VERSION 5.8 ;
BUSBITCHARS "[]" ;
DIVIDERCHAR "/" ;
UNITS
    DATABASE MICRONS 1000 ;
END UNITS

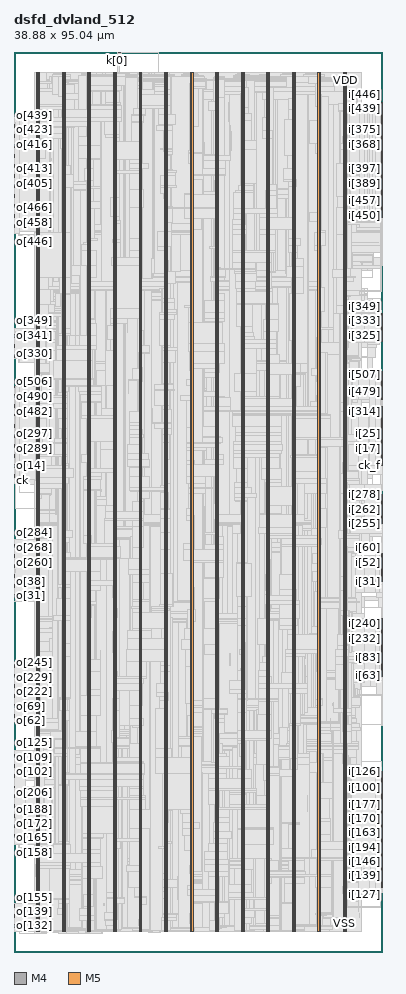
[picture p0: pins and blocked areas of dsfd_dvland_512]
MACRO dsfd_dvland_512
  FOREIGN dsfd_dvland_512 0 0 ;
  CLASS BLOCK ;
  SIZE 38.88 BY 95.04 ;
  PIN ck
    DIRECTION INPUT ;
    USE SIGNAL ;
    PORT
      LAYER M4 ;
        RECT  0 49.776 0.084 49.8 ;
    END
  END ck
  PIN ck_f
    DIRECTION INPUT ;
    USE SIGNAL ;
    PORT
      LAYER M4 ;
        RECT  38.796 51.408 38.88 51.432 ;
    END
  END ck_f
  PIN fault
    DIRECTION OUTPUT ;
    USE SIGNAL ;
    PORT
      LAYER M4 ;
        RECT  0 49.872 0.084 49.896 ;
    END
  END fault
  PIN i[0]
    DIRECTION INPUT ;
    USE SIGNAL ;
    PORT
      LAYER M4 ;
        RECT  38.796 51.504 38.88 51.528 ;
    END
  END i[0]
  PIN i[100]
    DIRECTION INPUT ;
    USE SIGNAL ;
    PORT
      LAYER M4 ;
        RECT  38.796 16.56 38.88 16.584 ;
    END
  END i[100]
  PIN i[101]
    DIRECTION INPUT ;
    USE SIGNAL ;
    PORT
      LAYER M4 ;
        RECT  38.796 16.656 38.88 16.68 ;
    END
  END i[101]
  PIN i[102]
    DIRECTION INPUT ;
    USE SIGNAL ;
    PORT
      LAYER M4 ;
        RECT  38.796 16.752 38.88 16.776 ;
    END
  END i[102]
  PIN i[103]
    DIRECTION INPUT ;
    USE SIGNAL ;
    PORT
      LAYER M4 ;
        RECT  38.796 16.848 38.88 16.872 ;
    END
  END i[103]
  PIN i[104]
    DIRECTION INPUT ;
    USE SIGNAL ;
    PORT
      LAYER M4 ;
        RECT  38.796 16.944 38.88 16.968 ;
    END
  END i[104]
  PIN i[105]
    DIRECTION INPUT ;
    USE SIGNAL ;
    PORT
      LAYER M4 ;
        RECT  38.796 17.04 38.88 17.064 ;
    END
  END i[105]
  PIN i[106]
    DIRECTION INPUT ;
    USE SIGNAL ;
    PORT
      LAYER M4 ;
        RECT  38.796 17.136 38.88 17.16 ;
    END
  END i[106]
  PIN i[107]
    DIRECTION INPUT ;
    USE SIGNAL ;
    PORT
      LAYER M4 ;
        RECT  38.796 17.232 38.88 17.256 ;
    END
  END i[107]
  PIN i[108]
    DIRECTION INPUT ;
    USE SIGNAL ;
    PORT
      LAYER M4 ;
        RECT  38.796 17.328 38.88 17.352 ;
    END
  END i[108]
  PIN i[109]
    DIRECTION INPUT ;
    USE SIGNAL ;
    PORT
      LAYER M4 ;
        RECT  38.796 17.424 38.88 17.448 ;
    END
  END i[109]
  PIN i[10]
    DIRECTION INPUT ;
    USE SIGNAL ;
    PORT
      LAYER M4 ;
        RECT  38.796 52.464 38.88 52.488 ;
    END
  END i[10]
  PIN i[110]
    DIRECTION INPUT ;
    USE SIGNAL ;
    PORT
      LAYER M4 ;
        RECT  38.796 17.52 38.88 17.544 ;
    END
  END i[110]
  PIN i[111]
    DIRECTION INPUT ;
    USE SIGNAL ;
    PORT
      LAYER M4 ;
        RECT  38.796 17.616 38.88 17.64 ;
    END
  END i[111]
  PIN i[112]
    DIRECTION INPUT ;
    USE SIGNAL ;
    PORT
      LAYER M4 ;
        RECT  38.796 17.712 38.88 17.736 ;
    END
  END i[112]
  PIN i[113]
    DIRECTION INPUT ;
    USE SIGNAL ;
    PORT
      LAYER M4 ;
        RECT  38.796 17.808 38.88 17.832 ;
    END
  END i[113]
  PIN i[114]
    DIRECTION INPUT ;
    USE SIGNAL ;
    PORT
      LAYER M4 ;
        RECT  38.796 17.904 38.88 17.928 ;
    END
  END i[114]
  PIN i[115]
    DIRECTION INPUT ;
    USE SIGNAL ;
    PORT
      LAYER M4 ;
        RECT  38.796 18 38.88 18.024 ;
    END
  END i[115]
  PIN i[116]
    DIRECTION INPUT ;
    USE SIGNAL ;
    PORT
      LAYER M4 ;
        RECT  38.796 18.096 38.88 18.12 ;
    END
  END i[116]
  PIN i[117]
    DIRECTION INPUT ;
    USE SIGNAL ;
    PORT
      LAYER M4 ;
        RECT  38.796 18.192 38.88 18.216 ;
    END
  END i[117]
  PIN i[118]
    DIRECTION INPUT ;
    USE SIGNAL ;
    PORT
      LAYER M4 ;
        RECT  38.796 18.288 38.88 18.312 ;
    END
  END i[118]
  PIN i[119]
    DIRECTION INPUT ;
    USE SIGNAL ;
    PORT
      LAYER M4 ;
        RECT  38.796 18.384 38.88 18.408 ;
    END
  END i[119]
  PIN i[11]
    DIRECTION INPUT ;
    USE SIGNAL ;
    PORT
      LAYER M4 ;
        RECT  38.796 52.56 38.88 52.584 ;
    END
  END i[11]
  PIN i[120]
    DIRECTION INPUT ;
    USE SIGNAL ;
    PORT
      LAYER M4 ;
        RECT  38.796 18.48 38.88 18.504 ;
    END
  END i[120]
  PIN i[121]
    DIRECTION INPUT ;
    USE SIGNAL ;
    PORT
      LAYER M4 ;
        RECT  38.796 18.576 38.88 18.6 ;
    END
  END i[121]
  PIN i[122]
    DIRECTION INPUT ;
    USE SIGNAL ;
    PORT
      LAYER M4 ;
        RECT  38.796 18.672 38.88 18.696 ;
    END
  END i[122]
  PIN i[123]
    DIRECTION INPUT ;
    USE SIGNAL ;
    PORT
      LAYER M4 ;
        RECT  38.796 18.768 38.88 18.792 ;
    END
  END i[123]
  PIN i[124]
    DIRECTION INPUT ;
    USE SIGNAL ;
    PORT
      LAYER M4 ;
        RECT  38.796 18.864 38.88 18.888 ;
    END
  END i[124]
  PIN i[125]
    DIRECTION INPUT ;
    USE SIGNAL ;
    PORT
      LAYER M4 ;
        RECT  38.796 18.96 38.88 18.984 ;
    END
  END i[125]
  PIN i[126]
    DIRECTION INPUT ;
    USE SIGNAL ;
    PORT
      LAYER M4 ;
        RECT  38.796 19.056 38.88 19.08 ;
    END
  END i[126]
  PIN i[127]
    DIRECTION INPUT ;
    USE SIGNAL ;
    PORT
      LAYER M4 ;
        RECT  38.796 6.864 38.88 6.888 ;
    END
  END i[127]
  PIN i[128]
    DIRECTION INPUT ;
    USE SIGNAL ;
    PORT
      LAYER M4 ;
        RECT  38.796 6.96 38.88 6.984 ;
    END
  END i[128]
  PIN i[129]
    DIRECTION INPUT ;
    USE SIGNAL ;
    PORT
      LAYER M4 ;
        RECT  38.796 7.056 38.88 7.08 ;
    END
  END i[129]
  PIN i[12]
    DIRECTION INPUT ;
    USE SIGNAL ;
    PORT
      LAYER M4 ;
        RECT  38.796 52.656 38.88 52.68 ;
    END
  END i[12]
  PIN i[130]
    DIRECTION INPUT ;
    USE SIGNAL ;
    PORT
      LAYER M4 ;
        RECT  38.796 7.152 38.88 7.176 ;
    END
  END i[130]
  PIN i[131]
    DIRECTION INPUT ;
    USE SIGNAL ;
    PORT
      LAYER M4 ;
        RECT  38.796 7.248 38.88 7.272 ;
    END
  END i[131]
  PIN i[132]
    DIRECTION INPUT ;
    USE SIGNAL ;
    PORT
      LAYER M4 ;
        RECT  38.796 7.344 38.88 7.368 ;
    END
  END i[132]
  PIN i[133]
    DIRECTION INPUT ;
    USE SIGNAL ;
    PORT
      LAYER M4 ;
        RECT  38.796 7.44 38.88 7.464 ;
    END
  END i[133]
  PIN i[134]
    DIRECTION INPUT ;
    USE SIGNAL ;
    PORT
      LAYER M4 ;
        RECT  38.796 7.536 38.88 7.56 ;
    END
  END i[134]
  PIN i[135]
    DIRECTION INPUT ;
    USE SIGNAL ;
    PORT
      LAYER M4 ;
        RECT  38.796 7.632 38.88 7.656 ;
    END
  END i[135]
  PIN i[136]
    DIRECTION INPUT ;
    USE SIGNAL ;
    PORT
      LAYER M4 ;
        RECT  38.796 7.728 38.88 7.752 ;
    END
  END i[136]
  PIN i[137]
    DIRECTION INPUT ;
    USE SIGNAL ;
    PORT
      LAYER M4 ;
        RECT  38.796 7.824 38.88 7.848 ;
    END
  END i[137]
  PIN i[138]
    DIRECTION INPUT ;
    USE SIGNAL ;
    PORT
      LAYER M4 ;
        RECT  38.796 7.92 38.88 7.944 ;
    END
  END i[138]
  PIN i[139]
    DIRECTION INPUT ;
    USE SIGNAL ;
    PORT
      LAYER M4 ;
        RECT  38.796 8.016 38.88 8.04 ;
    END
  END i[139]
  PIN i[13]
    DIRECTION INPUT ;
    USE SIGNAL ;
    PORT
      LAYER M4 ;
        RECT  38.796 52.752 38.88 52.776 ;
    END
  END i[13]
  PIN i[140]
    DIRECTION INPUT ;
    USE SIGNAL ;
    PORT
      LAYER M4 ;
        RECT  38.796 8.112 38.88 8.136 ;
    END
  END i[140]
  PIN i[141]
    DIRECTION INPUT ;
    USE SIGNAL ;
    PORT
      LAYER M4 ;
        RECT  38.796 8.208 38.88 8.232 ;
    END
  END i[141]
  PIN i[142]
    DIRECTION INPUT ;
    USE SIGNAL ;
    PORT
      LAYER M4 ;
        RECT  38.796 8.304 38.88 8.328 ;
    END
  END i[142]
  PIN i[143]
    DIRECTION INPUT ;
    USE SIGNAL ;
    PORT
      LAYER M4 ;
        RECT  38.796 8.4 38.88 8.424 ;
    END
  END i[143]
  PIN i[144]
    DIRECTION INPUT ;
    USE SIGNAL ;
    PORT
      LAYER M4 ;
        RECT  38.796 8.496 38.88 8.52 ;
    END
  END i[144]
  PIN i[145]
    DIRECTION INPUT ;
    USE SIGNAL ;
    PORT
      LAYER M4 ;
        RECT  38.796 8.592 38.88 8.616 ;
    END
  END i[145]
  PIN i[146]
    DIRECTION INPUT ;
    USE SIGNAL ;
    PORT
      LAYER M4 ;
        RECT  38.796 8.688 38.88 8.712 ;
    END
  END i[146]
  PIN i[147]
    DIRECTION INPUT ;
    USE SIGNAL ;
    PORT
      LAYER M4 ;
        RECT  38.796 8.784 38.88 8.808 ;
    END
  END i[147]
  PIN i[148]
    DIRECTION INPUT ;
    USE SIGNAL ;
    PORT
      LAYER M4 ;
        RECT  38.796 8.88 38.88 8.904 ;
    END
  END i[148]
  PIN i[149]
    DIRECTION INPUT ;
    USE SIGNAL ;
    PORT
      LAYER M4 ;
        RECT  38.796 8.976 38.88 9 ;
    END
  END i[149]
  PIN i[14]
    DIRECTION INPUT ;
    USE SIGNAL ;
    PORT
      LAYER M4 ;
        RECT  38.796 52.848 38.88 52.872 ;
    END
  END i[14]
  PIN i[150]
    DIRECTION INPUT ;
    USE SIGNAL ;
    PORT
      LAYER M4 ;
        RECT  38.796 9.072 38.88 9.096 ;
    END
  END i[150]
  PIN i[151]
    DIRECTION INPUT ;
    USE SIGNAL ;
    PORT
      LAYER M4 ;
        RECT  38.796 9.168 38.88 9.192 ;
    END
  END i[151]
  PIN i[152]
    DIRECTION INPUT ;
    USE SIGNAL ;
    PORT
      LAYER M4 ;
        RECT  38.796 9.264 38.88 9.288 ;
    END
  END i[152]
  PIN i[153]
    DIRECTION INPUT ;
    USE SIGNAL ;
    PORT
      LAYER M4 ;
        RECT  38.796 9.36 38.88 9.384 ;
    END
  END i[153]
  PIN i[154]
    DIRECTION INPUT ;
    USE SIGNAL ;
    PORT
      LAYER M4 ;
        RECT  38.796 9.456 38.88 9.48 ;
    END
  END i[154]
  PIN i[155]
    DIRECTION INPUT ;
    USE SIGNAL ;
    PORT
      LAYER M4 ;
        RECT  38.796 9.552 38.88 9.576 ;
    END
  END i[155]
  PIN i[156]
    DIRECTION INPUT ;
    USE SIGNAL ;
    PORT
      LAYER M4 ;
        RECT  38.796 9.648 38.88 9.672 ;
    END
  END i[156]
  PIN i[157]
    DIRECTION INPUT ;
    USE SIGNAL ;
    PORT
      LAYER M4 ;
        RECT  38.796 9.744 38.88 9.768 ;
    END
  END i[157]
  PIN i[158]
    DIRECTION INPUT ;
    USE SIGNAL ;
    PORT
      LAYER M4 ;
        RECT  38.796 9.84 38.88 9.864 ;
    END
  END i[158]
  PIN i[159]
    DIRECTION INPUT ;
    USE SIGNAL ;
    PORT
      LAYER M4 ;
        RECT  38.796 13.008 38.88 13.032 ;
    END
  END i[159]
  PIN i[15]
    DIRECTION INPUT ;
    USE SIGNAL ;
    PORT
      LAYER M4 ;
        RECT  38.796 52.944 38.88 52.968 ;
    END
  END i[15]
  PIN i[160]
    DIRECTION INPUT ;
    USE SIGNAL ;
    PORT
      LAYER M4 ;
        RECT  38.796 13.104 38.88 13.128 ;
    END
  END i[160]
  PIN i[161]
    DIRECTION INPUT ;
    USE SIGNAL ;
    PORT
      LAYER M4 ;
        RECT  38.796 13.2 38.88 13.224 ;
    END
  END i[161]
  PIN i[162]
    DIRECTION INPUT ;
    USE SIGNAL ;
    PORT
      LAYER M4 ;
        RECT  38.796 13.296 38.88 13.32 ;
    END
  END i[162]
  PIN i[163]
    DIRECTION INPUT ;
    USE SIGNAL ;
    PORT
      LAYER M4 ;
        RECT  38.796 13.392 38.88 13.416 ;
    END
  END i[163]
  PIN i[164]
    DIRECTION INPUT ;
    USE SIGNAL ;
    PORT
      LAYER M4 ;
        RECT  38.796 13.488 38.88 13.512 ;
    END
  END i[164]
  PIN i[165]
    DIRECTION INPUT ;
    USE SIGNAL ;
    PORT
      LAYER M4 ;
        RECT  38.796 13.584 38.88 13.608 ;
    END
  END i[165]
  PIN i[166]
    DIRECTION INPUT ;
    USE SIGNAL ;
    PORT
      LAYER M4 ;
        RECT  38.796 13.68 38.88 13.704 ;
    END
  END i[166]
  PIN i[167]
    DIRECTION INPUT ;
    USE SIGNAL ;
    PORT
      LAYER M4 ;
        RECT  38.796 13.776 38.88 13.8 ;
    END
  END i[167]
  PIN i[168]
    DIRECTION INPUT ;
    USE SIGNAL ;
    PORT
      LAYER M4 ;
        RECT  38.796 13.872 38.88 13.896 ;
    END
  END i[168]
  PIN i[169]
    DIRECTION INPUT ;
    USE SIGNAL ;
    PORT
      LAYER M4 ;
        RECT  38.796 13.968 38.88 13.992 ;
    END
  END i[169]
  PIN i[16]
    DIRECTION INPUT ;
    USE SIGNAL ;
    PORT
      LAYER M4 ;
        RECT  38.796 53.04 38.88 53.064 ;
    END
  END i[16]
  PIN i[170]
    DIRECTION INPUT ;
    USE SIGNAL ;
    PORT
      LAYER M4 ;
        RECT  38.796 14.064 38.88 14.088 ;
    END
  END i[170]
  PIN i[171]
    DIRECTION INPUT ;
    USE SIGNAL ;
    PORT
      LAYER M4 ;
        RECT  38.796 14.16 38.88 14.184 ;
    END
  END i[171]
  PIN i[172]
    DIRECTION INPUT ;
    USE SIGNAL ;
    PORT
      LAYER M4 ;
        RECT  38.796 14.256 38.88 14.28 ;
    END
  END i[172]
  PIN i[173]
    DIRECTION INPUT ;
    USE SIGNAL ;
    PORT
      LAYER M4 ;
        RECT  38.796 14.352 38.88 14.376 ;
    END
  END i[173]
  PIN i[174]
    DIRECTION INPUT ;
    USE SIGNAL ;
    PORT
      LAYER M4 ;
        RECT  38.796 14.448 38.88 14.472 ;
    END
  END i[174]
  PIN i[175]
    DIRECTION INPUT ;
    USE SIGNAL ;
    PORT
      LAYER M4 ;
        RECT  38.796 14.544 38.88 14.568 ;
    END
  END i[175]
  PIN i[176]
    DIRECTION INPUT ;
    USE SIGNAL ;
    PORT
      LAYER M4 ;
        RECT  38.796 14.64 38.88 14.664 ;
    END
  END i[176]
  PIN i[177]
    DIRECTION INPUT ;
    USE SIGNAL ;
    PORT
      LAYER M4 ;
        RECT  38.796 14.736 38.88 14.76 ;
    END
  END i[177]
  PIN i[178]
    DIRECTION INPUT ;
    USE SIGNAL ;
    PORT
      LAYER M4 ;
        RECT  38.796 14.832 38.88 14.856 ;
    END
  END i[178]
  PIN i[179]
    DIRECTION INPUT ;
    USE SIGNAL ;
    PORT
      LAYER M4 ;
        RECT  38.796 14.928 38.88 14.952 ;
    END
  END i[179]
  PIN i[17]
    DIRECTION INPUT ;
    USE SIGNAL ;
    PORT
      LAYER M4 ;
        RECT  38.796 53.136 38.88 53.16 ;
    END
  END i[17]
  PIN i[180]
    DIRECTION INPUT ;
    USE SIGNAL ;
    PORT
      LAYER M4 ;
        RECT  38.796 15.024 38.88 15.048 ;
    END
  END i[180]
  PIN i[181]
    DIRECTION INPUT ;
    USE SIGNAL ;
    PORT
      LAYER M4 ;
        RECT  38.796 15.12 38.88 15.144 ;
    END
  END i[181]
  PIN i[182]
    DIRECTION INPUT ;
    USE SIGNAL ;
    PORT
      LAYER M4 ;
        RECT  38.796 15.216 38.88 15.24 ;
    END
  END i[182]
  PIN i[183]
    DIRECTION INPUT ;
    USE SIGNAL ;
    PORT
      LAYER M4 ;
        RECT  38.796 15.312 38.88 15.336 ;
    END
  END i[183]
  PIN i[184]
    DIRECTION INPUT ;
    USE SIGNAL ;
    PORT
      LAYER M4 ;
        RECT  38.796 15.408 38.88 15.432 ;
    END
  END i[184]
  PIN i[185]
    DIRECTION INPUT ;
    USE SIGNAL ;
    PORT
      LAYER M4 ;
        RECT  38.796 15.504 38.88 15.528 ;
    END
  END i[185]
  PIN i[186]
    DIRECTION INPUT ;
    USE SIGNAL ;
    PORT
      LAYER M4 ;
        RECT  38.796 15.6 38.88 15.624 ;
    END
  END i[186]
  PIN i[187]
    DIRECTION INPUT ;
    USE SIGNAL ;
    PORT
      LAYER M4 ;
        RECT  38.796 15.696 38.88 15.72 ;
    END
  END i[187]
  PIN i[188]
    DIRECTION INPUT ;
    USE SIGNAL ;
    PORT
      LAYER M4 ;
        RECT  38.796 15.792 38.88 15.816 ;
    END
  END i[188]
  PIN i[189]
    DIRECTION INPUT ;
    USE SIGNAL ;
    PORT
      LAYER M4 ;
        RECT  38.796 15.888 38.88 15.912 ;
    END
  END i[189]
  PIN i[18]
    DIRECTION INPUT ;
    USE SIGNAL ;
    PORT
      LAYER M4 ;
        RECT  38.796 53.232 38.88 53.256 ;
    END
  END i[18]
  PIN i[190]
    DIRECTION INPUT ;
    USE SIGNAL ;
    PORT
      LAYER M4 ;
        RECT  38.796 15.984 38.88 16.008 ;
    END
  END i[190]
  PIN i[191]
    DIRECTION INPUT ;
    USE SIGNAL ;
    PORT
      LAYER M4 ;
        RECT  38.796 9.936 38.88 9.96 ;
    END
  END i[191]
  PIN i[192]
    DIRECTION INPUT ;
    USE SIGNAL ;
    PORT
      LAYER M4 ;
        RECT  38.796 10.032 38.88 10.056 ;
    END
  END i[192]
  PIN i[193]
    DIRECTION INPUT ;
    USE SIGNAL ;
    PORT
      LAYER M4 ;
        RECT  38.796 10.128 38.88 10.152 ;
    END
  END i[193]
  PIN i[194]
    DIRECTION INPUT ;
    USE SIGNAL ;
    PORT
      LAYER M4 ;
        RECT  38.796 10.224 38.88 10.248 ;
    END
  END i[194]
  PIN i[195]
    DIRECTION INPUT ;
    USE SIGNAL ;
    PORT
      LAYER M4 ;
        RECT  38.796 10.32 38.88 10.344 ;
    END
  END i[195]
  PIN i[196]
    DIRECTION INPUT ;
    USE SIGNAL ;
    PORT
      LAYER M4 ;
        RECT  38.796 10.416 38.88 10.44 ;
    END
  END i[196]
  PIN i[197]
    DIRECTION INPUT ;
    USE SIGNAL ;
    PORT
      LAYER M4 ;
        RECT  38.796 10.512 38.88 10.536 ;
    END
  END i[197]
  PIN i[198]
    DIRECTION INPUT ;
    USE SIGNAL ;
    PORT
      LAYER M4 ;
        RECT  38.796 10.608 38.88 10.632 ;
    END
  END i[198]
  PIN i[199]
    DIRECTION INPUT ;
    USE SIGNAL ;
    PORT
      LAYER M4 ;
        RECT  38.796 10.704 38.88 10.728 ;
    END
  END i[199]
  PIN i[19]
    DIRECTION INPUT ;
    USE SIGNAL ;
    PORT
      LAYER M4 ;
        RECT  38.796 53.328 38.88 53.352 ;
    END
  END i[19]
  PIN i[1]
    DIRECTION INPUT ;
    USE SIGNAL ;
    PORT
      LAYER M4 ;
        RECT  38.796 51.6 38.88 51.624 ;
    END
  END i[1]
  PIN i[200]
    DIRECTION INPUT ;
    USE SIGNAL ;
    PORT
      LAYER M4 ;
        RECT  38.796 10.8 38.88 10.824 ;
    END
  END i[200]
  PIN i[201]
    DIRECTION INPUT ;
    USE SIGNAL ;
    PORT
      LAYER M4 ;
        RECT  38.796 10.896 38.88 10.92 ;
    END
  END i[201]
  PIN i[202]
    DIRECTION INPUT ;
    USE SIGNAL ;
    PORT
      LAYER M4 ;
        RECT  38.796 10.992 38.88 11.016 ;
    END
  END i[202]
  PIN i[203]
    DIRECTION INPUT ;
    USE SIGNAL ;
    PORT
      LAYER M4 ;
        RECT  38.796 11.088 38.88 11.112 ;
    END
  END i[203]
  PIN i[204]
    DIRECTION INPUT ;
    USE SIGNAL ;
    PORT
      LAYER M4 ;
        RECT  38.796 11.184 38.88 11.208 ;
    END
  END i[204]
  PIN i[205]
    DIRECTION INPUT ;
    USE SIGNAL ;
    PORT
      LAYER M4 ;
        RECT  38.796 11.28 38.88 11.304 ;
    END
  END i[205]
  PIN i[206]
    DIRECTION INPUT ;
    USE SIGNAL ;
    PORT
      LAYER M4 ;
        RECT  38.796 11.376 38.88 11.4 ;
    END
  END i[206]
  PIN i[207]
    DIRECTION INPUT ;
    USE SIGNAL ;
    PORT
      LAYER M4 ;
        RECT  38.796 11.472 38.88 11.496 ;
    END
  END i[207]
  PIN i[208]
    DIRECTION INPUT ;
    USE SIGNAL ;
    PORT
      LAYER M4 ;
        RECT  38.796 11.568 38.88 11.592 ;
    END
  END i[208]
  PIN i[209]
    DIRECTION INPUT ;
    USE SIGNAL ;
    PORT
      LAYER M4 ;
        RECT  38.796 11.664 38.88 11.688 ;
    END
  END i[209]
  PIN i[20]
    DIRECTION INPUT ;
    USE SIGNAL ;
    PORT
      LAYER M4 ;
        RECT  38.796 53.424 38.88 53.448 ;
    END
  END i[20]
  PIN i[210]
    DIRECTION INPUT ;
    USE SIGNAL ;
    PORT
      LAYER M4 ;
        RECT  38.796 11.76 38.88 11.784 ;
    END
  END i[210]
  PIN i[211]
    DIRECTION INPUT ;
    USE SIGNAL ;
    PORT
      LAYER M4 ;
        RECT  38.796 11.856 38.88 11.88 ;
    END
  END i[211]
  PIN i[212]
    DIRECTION INPUT ;
    USE SIGNAL ;
    PORT
      LAYER M4 ;
        RECT  38.796 11.952 38.88 11.976 ;
    END
  END i[212]
  PIN i[213]
    DIRECTION INPUT ;
    USE SIGNAL ;
    PORT
      LAYER M4 ;
        RECT  38.796 12.048 38.88 12.072 ;
    END
  END i[213]
  PIN i[214]
    DIRECTION INPUT ;
    USE SIGNAL ;
    PORT
      LAYER M4 ;
        RECT  38.796 12.144 38.88 12.168 ;
    END
  END i[214]
  PIN i[215]
    DIRECTION INPUT ;
    USE SIGNAL ;
    PORT
      LAYER M4 ;
        RECT  38.796 12.24 38.88 12.264 ;
    END
  END i[215]
  PIN i[216]
    DIRECTION INPUT ;
    USE SIGNAL ;
    PORT
      LAYER M4 ;
        RECT  38.796 12.336 38.88 12.36 ;
    END
  END i[216]
  PIN i[217]
    DIRECTION INPUT ;
    USE SIGNAL ;
    PORT
      LAYER M4 ;
        RECT  38.796 12.432 38.88 12.456 ;
    END
  END i[217]
  PIN i[218]
    DIRECTION INPUT ;
    USE SIGNAL ;
    PORT
      LAYER M4 ;
        RECT  38.796 12.528 38.88 12.552 ;
    END
  END i[218]
  PIN i[219]
    DIRECTION INPUT ;
    USE SIGNAL ;
    PORT
      LAYER M4 ;
        RECT  38.796 12.624 38.88 12.648 ;
    END
  END i[219]
  PIN i[21]
    DIRECTION INPUT ;
    USE SIGNAL ;
    PORT
      LAYER M4 ;
        RECT  38.796 53.52 38.88 53.544 ;
    END
  END i[21]
  PIN i[220]
    DIRECTION INPUT ;
    USE SIGNAL ;
    PORT
      LAYER M4 ;
        RECT  38.796 12.72 38.88 12.744 ;
    END
  END i[220]
  PIN i[221]
    DIRECTION INPUT ;
    USE SIGNAL ;
    PORT
      LAYER M4 ;
        RECT  38.796 12.816 38.88 12.84 ;
    END
  END i[221]
  PIN i[222]
    DIRECTION INPUT ;
    USE SIGNAL ;
    PORT
      LAYER M4 ;
        RECT  38.796 12.912 38.88 12.936 ;
    END
  END i[222]
  PIN i[223]
    DIRECTION INPUT ;
    USE SIGNAL ;
    PORT
      LAYER M4 ;
        RECT  38.796 32.208 38.88 32.232 ;
    END
  END i[223]
  PIN i[224]
    DIRECTION INPUT ;
    USE SIGNAL ;
    PORT
      LAYER M4 ;
        RECT  38.796 32.304 38.88 32.328 ;
    END
  END i[224]
  PIN i[225]
    DIRECTION INPUT ;
    USE SIGNAL ;
    PORT
      LAYER M4 ;
        RECT  38.796 32.4 38.88 32.424 ;
    END
  END i[225]
  PIN i[226]
    DIRECTION INPUT ;
    USE SIGNAL ;
    PORT
      LAYER M4 ;
        RECT  38.796 32.496 38.88 32.52 ;
    END
  END i[226]
  PIN i[227]
    DIRECTION INPUT ;
    USE SIGNAL ;
    PORT
      LAYER M4 ;
        RECT  38.796 32.592 38.88 32.616 ;
    END
  END i[227]
  PIN i[228]
    DIRECTION INPUT ;
    USE SIGNAL ;
    PORT
      LAYER M4 ;
        RECT  38.796 32.688 38.88 32.712 ;
    END
  END i[228]
  PIN i[229]
    DIRECTION INPUT ;
    USE SIGNAL ;
    PORT
      LAYER M4 ;
        RECT  38.796 32.784 38.88 32.808 ;
    END
  END i[229]
  PIN i[22]
    DIRECTION INPUT ;
    USE SIGNAL ;
    PORT
      LAYER M4 ;
        RECT  38.796 53.616 38.88 53.64 ;
    END
  END i[22]
  PIN i[230]
    DIRECTION INPUT ;
    USE SIGNAL ;
    PORT
      LAYER M4 ;
        RECT  38.796 32.88 38.88 32.904 ;
    END
  END i[230]
  PIN i[231]
    DIRECTION INPUT ;
    USE SIGNAL ;
    PORT
      LAYER M4 ;
        RECT  38.796 32.976 38.88 33 ;
    END
  END i[231]
  PIN i[232]
    DIRECTION INPUT ;
    USE SIGNAL ;
    PORT
      LAYER M4 ;
        RECT  38.796 33.072 38.88 33.096 ;
    END
  END i[232]
  PIN i[233]
    DIRECTION INPUT ;
    USE SIGNAL ;
    PORT
      LAYER M4 ;
        RECT  38.796 33.168 38.88 33.192 ;
    END
  END i[233]
  PIN i[234]
    DIRECTION INPUT ;
    USE SIGNAL ;
    PORT
      LAYER M4 ;
        RECT  38.796 33.264 38.88 33.288 ;
    END
  END i[234]
  PIN i[235]
    DIRECTION INPUT ;
    USE SIGNAL ;
    PORT
      LAYER M4 ;
        RECT  38.796 33.36 38.88 33.384 ;
    END
  END i[235]
  PIN i[236]
    DIRECTION INPUT ;
    USE SIGNAL ;
    PORT
      LAYER M4 ;
        RECT  38.796 33.456 38.88 33.48 ;
    END
  END i[236]
  PIN i[237]
    DIRECTION INPUT ;
    USE SIGNAL ;
    PORT
      LAYER M4 ;
        RECT  38.796 33.552 38.88 33.576 ;
    END
  END i[237]
  PIN i[238]
    DIRECTION INPUT ;
    USE SIGNAL ;
    PORT
      LAYER M4 ;
        RECT  38.796 33.648 38.88 33.672 ;
    END
  END i[238]
  PIN i[239]
    DIRECTION INPUT ;
    USE SIGNAL ;
    PORT
      LAYER M4 ;
        RECT  38.796 33.744 38.88 33.768 ;
    END
  END i[239]
  PIN i[23]
    DIRECTION INPUT ;
    USE SIGNAL ;
    PORT
      LAYER M4 ;
        RECT  38.796 53.712 38.88 53.736 ;
    END
  END i[23]
  PIN i[240]
    DIRECTION INPUT ;
    USE SIGNAL ;
    PORT
      LAYER M4 ;
        RECT  38.796 33.84 38.88 33.864 ;
    END
  END i[240]
  PIN i[241]
    DIRECTION INPUT ;
    USE SIGNAL ;
    PORT
      LAYER M4 ;
        RECT  38.796 33.936 38.88 33.96 ;
    END
  END i[241]
  PIN i[242]
    DIRECTION INPUT ;
    USE SIGNAL ;
    PORT
      LAYER M4 ;
        RECT  38.796 34.032 38.88 34.056 ;
    END
  END i[242]
  PIN i[243]
    DIRECTION INPUT ;
    USE SIGNAL ;
    PORT
      LAYER M4 ;
        RECT  38.796 34.128 38.88 34.152 ;
    END
  END i[243]
  PIN i[244]
    DIRECTION INPUT ;
    USE SIGNAL ;
    PORT
      LAYER M4 ;
        RECT  38.796 34.224 38.88 34.248 ;
    END
  END i[244]
  PIN i[245]
    DIRECTION INPUT ;
    USE SIGNAL ;
    PORT
      LAYER M4 ;
        RECT  38.796 34.32 38.88 34.344 ;
    END
  END i[245]
  PIN i[246]
    DIRECTION INPUT ;
    USE SIGNAL ;
    PORT
      LAYER M4 ;
        RECT  38.796 34.416 38.88 34.44 ;
    END
  END i[246]
  PIN i[247]
    DIRECTION INPUT ;
    USE SIGNAL ;
    PORT
      LAYER M4 ;
        RECT  38.796 34.512 38.88 34.536 ;
    END
  END i[247]
  PIN i[248]
    DIRECTION INPUT ;
    USE SIGNAL ;
    PORT
      LAYER M4 ;
        RECT  38.796 34.608 38.88 34.632 ;
    END
  END i[248]
  PIN i[249]
    DIRECTION INPUT ;
    USE SIGNAL ;
    PORT
      LAYER M4 ;
        RECT  38.796 34.704 38.88 34.728 ;
    END
  END i[249]
  PIN i[24]
    DIRECTION INPUT ;
    USE SIGNAL ;
    PORT
      LAYER M4 ;
        RECT  38.796 53.808 38.88 53.832 ;
    END
  END i[24]
  PIN i[250]
    DIRECTION INPUT ;
    USE SIGNAL ;
    PORT
      LAYER M4 ;
        RECT  38.796 34.8 38.88 34.824 ;
    END
  END i[250]
  PIN i[251]
    DIRECTION INPUT ;
    USE SIGNAL ;
    PORT
      LAYER M4 ;
        RECT  38.796 34.896 38.88 34.92 ;
    END
  END i[251]
  PIN i[252]
    DIRECTION INPUT ;
    USE SIGNAL ;
    PORT
      LAYER M4 ;
        RECT  38.796 34.992 38.88 35.016 ;
    END
  END i[252]
  PIN i[253]
    DIRECTION INPUT ;
    USE SIGNAL ;
    PORT
      LAYER M4 ;
        RECT  38.796 35.088 38.88 35.112 ;
    END
  END i[253]
  PIN i[254]
    DIRECTION INPUT ;
    USE SIGNAL ;
    PORT
      LAYER M4 ;
        RECT  38.796 35.184 38.88 35.208 ;
    END
  END i[254]
  PIN i[255]
    DIRECTION INPUT ;
    USE SIGNAL ;
    PORT
      LAYER M4 ;
        RECT  38.796 45.264 38.88 45.288 ;
    END
  END i[255]
  PIN i[256]
    DIRECTION INPUT ;
    USE SIGNAL ;
    PORT
      LAYER M4 ;
        RECT  38.796 45.36 38.88 45.384 ;
    END
  END i[256]
  PIN i[257]
    DIRECTION INPUT ;
    USE SIGNAL ;
    PORT
      LAYER M4 ;
        RECT  38.796 45.456 38.88 45.48 ;
    END
  END i[257]
  PIN i[258]
    DIRECTION INPUT ;
    USE SIGNAL ;
    PORT
      LAYER M4 ;
        RECT  38.796 45.552 38.88 45.576 ;
    END
  END i[258]
  PIN i[259]
    DIRECTION INPUT ;
    USE SIGNAL ;
    PORT
      LAYER M4 ;
        RECT  38.796 45.648 38.88 45.672 ;
    END
  END i[259]
  PIN i[25]
    DIRECTION INPUT ;
    USE SIGNAL ;
    PORT
      LAYER M4 ;
        RECT  38.796 53.904 38.88 53.928 ;
    END
  END i[25]
  PIN i[260]
    DIRECTION INPUT ;
    USE SIGNAL ;
    PORT
      LAYER M4 ;
        RECT  38.796 45.744 38.88 45.768 ;
    END
  END i[260]
  PIN i[261]
    DIRECTION INPUT ;
    USE SIGNAL ;
    PORT
      LAYER M4 ;
        RECT  38.796 45.84 38.88 45.864 ;
    END
  END i[261]
  PIN i[262]
    DIRECTION INPUT ;
    USE SIGNAL ;
    PORT
      LAYER M4 ;
        RECT  38.796 45.936 38.88 45.96 ;
    END
  END i[262]
  PIN i[263]
    DIRECTION INPUT ;
    USE SIGNAL ;
    PORT
      LAYER M4 ;
        RECT  38.796 46.032 38.88 46.056 ;
    END
  END i[263]
  PIN i[264]
    DIRECTION INPUT ;
    USE SIGNAL ;
    PORT
      LAYER M4 ;
        RECT  38.796 46.128 38.88 46.152 ;
    END
  END i[264]
  PIN i[265]
    DIRECTION INPUT ;
    USE SIGNAL ;
    PORT
      LAYER M4 ;
        RECT  38.796 46.224 38.88 46.248 ;
    END
  END i[265]
  PIN i[266]
    DIRECTION INPUT ;
    USE SIGNAL ;
    PORT
      LAYER M4 ;
        RECT  38.796 46.32 38.88 46.344 ;
    END
  END i[266]
  PIN i[267]
    DIRECTION INPUT ;
    USE SIGNAL ;
    PORT
      LAYER M4 ;
        RECT  38.796 46.416 38.88 46.44 ;
    END
  END i[267]
  PIN i[268]
    DIRECTION INPUT ;
    USE SIGNAL ;
    PORT
      LAYER M4 ;
        RECT  38.796 46.512 38.88 46.536 ;
    END
  END i[268]
  PIN i[269]
    DIRECTION INPUT ;
    USE SIGNAL ;
    PORT
      LAYER M4 ;
        RECT  38.796 46.608 38.88 46.632 ;
    END
  END i[269]
  PIN i[26]
    DIRECTION INPUT ;
    USE SIGNAL ;
    PORT
      LAYER M4 ;
        RECT  38.796 54 38.88 54.024 ;
    END
  END i[26]
  PIN i[270]
    DIRECTION INPUT ;
    USE SIGNAL ;
    PORT
      LAYER M4 ;
        RECT  38.796 46.704 38.88 46.728 ;
    END
  END i[270]
  PIN i[271]
    DIRECTION INPUT ;
    USE SIGNAL ;
    PORT
      LAYER M4 ;
        RECT  38.796 46.8 38.88 46.824 ;
    END
  END i[271]
  PIN i[272]
    DIRECTION INPUT ;
    USE SIGNAL ;
    PORT
      LAYER M4 ;
        RECT  38.796 46.896 38.88 46.92 ;
    END
  END i[272]
  PIN i[273]
    DIRECTION INPUT ;
    USE SIGNAL ;
    PORT
      LAYER M4 ;
        RECT  38.796 46.992 38.88 47.016 ;
    END
  END i[273]
  PIN i[274]
    DIRECTION INPUT ;
    USE SIGNAL ;
    PORT
      LAYER M4 ;
        RECT  38.796 47.088 38.88 47.112 ;
    END
  END i[274]
  PIN i[275]
    DIRECTION INPUT ;
    USE SIGNAL ;
    PORT
      LAYER M4 ;
        RECT  38.796 47.184 38.88 47.208 ;
    END
  END i[275]
  PIN i[276]
    DIRECTION INPUT ;
    USE SIGNAL ;
    PORT
      LAYER M4 ;
        RECT  38.796 47.28 38.88 47.304 ;
    END
  END i[276]
  PIN i[277]
    DIRECTION INPUT ;
    USE SIGNAL ;
    PORT
      LAYER M4 ;
        RECT  38.796 47.376 38.88 47.4 ;
    END
  END i[277]
  PIN i[278]
    DIRECTION INPUT ;
    USE SIGNAL ;
    PORT
      LAYER M4 ;
        RECT  38.796 47.472 38.88 47.496 ;
    END
  END i[278]
  PIN i[279]
    DIRECTION INPUT ;
    USE SIGNAL ;
    PORT
      LAYER M4 ;
        RECT  38.796 47.568 38.88 47.592 ;
    END
  END i[279]
  PIN i[27]
    DIRECTION INPUT ;
    USE SIGNAL ;
    PORT
      LAYER M4 ;
        RECT  38.796 54.096 38.88 54.12 ;
    END
  END i[27]
  PIN i[280]
    DIRECTION INPUT ;
    USE SIGNAL ;
    PORT
      LAYER M4 ;
        RECT  38.796 47.664 38.88 47.688 ;
    END
  END i[280]
  PIN i[281]
    DIRECTION INPUT ;
    USE SIGNAL ;
    PORT
      LAYER M4 ;
        RECT  38.796 47.76 38.88 47.784 ;
    END
  END i[281]
  PIN i[282]
    DIRECTION INPUT ;
    USE SIGNAL ;
    PORT
      LAYER M4 ;
        RECT  38.796 47.856 38.88 47.88 ;
    END
  END i[282]
  PIN i[283]
    DIRECTION INPUT ;
    USE SIGNAL ;
    PORT
      LAYER M4 ;
        RECT  38.796 47.952 38.88 47.976 ;
    END
  END i[283]
  PIN i[284]
    DIRECTION INPUT ;
    USE SIGNAL ;
    PORT
      LAYER M4 ;
        RECT  38.796 48.048 38.88 48.072 ;
    END
  END i[284]
  PIN i[285]
    DIRECTION INPUT ;
    USE SIGNAL ;
    PORT
      LAYER M4 ;
        RECT  38.796 48.144 38.88 48.168 ;
    END
  END i[285]
  PIN i[286]
    DIRECTION INPUT ;
    USE SIGNAL ;
    PORT
      LAYER M4 ;
        RECT  38.796 48.24 38.88 48.264 ;
    END
  END i[286]
  PIN i[287]
    DIRECTION INPUT ;
    USE SIGNAL ;
    PORT
      LAYER M4 ;
        RECT  38.796 54.48 38.88 54.504 ;
    END
  END i[287]
  PIN i[288]
    DIRECTION INPUT ;
    USE SIGNAL ;
    PORT
      LAYER M4 ;
        RECT  38.796 54.576 38.88 54.6 ;
    END
  END i[288]
  PIN i[289]
    DIRECTION INPUT ;
    USE SIGNAL ;
    PORT
      LAYER M4 ;
        RECT  38.796 54.672 38.88 54.696 ;
    END
  END i[289]
  PIN i[28]
    DIRECTION INPUT ;
    USE SIGNAL ;
    PORT
      LAYER M4 ;
        RECT  38.796 54.192 38.88 54.216 ;
    END
  END i[28]
  PIN i[290]
    DIRECTION INPUT ;
    USE SIGNAL ;
    PORT
      LAYER M4 ;
        RECT  38.796 54.768 38.88 54.792 ;
    END
  END i[290]
  PIN i[291]
    DIRECTION INPUT ;
    USE SIGNAL ;
    PORT
      LAYER M4 ;
        RECT  38.796 54.864 38.88 54.888 ;
    END
  END i[291]
  PIN i[292]
    DIRECTION INPUT ;
    USE SIGNAL ;
    PORT
      LAYER M4 ;
        RECT  38.796 54.96 38.88 54.984 ;
    END
  END i[292]
  PIN i[293]
    DIRECTION INPUT ;
    USE SIGNAL ;
    PORT
      LAYER M4 ;
        RECT  38.796 55.056 38.88 55.08 ;
    END
  END i[293]
  PIN i[294]
    DIRECTION INPUT ;
    USE SIGNAL ;
    PORT
      LAYER M4 ;
        RECT  38.796 55.152 38.88 55.176 ;
    END
  END i[294]
  PIN i[295]
    DIRECTION INPUT ;
    USE SIGNAL ;
    PORT
      LAYER M4 ;
        RECT  38.796 55.248 38.88 55.272 ;
    END
  END i[295]
  PIN i[296]
    DIRECTION INPUT ;
    USE SIGNAL ;
    PORT
      LAYER M4 ;
        RECT  38.796 55.344 38.88 55.368 ;
    END
  END i[296]
  PIN i[297]
    DIRECTION INPUT ;
    USE SIGNAL ;
    PORT
      LAYER M4 ;
        RECT  38.796 55.44 38.88 55.464 ;
    END
  END i[297]
  PIN i[298]
    DIRECTION INPUT ;
    USE SIGNAL ;
    PORT
      LAYER M4 ;
        RECT  38.796 55.536 38.88 55.56 ;
    END
  END i[298]
  PIN i[299]
    DIRECTION INPUT ;
    USE SIGNAL ;
    PORT
      LAYER M4 ;
        RECT  38.796 55.632 38.88 55.656 ;
    END
  END i[299]
  PIN i[29]
    DIRECTION INPUT ;
    USE SIGNAL ;
    PORT
      LAYER M4 ;
        RECT  38.796 54.288 38.88 54.312 ;
    END
  END i[29]
  PIN i[2]
    DIRECTION INPUT ;
    USE SIGNAL ;
    PORT
      LAYER M4 ;
        RECT  38.796 51.696 38.88 51.72 ;
    END
  END i[2]
  PIN i[300]
    DIRECTION INPUT ;
    USE SIGNAL ;
    PORT
      LAYER M4 ;
        RECT  38.796 55.728 38.88 55.752 ;
    END
  END i[300]
  PIN i[301]
    DIRECTION INPUT ;
    USE SIGNAL ;
    PORT
      LAYER M4 ;
        RECT  38.796 55.824 38.88 55.848 ;
    END
  END i[301]
  PIN i[302]
    DIRECTION INPUT ;
    USE SIGNAL ;
    PORT
      LAYER M4 ;
        RECT  38.796 55.92 38.88 55.944 ;
    END
  END i[302]
  PIN i[303]
    DIRECTION INPUT ;
    USE SIGNAL ;
    PORT
      LAYER M4 ;
        RECT  38.796 56.016 38.88 56.04 ;
    END
  END i[303]
  PIN i[304]
    DIRECTION INPUT ;
    USE SIGNAL ;
    PORT
      LAYER M4 ;
        RECT  38.796 56.112 38.88 56.136 ;
    END
  END i[304]
  PIN i[305]
    DIRECTION INPUT ;
    USE SIGNAL ;
    PORT
      LAYER M4 ;
        RECT  38.796 56.208 38.88 56.232 ;
    END
  END i[305]
  PIN i[306]
    DIRECTION INPUT ;
    USE SIGNAL ;
    PORT
      LAYER M4 ;
        RECT  38.796 56.304 38.88 56.328 ;
    END
  END i[306]
  PIN i[307]
    DIRECTION INPUT ;
    USE SIGNAL ;
    PORT
      LAYER M4 ;
        RECT  38.796 56.4 38.88 56.424 ;
    END
  END i[307]
  PIN i[308]
    DIRECTION INPUT ;
    USE SIGNAL ;
    PORT
      LAYER M4 ;
        RECT  38.796 56.496 38.88 56.52 ;
    END
  END i[308]
  PIN i[309]
    DIRECTION INPUT ;
    USE SIGNAL ;
    PORT
      LAYER M4 ;
        RECT  38.796 56.592 38.88 56.616 ;
    END
  END i[309]
  PIN i[30]
    DIRECTION INPUT ;
    USE SIGNAL ;
    PORT
      LAYER M4 ;
        RECT  38.796 54.384 38.88 54.408 ;
    END
  END i[30]
  PIN i[310]
    DIRECTION INPUT ;
    USE SIGNAL ;
    PORT
      LAYER M4 ;
        RECT  38.796 56.688 38.88 56.712 ;
    END
  END i[310]
  PIN i[311]
    DIRECTION INPUT ;
    USE SIGNAL ;
    PORT
      LAYER M4 ;
        RECT  38.796 56.784 38.88 56.808 ;
    END
  END i[311]
  PIN i[312]
    DIRECTION INPUT ;
    USE SIGNAL ;
    PORT
      LAYER M4 ;
        RECT  38.796 56.88 38.88 56.904 ;
    END
  END i[312]
  PIN i[313]
    DIRECTION INPUT ;
    USE SIGNAL ;
    PORT
      LAYER M4 ;
        RECT  38.796 56.976 38.88 57 ;
    END
  END i[313]
  PIN i[314]
    DIRECTION INPUT ;
    USE SIGNAL ;
    PORT
      LAYER M4 ;
        RECT  38.796 57.072 38.88 57.096 ;
    END
  END i[314]
  PIN i[315]
    DIRECTION INPUT ;
    USE SIGNAL ;
    PORT
      LAYER M4 ;
        RECT  38.796 57.168 38.88 57.192 ;
    END
  END i[315]
  PIN i[316]
    DIRECTION INPUT ;
    USE SIGNAL ;
    PORT
      LAYER M4 ;
        RECT  38.796 57.264 38.88 57.288 ;
    END
  END i[316]
  PIN i[317]
    DIRECTION INPUT ;
    USE SIGNAL ;
    PORT
      LAYER M4 ;
        RECT  38.796 57.36 38.88 57.384 ;
    END
  END i[317]
  PIN i[318]
    DIRECTION INPUT ;
    USE SIGNAL ;
    PORT
      LAYER M4 ;
        RECT  38.796 57.456 38.88 57.48 ;
    END
  END i[318]
  PIN i[319]
    DIRECTION INPUT ;
    USE SIGNAL ;
    PORT
      LAYER M4 ;
        RECT  38.796 64.464 38.88 64.488 ;
    END
  END i[319]
  PIN i[31]
    DIRECTION INPUT ;
    USE SIGNAL ;
    PORT
      LAYER M4 ;
        RECT  38.796 39.12 38.88 39.144 ;
    END
  END i[31]
  PIN i[320]
    DIRECTION INPUT ;
    USE SIGNAL ;
    PORT
      LAYER M4 ;
        RECT  38.796 64.56 38.88 64.584 ;
    END
  END i[320]
  PIN i[321]
    DIRECTION INPUT ;
    USE SIGNAL ;
    PORT
      LAYER M4 ;
        RECT  38.796 64.656 38.88 64.68 ;
    END
  END i[321]
  PIN i[322]
    DIRECTION INPUT ;
    USE SIGNAL ;
    PORT
      LAYER M4 ;
        RECT  38.796 64.752 38.88 64.776 ;
    END
  END i[322]
  PIN i[323]
    DIRECTION INPUT ;
    USE SIGNAL ;
    PORT
      LAYER M4 ;
        RECT  38.796 64.848 38.88 64.872 ;
    END
  END i[323]
  PIN i[324]
    DIRECTION INPUT ;
    USE SIGNAL ;
    PORT
      LAYER M4 ;
        RECT  38.796 64.944 38.88 64.968 ;
    END
  END i[324]
  PIN i[325]
    DIRECTION INPUT ;
    USE SIGNAL ;
    PORT
      LAYER M4 ;
        RECT  38.796 65.04 38.88 65.064 ;
    END
  END i[325]
  PIN i[326]
    DIRECTION INPUT ;
    USE SIGNAL ;
    PORT
      LAYER M4 ;
        RECT  38.796 65.136 38.88 65.16 ;
    END
  END i[326]
  PIN i[327]
    DIRECTION INPUT ;
    USE SIGNAL ;
    PORT
      LAYER M4 ;
        RECT  38.796 65.232 38.88 65.256 ;
    END
  END i[327]
  PIN i[328]
    DIRECTION INPUT ;
    USE SIGNAL ;
    PORT
      LAYER M4 ;
        RECT  38.796 65.328 38.88 65.352 ;
    END
  END i[328]
  PIN i[329]
    DIRECTION INPUT ;
    USE SIGNAL ;
    PORT
      LAYER M4 ;
        RECT  38.796 65.424 38.88 65.448 ;
    END
  END i[329]
  PIN i[32]
    DIRECTION INPUT ;
    USE SIGNAL ;
    PORT
      LAYER M4 ;
        RECT  38.796 39.216 38.88 39.24 ;
    END
  END i[32]
  PIN i[330]
    DIRECTION INPUT ;
    USE SIGNAL ;
    PORT
      LAYER M4 ;
        RECT  38.796 65.52 38.88 65.544 ;
    END
  END i[330]
  PIN i[331]
    DIRECTION INPUT ;
    USE SIGNAL ;
    PORT
      LAYER M4 ;
        RECT  38.796 65.616 38.88 65.64 ;
    END
  END i[331]
  PIN i[332]
    DIRECTION INPUT ;
    USE SIGNAL ;
    PORT
      LAYER M4 ;
        RECT  38.796 65.712 38.88 65.736 ;
    END
  END i[332]
  PIN i[333]
    DIRECTION INPUT ;
    USE SIGNAL ;
    PORT
      LAYER M4 ;
        RECT  38.796 65.808 38.88 65.832 ;
    END
  END i[333]
  PIN i[334]
    DIRECTION INPUT ;
    USE SIGNAL ;
    PORT
      LAYER M4 ;
        RECT  38.796 65.904 38.88 65.928 ;
    END
  END i[334]
  PIN i[335]
    DIRECTION INPUT ;
    USE SIGNAL ;
    PORT
      LAYER M4 ;
        RECT  38.796 66 38.88 66.024 ;
    END
  END i[335]
  PIN i[336]
    DIRECTION INPUT ;
    USE SIGNAL ;
    PORT
      LAYER M4 ;
        RECT  38.796 66.096 38.88 66.12 ;
    END
  END i[336]
  PIN i[337]
    DIRECTION INPUT ;
    USE SIGNAL ;
    PORT
      LAYER M4 ;
        RECT  38.796 66.192 38.88 66.216 ;
    END
  END i[337]
  PIN i[338]
    DIRECTION INPUT ;
    USE SIGNAL ;
    PORT
      LAYER M4 ;
        RECT  38.796 66.288 38.88 66.312 ;
    END
  END i[338]
  PIN i[339]
    DIRECTION INPUT ;
    USE SIGNAL ;
    PORT
      LAYER M4 ;
        RECT  38.796 66.384 38.88 66.408 ;
    END
  END i[339]
  PIN i[33]
    DIRECTION INPUT ;
    USE SIGNAL ;
    PORT
      LAYER M4 ;
        RECT  38.796 39.312 38.88 39.336 ;
    END
  END i[33]
  PIN i[340]
    DIRECTION INPUT ;
    USE SIGNAL ;
    PORT
      LAYER M4 ;
        RECT  38.796 66.48 38.88 66.504 ;
    END
  END i[340]
  PIN i[341]
    DIRECTION INPUT ;
    USE SIGNAL ;
    PORT
      LAYER M4 ;
        RECT  38.796 66.576 38.88 66.6 ;
    END
  END i[341]
  PIN i[342]
    DIRECTION INPUT ;
    USE SIGNAL ;
    PORT
      LAYER M4 ;
        RECT  38.796 66.672 38.88 66.696 ;
    END
  END i[342]
  PIN i[343]
    DIRECTION INPUT ;
    USE SIGNAL ;
    PORT
      LAYER M4 ;
        RECT  38.796 66.768 38.88 66.792 ;
    END
  END i[343]
  PIN i[344]
    DIRECTION INPUT ;
    USE SIGNAL ;
    PORT
      LAYER M4 ;
        RECT  38.796 66.864 38.88 66.888 ;
    END
  END i[344]
  PIN i[345]
    DIRECTION INPUT ;
    USE SIGNAL ;
    PORT
      LAYER M4 ;
        RECT  38.796 66.96 38.88 66.984 ;
    END
  END i[345]
  PIN i[346]
    DIRECTION INPUT ;
    USE SIGNAL ;
    PORT
      LAYER M4 ;
        RECT  38.796 67.056 38.88 67.08 ;
    END
  END i[346]
  PIN i[347]
    DIRECTION INPUT ;
    USE SIGNAL ;
    PORT
      LAYER M4 ;
        RECT  38.796 67.152 38.88 67.176 ;
    END
  END i[347]
  PIN i[348]
    DIRECTION INPUT ;
    USE SIGNAL ;
    PORT
      LAYER M4 ;
        RECT  38.796 67.248 38.88 67.272 ;
    END
  END i[348]
  PIN i[349]
    DIRECTION INPUT ;
    USE SIGNAL ;
    PORT
      LAYER M4 ;
        RECT  38.796 67.344 38.88 67.368 ;
    END
  END i[349]
  PIN i[34]
    DIRECTION INPUT ;
    USE SIGNAL ;
    PORT
      LAYER M4 ;
        RECT  38.796 39.408 38.88 39.432 ;
    END
  END i[34]
  PIN i[350]
    DIRECTION INPUT ;
    USE SIGNAL ;
    PORT
      LAYER M4 ;
        RECT  38.796 67.44 38.88 67.464 ;
    END
  END i[350]
  PIN i[351]
    DIRECTION INPUT ;
    USE SIGNAL ;
    PORT
      LAYER M4 ;
        RECT  38.796 83.664 38.88 83.688 ;
    END
  END i[351]
  PIN i[352]
    DIRECTION INPUT ;
    USE SIGNAL ;
    PORT
      LAYER M4 ;
        RECT  38.796 83.76 38.88 83.784 ;
    END
  END i[352]
  PIN i[353]
    DIRECTION INPUT ;
    USE SIGNAL ;
    PORT
      LAYER M4 ;
        RECT  38.796 83.856 38.88 83.88 ;
    END
  END i[353]
  PIN i[354]
    DIRECTION INPUT ;
    USE SIGNAL ;
    PORT
      LAYER M4 ;
        RECT  38.796 83.952 38.88 83.976 ;
    END
  END i[354]
  PIN i[355]
    DIRECTION INPUT ;
    USE SIGNAL ;
    PORT
      LAYER M4 ;
        RECT  38.796 84.048 38.88 84.072 ;
    END
  END i[355]
  PIN i[356]
    DIRECTION INPUT ;
    USE SIGNAL ;
    PORT
      LAYER M4 ;
        RECT  38.796 84.144 38.88 84.168 ;
    END
  END i[356]
  PIN i[357]
    DIRECTION INPUT ;
    USE SIGNAL ;
    PORT
      LAYER M4 ;
        RECT  38.796 84.24 38.88 84.264 ;
    END
  END i[357]
  PIN i[358]
    DIRECTION INPUT ;
    USE SIGNAL ;
    PORT
      LAYER M4 ;
        RECT  38.796 84.336 38.88 84.36 ;
    END
  END i[358]
  PIN i[359]
    DIRECTION INPUT ;
    USE SIGNAL ;
    PORT
      LAYER M4 ;
        RECT  38.796 84.432 38.88 84.456 ;
    END
  END i[359]
  PIN i[35]
    DIRECTION INPUT ;
    USE SIGNAL ;
    PORT
      LAYER M4 ;
        RECT  38.796 39.504 38.88 39.528 ;
    END
  END i[35]
  PIN i[360]
    DIRECTION INPUT ;
    USE SIGNAL ;
    PORT
      LAYER M4 ;
        RECT  38.796 84.528 38.88 84.552 ;
    END
  END i[360]
  PIN i[361]
    DIRECTION INPUT ;
    USE SIGNAL ;
    PORT
      LAYER M4 ;
        RECT  38.796 84.624 38.88 84.648 ;
    END
  END i[361]
  PIN i[362]
    DIRECTION INPUT ;
    USE SIGNAL ;
    PORT
      LAYER M4 ;
        RECT  38.796 84.72 38.88 84.744 ;
    END
  END i[362]
  PIN i[363]
    DIRECTION INPUT ;
    USE SIGNAL ;
    PORT
      LAYER M4 ;
        RECT  38.796 84.816 38.88 84.84 ;
    END
  END i[363]
  PIN i[364]
    DIRECTION INPUT ;
    USE SIGNAL ;
    PORT
      LAYER M4 ;
        RECT  38.796 84.912 38.88 84.936 ;
    END
  END i[364]
  PIN i[365]
    DIRECTION INPUT ;
    USE SIGNAL ;
    PORT
      LAYER M4 ;
        RECT  38.796 85.008 38.88 85.032 ;
    END
  END i[365]
  PIN i[366]
    DIRECTION INPUT ;
    USE SIGNAL ;
    PORT
      LAYER M4 ;
        RECT  38.796 85.104 38.88 85.128 ;
    END
  END i[366]
  PIN i[367]
    DIRECTION INPUT ;
    USE SIGNAL ;
    PORT
      LAYER M4 ;
        RECT  38.796 85.2 38.88 85.224 ;
    END
  END i[367]
  PIN i[368]
    DIRECTION INPUT ;
    USE SIGNAL ;
    PORT
      LAYER M4 ;
        RECT  38.796 85.296 38.88 85.32 ;
    END
  END i[368]
  PIN i[369]
    DIRECTION INPUT ;
    USE SIGNAL ;
    PORT
      LAYER M4 ;
        RECT  38.796 85.392 38.88 85.416 ;
    END
  END i[369]
  PIN i[36]
    DIRECTION INPUT ;
    USE SIGNAL ;
    PORT
      LAYER M4 ;
        RECT  38.796 39.6 38.88 39.624 ;
    END
  END i[36]
  PIN i[370]
    DIRECTION INPUT ;
    USE SIGNAL ;
    PORT
      LAYER M4 ;
        RECT  38.796 85.488 38.88 85.512 ;
    END
  END i[370]
  PIN i[371]
    DIRECTION INPUT ;
    USE SIGNAL ;
    PORT
      LAYER M4 ;
        RECT  38.796 85.584 38.88 85.608 ;
    END
  END i[371]
  PIN i[372]
    DIRECTION INPUT ;
    USE SIGNAL ;
    PORT
      LAYER M4 ;
        RECT  38.796 85.68 38.88 85.704 ;
    END
  END i[372]
  PIN i[373]
    DIRECTION INPUT ;
    USE SIGNAL ;
    PORT
      LAYER M4 ;
        RECT  38.796 85.776 38.88 85.8 ;
    END
  END i[373]
  PIN i[374]
    DIRECTION INPUT ;
    USE SIGNAL ;
    PORT
      LAYER M4 ;
        RECT  38.796 85.872 38.88 85.896 ;
    END
  END i[374]
  PIN i[375]
    DIRECTION INPUT ;
    USE SIGNAL ;
    PORT
      LAYER M4 ;
        RECT  38.796 85.968 38.88 85.992 ;
    END
  END i[375]
  PIN i[376]
    DIRECTION INPUT ;
    USE SIGNAL ;
    PORT
      LAYER M4 ;
        RECT  38.796 86.064 38.88 86.088 ;
    END
  END i[376]
  PIN i[377]
    DIRECTION INPUT ;
    USE SIGNAL ;
    PORT
      LAYER M4 ;
        RECT  38.796 86.16 38.88 86.184 ;
    END
  END i[377]
  PIN i[378]
    DIRECTION INPUT ;
    USE SIGNAL ;
    PORT
      LAYER M4 ;
        RECT  38.796 86.256 38.88 86.28 ;
    END
  END i[378]
  PIN i[379]
    DIRECTION INPUT ;
    USE SIGNAL ;
    PORT
      LAYER M4 ;
        RECT  38.796 86.352 38.88 86.376 ;
    END
  END i[379]
  PIN i[37]
    DIRECTION INPUT ;
    USE SIGNAL ;
    PORT
      LAYER M4 ;
        RECT  38.796 39.696 38.88 39.72 ;
    END
  END i[37]
  PIN i[380]
    DIRECTION INPUT ;
    USE SIGNAL ;
    PORT
      LAYER M4 ;
        RECT  38.796 86.448 38.88 86.472 ;
    END
  END i[380]
  PIN i[381]
    DIRECTION INPUT ;
    USE SIGNAL ;
    PORT
      LAYER M4 ;
        RECT  38.796 86.544 38.88 86.568 ;
    END
  END i[381]
  PIN i[382]
    DIRECTION INPUT ;
    USE SIGNAL ;
    PORT
      LAYER M4 ;
        RECT  38.796 86.64 38.88 86.664 ;
    END
  END i[382]
  PIN i[383]
    DIRECTION INPUT ;
    USE SIGNAL ;
    PORT
      LAYER M4 ;
        RECT  38.796 80.592 38.88 80.616 ;
    END
  END i[383]
  PIN i[384]
    DIRECTION INPUT ;
    USE SIGNAL ;
    PORT
      LAYER M4 ;
        RECT  38.796 80.688 38.88 80.712 ;
    END
  END i[384]
  PIN i[385]
    DIRECTION INPUT ;
    USE SIGNAL ;
    PORT
      LAYER M4 ;
        RECT  38.796 80.784 38.88 80.808 ;
    END
  END i[385]
  PIN i[386]
    DIRECTION INPUT ;
    USE SIGNAL ;
    PORT
      LAYER M4 ;
        RECT  38.796 80.88 38.88 80.904 ;
    END
  END i[386]
  PIN i[387]
    DIRECTION INPUT ;
    USE SIGNAL ;
    PORT
      LAYER M4 ;
        RECT  38.796 80.976 38.88 81 ;
    END
  END i[387]
  PIN i[388]
    DIRECTION INPUT ;
    USE SIGNAL ;
    PORT
      LAYER M4 ;
        RECT  38.796 81.072 38.88 81.096 ;
    END
  END i[388]
  PIN i[389]
    DIRECTION INPUT ;
    USE SIGNAL ;
    PORT
      LAYER M4 ;
        RECT  38.796 81.168 38.88 81.192 ;
    END
  END i[389]
  PIN i[38]
    DIRECTION INPUT ;
    USE SIGNAL ;
    PORT
      LAYER M4 ;
        RECT  38.796 39.792 38.88 39.816 ;
    END
  END i[38]
  PIN i[390]
    DIRECTION INPUT ;
    USE SIGNAL ;
    PORT
      LAYER M4 ;
        RECT  38.796 81.264 38.88 81.288 ;
    END
  END i[390]
  PIN i[391]
    DIRECTION INPUT ;
    USE SIGNAL ;
    PORT
      LAYER M4 ;
        RECT  38.796 81.36 38.88 81.384 ;
    END
  END i[391]
  PIN i[392]
    DIRECTION INPUT ;
    USE SIGNAL ;
    PORT
      LAYER M4 ;
        RECT  38.796 81.456 38.88 81.48 ;
    END
  END i[392]
  PIN i[393]
    DIRECTION INPUT ;
    USE SIGNAL ;
    PORT
      LAYER M4 ;
        RECT  38.796 81.552 38.88 81.576 ;
    END
  END i[393]
  PIN i[394]
    DIRECTION INPUT ;
    USE SIGNAL ;
    PORT
      LAYER M4 ;
        RECT  38.796 81.648 38.88 81.672 ;
    END
  END i[394]
  PIN i[395]
    DIRECTION INPUT ;
    USE SIGNAL ;
    PORT
      LAYER M4 ;
        RECT  38.796 81.744 38.88 81.768 ;
    END
  END i[395]
  PIN i[396]
    DIRECTION INPUT ;
    USE SIGNAL ;
    PORT
      LAYER M4 ;
        RECT  38.796 81.84 38.88 81.864 ;
    END
  END i[396]
  PIN i[397]
    DIRECTION INPUT ;
    USE SIGNAL ;
    PORT
      LAYER M4 ;
        RECT  38.796 81.936 38.88 81.96 ;
    END
  END i[397]
  PIN i[398]
    DIRECTION INPUT ;
    USE SIGNAL ;
    PORT
      LAYER M4 ;
        RECT  38.796 82.032 38.88 82.056 ;
    END
  END i[398]
  PIN i[399]
    DIRECTION INPUT ;
    USE SIGNAL ;
    PORT
      LAYER M4 ;
        RECT  38.796 82.128 38.88 82.152 ;
    END
  END i[399]
  PIN i[39]
    DIRECTION INPUT ;
    USE SIGNAL ;
    PORT
      LAYER M4 ;
        RECT  38.796 39.888 38.88 39.912 ;
    END
  END i[39]
  PIN i[3]
    DIRECTION INPUT ;
    USE SIGNAL ;
    PORT
      LAYER M4 ;
        RECT  38.796 51.792 38.88 51.816 ;
    END
  END i[3]
  PIN i[400]
    DIRECTION INPUT ;
    USE SIGNAL ;
    PORT
      LAYER M4 ;
        RECT  38.796 82.224 38.88 82.248 ;
    END
  END i[400]
  PIN i[401]
    DIRECTION INPUT ;
    USE SIGNAL ;
    PORT
      LAYER M4 ;
        RECT  38.796 82.32 38.88 82.344 ;
    END
  END i[401]
  PIN i[402]
    DIRECTION INPUT ;
    USE SIGNAL ;
    PORT
      LAYER M4 ;
        RECT  38.796 82.416 38.88 82.44 ;
    END
  END i[402]
  PIN i[403]
    DIRECTION INPUT ;
    USE SIGNAL ;
    PORT
      LAYER M4 ;
        RECT  38.796 82.512 38.88 82.536 ;
    END
  END i[403]
  PIN i[404]
    DIRECTION INPUT ;
    USE SIGNAL ;
    PORT
      LAYER M4 ;
        RECT  38.796 82.608 38.88 82.632 ;
    END
  END i[404]
  PIN i[405]
    DIRECTION INPUT ;
    USE SIGNAL ;
    PORT
      LAYER M4 ;
        RECT  38.796 82.704 38.88 82.728 ;
    END
  END i[405]
  PIN i[406]
    DIRECTION INPUT ;
    USE SIGNAL ;
    PORT
      LAYER M4 ;
        RECT  38.796 82.8 38.88 82.824 ;
    END
  END i[406]
  PIN i[407]
    DIRECTION INPUT ;
    USE SIGNAL ;
    PORT
      LAYER M4 ;
        RECT  38.796 82.896 38.88 82.92 ;
    END
  END i[407]
  PIN i[408]
    DIRECTION INPUT ;
    USE SIGNAL ;
    PORT
      LAYER M4 ;
        RECT  38.796 82.992 38.88 83.016 ;
    END
  END i[408]
  PIN i[409]
    DIRECTION INPUT ;
    USE SIGNAL ;
    PORT
      LAYER M4 ;
        RECT  38.796 83.088 38.88 83.112 ;
    END
  END i[409]
  PIN i[40]
    DIRECTION INPUT ;
    USE SIGNAL ;
    PORT
      LAYER M4 ;
        RECT  38.796 39.984 38.88 40.008 ;
    END
  END i[40]
  PIN i[410]
    DIRECTION INPUT ;
    USE SIGNAL ;
    PORT
      LAYER M4 ;
        RECT  38.796 83.184 38.88 83.208 ;
    END
  END i[410]
  PIN i[411]
    DIRECTION INPUT ;
    USE SIGNAL ;
    PORT
      LAYER M4 ;
        RECT  38.796 83.28 38.88 83.304 ;
    END
  END i[411]
  PIN i[412]
    DIRECTION INPUT ;
    USE SIGNAL ;
    PORT
      LAYER M4 ;
        RECT  38.796 83.376 38.88 83.4 ;
    END
  END i[412]
  PIN i[413]
    DIRECTION INPUT ;
    USE SIGNAL ;
    PORT
      LAYER M4 ;
        RECT  38.796 83.472 38.88 83.496 ;
    END
  END i[413]
  PIN i[414]
    DIRECTION INPUT ;
    USE SIGNAL ;
    PORT
      LAYER M4 ;
        RECT  38.796 83.568 38.88 83.592 ;
    END
  END i[414]
  PIN i[415]
    DIRECTION INPUT ;
    USE SIGNAL ;
    PORT
      LAYER M4 ;
        RECT  38.796 86.736 38.88 86.76 ;
    END
  END i[415]
  PIN i[416]
    DIRECTION INPUT ;
    USE SIGNAL ;
    PORT
      LAYER M4 ;
        RECT  38.796 86.832 38.88 86.856 ;
    END
  END i[416]
  PIN i[417]
    DIRECTION INPUT ;
    USE SIGNAL ;
    PORT
      LAYER M4 ;
        RECT  38.796 86.928 38.88 86.952 ;
    END
  END i[417]
  PIN i[418]
    DIRECTION INPUT ;
    USE SIGNAL ;
    PORT
      LAYER M4 ;
        RECT  38.796 87.024 38.88 87.048 ;
    END
  END i[418]
  PIN i[419]
    DIRECTION INPUT ;
    USE SIGNAL ;
    PORT
      LAYER M4 ;
        RECT  38.796 87.12 38.88 87.144 ;
    END
  END i[419]
  PIN i[41]
    DIRECTION INPUT ;
    USE SIGNAL ;
    PORT
      LAYER M4 ;
        RECT  38.796 40.08 38.88 40.104 ;
    END
  END i[41]
  PIN i[420]
    DIRECTION INPUT ;
    USE SIGNAL ;
    PORT
      LAYER M4 ;
        RECT  38.796 87.216 38.88 87.24 ;
    END
  END i[420]
  PIN i[421]
    DIRECTION INPUT ;
    USE SIGNAL ;
    PORT
      LAYER M4 ;
        RECT  38.796 87.312 38.88 87.336 ;
    END
  END i[421]
  PIN i[422]
    DIRECTION INPUT ;
    USE SIGNAL ;
    PORT
      LAYER M4 ;
        RECT  38.796 87.408 38.88 87.432 ;
    END
  END i[422]
  PIN i[423]
    DIRECTION INPUT ;
    USE SIGNAL ;
    PORT
      LAYER M4 ;
        RECT  38.796 87.504 38.88 87.528 ;
    END
  END i[423]
  PIN i[424]
    DIRECTION INPUT ;
    USE SIGNAL ;
    PORT
      LAYER M4 ;
        RECT  38.796 87.6 38.88 87.624 ;
    END
  END i[424]
  PIN i[425]
    DIRECTION INPUT ;
    USE SIGNAL ;
    PORT
      LAYER M4 ;
        RECT  38.796 87.696 38.88 87.72 ;
    END
  END i[425]
  PIN i[426]
    DIRECTION INPUT ;
    USE SIGNAL ;
    PORT
      LAYER M4 ;
        RECT  38.796 87.792 38.88 87.816 ;
    END
  END i[426]
  PIN i[427]
    DIRECTION INPUT ;
    USE SIGNAL ;
    PORT
      LAYER M4 ;
        RECT  38.796 87.888 38.88 87.912 ;
    END
  END i[427]
  PIN i[428]
    DIRECTION INPUT ;
    USE SIGNAL ;
    PORT
      LAYER M4 ;
        RECT  38.796 87.984 38.88 88.008 ;
    END
  END i[428]
  PIN i[429]
    DIRECTION INPUT ;
    USE SIGNAL ;
    PORT
      LAYER M4 ;
        RECT  38.796 88.08 38.88 88.104 ;
    END
  END i[429]
  PIN i[42]
    DIRECTION INPUT ;
    USE SIGNAL ;
    PORT
      LAYER M4 ;
        RECT  38.796 40.176 38.88 40.2 ;
    END
  END i[42]
  PIN i[430]
    DIRECTION INPUT ;
    USE SIGNAL ;
    PORT
      LAYER M4 ;
        RECT  38.796 88.176 38.88 88.2 ;
    END
  END i[430]
  PIN i[431]
    DIRECTION INPUT ;
    USE SIGNAL ;
    PORT
      LAYER M4 ;
        RECT  38.796 88.272 38.88 88.296 ;
    END
  END i[431]
  PIN i[432]
    DIRECTION INPUT ;
    USE SIGNAL ;
    PORT
      LAYER M4 ;
        RECT  38.796 88.368 38.88 88.392 ;
    END
  END i[432]
  PIN i[433]
    DIRECTION INPUT ;
    USE SIGNAL ;
    PORT
      LAYER M4 ;
        RECT  38.796 88.464 38.88 88.488 ;
    END
  END i[433]
  PIN i[434]
    DIRECTION INPUT ;
    USE SIGNAL ;
    PORT
      LAYER M4 ;
        RECT  38.796 88.56 38.88 88.584 ;
    END
  END i[434]
  PIN i[435]
    DIRECTION INPUT ;
    USE SIGNAL ;
    PORT
      LAYER M4 ;
        RECT  38.796 88.656 38.88 88.68 ;
    END
  END i[435]
  PIN i[436]
    DIRECTION INPUT ;
    USE SIGNAL ;
    PORT
      LAYER M4 ;
        RECT  38.796 88.752 38.88 88.776 ;
    END
  END i[436]
  PIN i[437]
    DIRECTION INPUT ;
    USE SIGNAL ;
    PORT
      LAYER M4 ;
        RECT  38.796 88.848 38.88 88.872 ;
    END
  END i[437]
  PIN i[438]
    DIRECTION INPUT ;
    USE SIGNAL ;
    PORT
      LAYER M4 ;
        RECT  38.796 88.944 38.88 88.968 ;
    END
  END i[438]
  PIN i[439]
    DIRECTION INPUT ;
    USE SIGNAL ;
    PORT
      LAYER M4 ;
        RECT  38.796 89.04 38.88 89.064 ;
    END
  END i[439]
  PIN i[43]
    DIRECTION INPUT ;
    USE SIGNAL ;
    PORT
      LAYER M4 ;
        RECT  38.796 40.272 38.88 40.296 ;
    END
  END i[43]
  PIN i[440]
    DIRECTION INPUT ;
    USE SIGNAL ;
    PORT
      LAYER M4 ;
        RECT  38.796 89.136 38.88 89.16 ;
    END
  END i[440]
  PIN i[441]
    DIRECTION INPUT ;
    USE SIGNAL ;
    PORT
      LAYER M4 ;
        RECT  38.796 89.232 38.88 89.256 ;
    END
  END i[441]
  PIN i[442]
    DIRECTION INPUT ;
    USE SIGNAL ;
    PORT
      LAYER M4 ;
        RECT  38.796 89.328 38.88 89.352 ;
    END
  END i[442]
  PIN i[443]
    DIRECTION INPUT ;
    USE SIGNAL ;
    PORT
      LAYER M4 ;
        RECT  38.796 89.424 38.88 89.448 ;
    END
  END i[443]
  PIN i[444]
    DIRECTION INPUT ;
    USE SIGNAL ;
    PORT
      LAYER M4 ;
        RECT  38.796 89.52 38.88 89.544 ;
    END
  END i[444]
  PIN i[445]
    DIRECTION INPUT ;
    USE SIGNAL ;
    PORT
      LAYER M4 ;
        RECT  38.796 89.616 38.88 89.64 ;
    END
  END i[445]
  PIN i[446]
    DIRECTION INPUT ;
    USE SIGNAL ;
    PORT
      LAYER M4 ;
        RECT  38.796 89.712 38.88 89.736 ;
    END
  END i[446]
  PIN i[447]
    DIRECTION INPUT ;
    USE SIGNAL ;
    PORT
      LAYER M4 ;
        RECT  38.796 77.52 38.88 77.544 ;
    END
  END i[447]
  PIN i[448]
    DIRECTION INPUT ;
    USE SIGNAL ;
    PORT
      LAYER M4 ;
        RECT  38.796 77.616 38.88 77.64 ;
    END
  END i[448]
  PIN i[449]
    DIRECTION INPUT ;
    USE SIGNAL ;
    PORT
      LAYER M4 ;
        RECT  38.796 77.712 38.88 77.736 ;
    END
  END i[449]
  PIN i[44]
    DIRECTION INPUT ;
    USE SIGNAL ;
    PORT
      LAYER M4 ;
        RECT  38.796 40.368 38.88 40.392 ;
    END
  END i[44]
  PIN i[450]
    DIRECTION INPUT ;
    USE SIGNAL ;
    PORT
      LAYER M4 ;
        RECT  38.796 77.808 38.88 77.832 ;
    END
  END i[450]
  PIN i[451]
    DIRECTION INPUT ;
    USE SIGNAL ;
    PORT
      LAYER M4 ;
        RECT  38.796 77.904 38.88 77.928 ;
    END
  END i[451]
  PIN i[452]
    DIRECTION INPUT ;
    USE SIGNAL ;
    PORT
      LAYER M4 ;
        RECT  38.796 78 38.88 78.024 ;
    END
  END i[452]
  PIN i[453]
    DIRECTION INPUT ;
    USE SIGNAL ;
    PORT
      LAYER M4 ;
        RECT  38.796 78.096 38.88 78.12 ;
    END
  END i[453]
  PIN i[454]
    DIRECTION INPUT ;
    USE SIGNAL ;
    PORT
      LAYER M4 ;
        RECT  38.796 78.192 38.88 78.216 ;
    END
  END i[454]
  PIN i[455]
    DIRECTION INPUT ;
    USE SIGNAL ;
    PORT
      LAYER M4 ;
        RECT  38.796 78.288 38.88 78.312 ;
    END
  END i[455]
  PIN i[456]
    DIRECTION INPUT ;
    USE SIGNAL ;
    PORT
      LAYER M4 ;
        RECT  38.796 78.384 38.88 78.408 ;
    END
  END i[456]
  PIN i[457]
    DIRECTION INPUT ;
    USE SIGNAL ;
    PORT
      LAYER M4 ;
        RECT  38.796 78.48 38.88 78.504 ;
    END
  END i[457]
  PIN i[458]
    DIRECTION INPUT ;
    USE SIGNAL ;
    PORT
      LAYER M4 ;
        RECT  38.796 78.576 38.88 78.6 ;
    END
  END i[458]
  PIN i[459]
    DIRECTION INPUT ;
    USE SIGNAL ;
    PORT
      LAYER M4 ;
        RECT  38.796 78.672 38.88 78.696 ;
    END
  END i[459]
  PIN i[45]
    DIRECTION INPUT ;
    USE SIGNAL ;
    PORT
      LAYER M4 ;
        RECT  38.796 40.464 38.88 40.488 ;
    END
  END i[45]
  PIN i[460]
    DIRECTION INPUT ;
    USE SIGNAL ;
    PORT
      LAYER M4 ;
        RECT  38.796 78.768 38.88 78.792 ;
    END
  END i[460]
  PIN i[461]
    DIRECTION INPUT ;
    USE SIGNAL ;
    PORT
      LAYER M4 ;
        RECT  38.796 78.864 38.88 78.888 ;
    END
  END i[461]
  PIN i[462]
    DIRECTION INPUT ;
    USE SIGNAL ;
    PORT
      LAYER M4 ;
        RECT  38.796 78.96 38.88 78.984 ;
    END
  END i[462]
  PIN i[463]
    DIRECTION INPUT ;
    USE SIGNAL ;
    PORT
      LAYER M4 ;
        RECT  38.796 79.056 38.88 79.08 ;
    END
  END i[463]
  PIN i[464]
    DIRECTION INPUT ;
    USE SIGNAL ;
    PORT
      LAYER M4 ;
        RECT  38.796 79.152 38.88 79.176 ;
    END
  END i[464]
  PIN i[465]
    DIRECTION INPUT ;
    USE SIGNAL ;
    PORT
      LAYER M4 ;
        RECT  38.796 79.248 38.88 79.272 ;
    END
  END i[465]
  PIN i[466]
    DIRECTION INPUT ;
    USE SIGNAL ;
    PORT
      LAYER M4 ;
        RECT  38.796 79.344 38.88 79.368 ;
    END
  END i[466]
  PIN i[467]
    DIRECTION INPUT ;
    USE SIGNAL ;
    PORT
      LAYER M4 ;
        RECT  38.796 79.44 38.88 79.464 ;
    END
  END i[467]
  PIN i[468]
    DIRECTION INPUT ;
    USE SIGNAL ;
    PORT
      LAYER M4 ;
        RECT  38.796 79.536 38.88 79.56 ;
    END
  END i[468]
  PIN i[469]
    DIRECTION INPUT ;
    USE SIGNAL ;
    PORT
      LAYER M4 ;
        RECT  38.796 79.632 38.88 79.656 ;
    END
  END i[469]
  PIN i[46]
    DIRECTION INPUT ;
    USE SIGNAL ;
    PORT
      LAYER M4 ;
        RECT  38.796 40.56 38.88 40.584 ;
    END
  END i[46]
  PIN i[470]
    DIRECTION INPUT ;
    USE SIGNAL ;
    PORT
      LAYER M4 ;
        RECT  38.796 79.728 38.88 79.752 ;
    END
  END i[470]
  PIN i[471]
    DIRECTION INPUT ;
    USE SIGNAL ;
    PORT
      LAYER M4 ;
        RECT  38.796 79.824 38.88 79.848 ;
    END
  END i[471]
  PIN i[472]
    DIRECTION INPUT ;
    USE SIGNAL ;
    PORT
      LAYER M4 ;
        RECT  38.796 79.92 38.88 79.944 ;
    END
  END i[472]
  PIN i[473]
    DIRECTION INPUT ;
    USE SIGNAL ;
    PORT
      LAYER M4 ;
        RECT  38.796 80.016 38.88 80.04 ;
    END
  END i[473]
  PIN i[474]
    DIRECTION INPUT ;
    USE SIGNAL ;
    PORT
      LAYER M4 ;
        RECT  38.796 80.112 38.88 80.136 ;
    END
  END i[474]
  PIN i[475]
    DIRECTION INPUT ;
    USE SIGNAL ;
    PORT
      LAYER M4 ;
        RECT  38.796 80.208 38.88 80.232 ;
    END
  END i[475]
  PIN i[476]
    DIRECTION INPUT ;
    USE SIGNAL ;
    PORT
      LAYER M4 ;
        RECT  38.796 80.304 38.88 80.328 ;
    END
  END i[476]
  PIN i[477]
    DIRECTION INPUT ;
    USE SIGNAL ;
    PORT
      LAYER M4 ;
        RECT  38.796 80.4 38.88 80.424 ;
    END
  END i[477]
  PIN i[478]
    DIRECTION INPUT ;
    USE SIGNAL ;
    PORT
      LAYER M4 ;
        RECT  38.796 80.496 38.88 80.52 ;
    END
  END i[478]
  PIN i[479]
    DIRECTION INPUT ;
    USE SIGNAL ;
    PORT
      LAYER M4 ;
        RECT  38.796 58.32 38.88 58.344 ;
    END
  END i[479]
  PIN i[47]
    DIRECTION INPUT ;
    USE SIGNAL ;
    PORT
      LAYER M4 ;
        RECT  38.796 40.656 38.88 40.68 ;
    END
  END i[47]
  PIN i[480]
    DIRECTION INPUT ;
    USE SIGNAL ;
    PORT
      LAYER M4 ;
        RECT  38.796 58.416 38.88 58.44 ;
    END
  END i[480]
  PIN i[481]
    DIRECTION INPUT ;
    USE SIGNAL ;
    PORT
      LAYER M4 ;
        RECT  38.796 58.512 38.88 58.536 ;
    END
  END i[481]
  PIN i[482]
    DIRECTION INPUT ;
    USE SIGNAL ;
    PORT
      LAYER M4 ;
        RECT  38.796 58.608 38.88 58.632 ;
    END
  END i[482]
  PIN i[483]
    DIRECTION INPUT ;
    USE SIGNAL ;
    PORT
      LAYER M4 ;
        RECT  38.796 58.704 38.88 58.728 ;
    END
  END i[483]
  PIN i[484]
    DIRECTION INPUT ;
    USE SIGNAL ;
    PORT
      LAYER M4 ;
        RECT  38.796 58.8 38.88 58.824 ;
    END
  END i[484]
  PIN i[485]
    DIRECTION INPUT ;
    USE SIGNAL ;
    PORT
      LAYER M4 ;
        RECT  38.796 58.896 38.88 58.92 ;
    END
  END i[485]
  PIN i[486]
    DIRECTION INPUT ;
    USE SIGNAL ;
    PORT
      LAYER M4 ;
        RECT  38.796 58.992 38.88 59.016 ;
    END
  END i[486]
  PIN i[487]
    DIRECTION INPUT ;
    USE SIGNAL ;
    PORT
      LAYER M4 ;
        RECT  38.796 59.088 38.88 59.112 ;
    END
  END i[487]
  PIN i[488]
    DIRECTION INPUT ;
    USE SIGNAL ;
    PORT
      LAYER M4 ;
        RECT  38.796 59.184 38.88 59.208 ;
    END
  END i[488]
  PIN i[489]
    DIRECTION INPUT ;
    USE SIGNAL ;
    PORT
      LAYER M4 ;
        RECT  38.796 59.28 38.88 59.304 ;
    END
  END i[489]
  PIN i[48]
    DIRECTION INPUT ;
    USE SIGNAL ;
    PORT
      LAYER M4 ;
        RECT  38.796 40.752 38.88 40.776 ;
    END
  END i[48]
  PIN i[490]
    DIRECTION INPUT ;
    USE SIGNAL ;
    PORT
      LAYER M4 ;
        RECT  38.796 59.376 38.88 59.4 ;
    END
  END i[490]
  PIN i[491]
    DIRECTION INPUT ;
    USE SIGNAL ;
    PORT
      LAYER M4 ;
        RECT  38.796 59.472 38.88 59.496 ;
    END
  END i[491]
  PIN i[492]
    DIRECTION INPUT ;
    USE SIGNAL ;
    PORT
      LAYER M4 ;
        RECT  38.796 59.568 38.88 59.592 ;
    END
  END i[492]
  PIN i[493]
    DIRECTION INPUT ;
    USE SIGNAL ;
    PORT
      LAYER M4 ;
        RECT  38.796 59.664 38.88 59.688 ;
    END
  END i[493]
  PIN i[494]
    DIRECTION INPUT ;
    USE SIGNAL ;
    PORT
      LAYER M4 ;
        RECT  38.796 59.76 38.88 59.784 ;
    END
  END i[494]
  PIN i[495]
    DIRECTION INPUT ;
    USE SIGNAL ;
    PORT
      LAYER M4 ;
        RECT  38.796 59.856 38.88 59.88 ;
    END
  END i[495]
  PIN i[496]
    DIRECTION INPUT ;
    USE SIGNAL ;
    PORT
      LAYER M4 ;
        RECT  38.796 59.952 38.88 59.976 ;
    END
  END i[496]
  PIN i[497]
    DIRECTION INPUT ;
    USE SIGNAL ;
    PORT
      LAYER M4 ;
        RECT  38.796 60.048 38.88 60.072 ;
    END
  END i[497]
  PIN i[498]
    DIRECTION INPUT ;
    USE SIGNAL ;
    PORT
      LAYER M4 ;
        RECT  38.796 60.144 38.88 60.168 ;
    END
  END i[498]
  PIN i[499]
    DIRECTION INPUT ;
    USE SIGNAL ;
    PORT
      LAYER M4 ;
        RECT  38.796 60.24 38.88 60.264 ;
    END
  END i[499]
  PIN i[49]
    DIRECTION INPUT ;
    USE SIGNAL ;
    PORT
      LAYER M4 ;
        RECT  38.796 40.848 38.88 40.872 ;
    END
  END i[49]
  PIN i[4]
    DIRECTION INPUT ;
    USE SIGNAL ;
    PORT
      LAYER M4 ;
        RECT  38.796 51.888 38.88 51.912 ;
    END
  END i[4]
  PIN i[500]
    DIRECTION INPUT ;
    USE SIGNAL ;
    PORT
      LAYER M4 ;
        RECT  38.796 60.336 38.88 60.36 ;
    END
  END i[500]
  PIN i[501]
    DIRECTION INPUT ;
    USE SIGNAL ;
    PORT
      LAYER M4 ;
        RECT  38.796 60.432 38.88 60.456 ;
    END
  END i[501]
  PIN i[502]
    DIRECTION INPUT ;
    USE SIGNAL ;
    PORT
      LAYER M4 ;
        RECT  38.796 60.528 38.88 60.552 ;
    END
  END i[502]
  PIN i[503]
    DIRECTION INPUT ;
    USE SIGNAL ;
    PORT
      LAYER M4 ;
        RECT  38.796 60.624 38.88 60.648 ;
    END
  END i[503]
  PIN i[504]
    DIRECTION INPUT ;
    USE SIGNAL ;
    PORT
      LAYER M4 ;
        RECT  38.796 60.72 38.88 60.744 ;
    END
  END i[504]
  PIN i[505]
    DIRECTION INPUT ;
    USE SIGNAL ;
    PORT
      LAYER M4 ;
        RECT  38.796 60.816 38.88 60.84 ;
    END
  END i[505]
  PIN i[506]
    DIRECTION INPUT ;
    USE SIGNAL ;
    PORT
      LAYER M4 ;
        RECT  38.796 60.912 38.88 60.936 ;
    END
  END i[506]
  PIN i[507]
    DIRECTION INPUT ;
    USE SIGNAL ;
    PORT
      LAYER M4 ;
        RECT  38.796 61.008 38.88 61.032 ;
    END
  END i[507]
  PIN i[508]
    DIRECTION INPUT ;
    USE SIGNAL ;
    PORT
      LAYER M4 ;
        RECT  38.796 61.104 38.88 61.128 ;
    END
  END i[508]
  PIN i[509]
    DIRECTION INPUT ;
    USE SIGNAL ;
    PORT
      LAYER M4 ;
        RECT  38.796 61.2 38.88 61.224 ;
    END
  END i[509]
  PIN i[50]
    DIRECTION INPUT ;
    USE SIGNAL ;
    PORT
      LAYER M4 ;
        RECT  38.796 40.944 38.88 40.968 ;
    END
  END i[50]
  PIN i[510]
    DIRECTION INPUT ;
    USE SIGNAL ;
    PORT
      LAYER M4 ;
        RECT  38.796 61.296 38.88 61.32 ;
    END
  END i[510]
  PIN i[511]
    DIRECTION INPUT ;
    USE SIGNAL ;
    PORT
      LAYER M4 ;
        RECT  38.796 57.552 38.88 57.576 ;
    END
  END i[511]
  PIN i[51]
    DIRECTION INPUT ;
    USE SIGNAL ;
    PORT
      LAYER M4 ;
        RECT  38.796 41.04 38.88 41.064 ;
    END
  END i[51]
  PIN i[52]
    DIRECTION INPUT ;
    USE SIGNAL ;
    PORT
      LAYER M4 ;
        RECT  38.796 41.136 38.88 41.16 ;
    END
  END i[52]
  PIN i[53]
    DIRECTION INPUT ;
    USE SIGNAL ;
    PORT
      LAYER M4 ;
        RECT  38.796 41.232 38.88 41.256 ;
    END
  END i[53]
  PIN i[54]
    DIRECTION INPUT ;
    USE SIGNAL ;
    PORT
      LAYER M4 ;
        RECT  38.796 41.328 38.88 41.352 ;
    END
  END i[54]
  PIN i[55]
    DIRECTION INPUT ;
    USE SIGNAL ;
    PORT
      LAYER M4 ;
        RECT  38.796 41.424 38.88 41.448 ;
    END
  END i[55]
  PIN i[56]
    DIRECTION INPUT ;
    USE SIGNAL ;
    PORT
      LAYER M4 ;
        RECT  38.796 41.52 38.88 41.544 ;
    END
  END i[56]
  PIN i[57]
    DIRECTION INPUT ;
    USE SIGNAL ;
    PORT
      LAYER M4 ;
        RECT  38.796 41.616 38.88 41.64 ;
    END
  END i[57]
  PIN i[58]
    DIRECTION INPUT ;
    USE SIGNAL ;
    PORT
      LAYER M4 ;
        RECT  38.796 41.712 38.88 41.736 ;
    END
  END i[58]
  PIN i[59]
    DIRECTION INPUT ;
    USE SIGNAL ;
    PORT
      LAYER M4 ;
        RECT  38.796 41.808 38.88 41.832 ;
    END
  END i[59]
  PIN i[5]
    DIRECTION INPUT ;
    USE SIGNAL ;
    PORT
      LAYER M4 ;
        RECT  38.796 51.984 38.88 52.008 ;
    END
  END i[5]
  PIN i[60]
    DIRECTION INPUT ;
    USE SIGNAL ;
    PORT
      LAYER M4 ;
        RECT  38.796 41.904 38.88 41.928 ;
    END
  END i[60]
  PIN i[61]
    DIRECTION INPUT ;
    USE SIGNAL ;
    PORT
      LAYER M4 ;
        RECT  38.796 42 38.88 42.024 ;
    END
  END i[61]
  PIN i[62]
    DIRECTION INPUT ;
    USE SIGNAL ;
    PORT
      LAYER M4 ;
        RECT  38.796 42.096 38.88 42.12 ;
    END
  END i[62]
  PIN i[63]
    DIRECTION INPUT ;
    USE SIGNAL ;
    PORT
      LAYER M4 ;
        RECT  38.796 29.136 38.88 29.16 ;
    END
  END i[63]
  PIN i[64]
    DIRECTION INPUT ;
    USE SIGNAL ;
    PORT
      LAYER M4 ;
        RECT  38.796 29.232 38.88 29.256 ;
    END
  END i[64]
  PIN i[65]
    DIRECTION INPUT ;
    USE SIGNAL ;
    PORT
      LAYER M4 ;
        RECT  38.796 29.328 38.88 29.352 ;
    END
  END i[65]
  PIN i[66]
    DIRECTION INPUT ;
    USE SIGNAL ;
    PORT
      LAYER M4 ;
        RECT  38.796 29.424 38.88 29.448 ;
    END
  END i[66]
  PIN i[67]
    DIRECTION INPUT ;
    USE SIGNAL ;
    PORT
      LAYER M4 ;
        RECT  38.796 29.52 38.88 29.544 ;
    END
  END i[67]
  PIN i[68]
    DIRECTION INPUT ;
    USE SIGNAL ;
    PORT
      LAYER M4 ;
        RECT  38.796 29.616 38.88 29.64 ;
    END
  END i[68]
  PIN i[69]
    DIRECTION INPUT ;
    USE SIGNAL ;
    PORT
      LAYER M4 ;
        RECT  38.796 29.712 38.88 29.736 ;
    END
  END i[69]
  PIN i[6]
    DIRECTION INPUT ;
    USE SIGNAL ;
    PORT
      LAYER M4 ;
        RECT  38.796 52.08 38.88 52.104 ;
    END
  END i[6]
  PIN i[70]
    DIRECTION INPUT ;
    USE SIGNAL ;
    PORT
      LAYER M4 ;
        RECT  38.796 29.808 38.88 29.832 ;
    END
  END i[70]
  PIN i[71]
    DIRECTION INPUT ;
    USE SIGNAL ;
    PORT
      LAYER M4 ;
        RECT  38.796 29.904 38.88 29.928 ;
    END
  END i[71]
  PIN i[72]
    DIRECTION INPUT ;
    USE SIGNAL ;
    PORT
      LAYER M4 ;
        RECT  38.796 30 38.88 30.024 ;
    END
  END i[72]
  PIN i[73]
    DIRECTION INPUT ;
    USE SIGNAL ;
    PORT
      LAYER M4 ;
        RECT  38.796 30.096 38.88 30.12 ;
    END
  END i[73]
  PIN i[74]
    DIRECTION INPUT ;
    USE SIGNAL ;
    PORT
      LAYER M4 ;
        RECT  38.796 30.192 38.88 30.216 ;
    END
  END i[74]
  PIN i[75]
    DIRECTION INPUT ;
    USE SIGNAL ;
    PORT
      LAYER M4 ;
        RECT  38.796 30.288 38.88 30.312 ;
    END
  END i[75]
  PIN i[76]
    DIRECTION INPUT ;
    USE SIGNAL ;
    PORT
      LAYER M4 ;
        RECT  38.796 30.384 38.88 30.408 ;
    END
  END i[76]
  PIN i[77]
    DIRECTION INPUT ;
    USE SIGNAL ;
    PORT
      LAYER M4 ;
        RECT  38.796 30.48 38.88 30.504 ;
    END
  END i[77]
  PIN i[78]
    DIRECTION INPUT ;
    USE SIGNAL ;
    PORT
      LAYER M4 ;
        RECT  38.796 30.576 38.88 30.6 ;
    END
  END i[78]
  PIN i[79]
    DIRECTION INPUT ;
    USE SIGNAL ;
    PORT
      LAYER M4 ;
        RECT  38.796 30.672 38.88 30.696 ;
    END
  END i[79]
  PIN i[7]
    DIRECTION INPUT ;
    USE SIGNAL ;
    PORT
      LAYER M4 ;
        RECT  38.796 52.176 38.88 52.2 ;
    END
  END i[7]
  PIN i[80]
    DIRECTION INPUT ;
    USE SIGNAL ;
    PORT
      LAYER M4 ;
        RECT  38.796 30.768 38.88 30.792 ;
    END
  END i[80]
  PIN i[81]
    DIRECTION INPUT ;
    USE SIGNAL ;
    PORT
      LAYER M4 ;
        RECT  38.796 30.864 38.88 30.888 ;
    END
  END i[81]
  PIN i[82]
    DIRECTION INPUT ;
    USE SIGNAL ;
    PORT
      LAYER M4 ;
        RECT  38.796 30.96 38.88 30.984 ;
    END
  END i[82]
  PIN i[83]
    DIRECTION INPUT ;
    USE SIGNAL ;
    PORT
      LAYER M4 ;
        RECT  38.796 31.056 38.88 31.08 ;
    END
  END i[83]
  PIN i[84]
    DIRECTION INPUT ;
    USE SIGNAL ;
    PORT
      LAYER M4 ;
        RECT  38.796 31.152 38.88 31.176 ;
    END
  END i[84]
  PIN i[85]
    DIRECTION INPUT ;
    USE SIGNAL ;
    PORT
      LAYER M4 ;
        RECT  38.796 31.248 38.88 31.272 ;
    END
  END i[85]
  PIN i[86]
    DIRECTION INPUT ;
    USE SIGNAL ;
    PORT
      LAYER M4 ;
        RECT  38.796 31.344 38.88 31.368 ;
    END
  END i[86]
  PIN i[87]
    DIRECTION INPUT ;
    USE SIGNAL ;
    PORT
      LAYER M4 ;
        RECT  38.796 31.44 38.88 31.464 ;
    END
  END i[87]
  PIN i[88]
    DIRECTION INPUT ;
    USE SIGNAL ;
    PORT
      LAYER M4 ;
        RECT  38.796 31.536 38.88 31.56 ;
    END
  END i[88]
  PIN i[89]
    DIRECTION INPUT ;
    USE SIGNAL ;
    PORT
      LAYER M4 ;
        RECT  38.796 31.632 38.88 31.656 ;
    END
  END i[89]
  PIN i[8]
    DIRECTION INPUT ;
    USE SIGNAL ;
    PORT
      LAYER M4 ;
        RECT  38.796 52.272 38.88 52.296 ;
    END
  END i[8]
  PIN i[90]
    DIRECTION INPUT ;
    USE SIGNAL ;
    PORT
      LAYER M4 ;
        RECT  38.796 31.728 38.88 31.752 ;
    END
  END i[90]
  PIN i[91]
    DIRECTION INPUT ;
    USE SIGNAL ;
    PORT
      LAYER M4 ;
        RECT  38.796 31.824 38.88 31.848 ;
    END
  END i[91]
  PIN i[92]
    DIRECTION INPUT ;
    USE SIGNAL ;
    PORT
      LAYER M4 ;
        RECT  38.796 31.92 38.88 31.944 ;
    END
  END i[92]
  PIN i[93]
    DIRECTION INPUT ;
    USE SIGNAL ;
    PORT
      LAYER M4 ;
        RECT  38.796 32.016 38.88 32.04 ;
    END
  END i[93]
  PIN i[94]
    DIRECTION INPUT ;
    USE SIGNAL ;
    PORT
      LAYER M4 ;
        RECT  38.796 32.112 38.88 32.136 ;
    END
  END i[94]
  PIN i[95]
    DIRECTION INPUT ;
    USE SIGNAL ;
    PORT
      LAYER M4 ;
        RECT  38.796 16.08 38.88 16.104 ;
    END
  END i[95]
  PIN i[96]
    DIRECTION INPUT ;
    USE SIGNAL ;
    PORT
      LAYER M4 ;
        RECT  38.796 16.176 38.88 16.2 ;
    END
  END i[96]
  PIN i[97]
    DIRECTION INPUT ;
    USE SIGNAL ;
    PORT
      LAYER M4 ;
        RECT  38.796 16.272 38.88 16.296 ;
    END
  END i[97]
  PIN i[98]
    DIRECTION INPUT ;
    USE SIGNAL ;
    PORT
      LAYER M4 ;
        RECT  38.796 16.368 38.88 16.392 ;
    END
  END i[98]
  PIN i[99]
    DIRECTION INPUT ;
    USE SIGNAL ;
    PORT
      LAYER M4 ;
        RECT  38.796 16.464 38.88 16.488 ;
    END
  END i[99]
  PIN i[9]
    DIRECTION INPUT ;
    USE SIGNAL ;
    PORT
      LAYER M4 ;
        RECT  38.796 52.368 38.88 52.392 ;
    END
  END i[9]
  PIN k[0]
    DIRECTION INPUT ;
    USE SIGNAL ;
    PORT
      LAYER M5 ;
        RECT  10.896 94.956 10.92 95.04 ;
    END
  END k[0]
  PIN k[1]
    DIRECTION INPUT ;
    USE SIGNAL ;
    PORT
      LAYER M5 ;
        RECT  10.992 94.956 11.016 95.04 ;
    END
  END k[1]
  PIN k[2]
    DIRECTION INPUT ;
    USE SIGNAL ;
    PORT
      LAYER M5 ;
        RECT  11.088 94.956 11.112 95.04 ;
    END
  END k[2]
  PIN o[0]
    DIRECTION OUTPUT ;
    USE SIGNAL ;
    PORT
      LAYER M4 ;
        RECT  0 49.968 0.084 49.992 ;
    END
  END o[0]
  PIN o[100]
    DIRECTION OUTPUT ;
    USE SIGNAL ;
    PORT
      LAYER M4 ;
        RECT  0 18.864 0.084 18.888 ;
    END
  END o[100]
  PIN o[101]
    DIRECTION OUTPUT ;
    USE SIGNAL ;
    PORT
      LAYER M4 ;
        RECT  0 18.96 0.084 18.984 ;
    END
  END o[101]
  PIN o[102]
    DIRECTION OUTPUT ;
    USE SIGNAL ;
    PORT
      LAYER M4 ;
        RECT  0 19.056 0.084 19.08 ;
    END
  END o[102]
  PIN o[103]
    DIRECTION OUTPUT ;
    USE SIGNAL ;
    PORT
      LAYER M4 ;
        RECT  0 19.152 0.084 19.176 ;
    END
  END o[103]
  PIN o[104]
    DIRECTION OUTPUT ;
    USE SIGNAL ;
    PORT
      LAYER M4 ;
        RECT  0 19.248 0.084 19.272 ;
    END
  END o[104]
  PIN o[105]
    DIRECTION OUTPUT ;
    USE SIGNAL ;
    PORT
      LAYER M4 ;
        RECT  0 19.344 0.084 19.368 ;
    END
  END o[105]
  PIN o[106]
    DIRECTION OUTPUT ;
    USE SIGNAL ;
    PORT
      LAYER M4 ;
        RECT  0 19.44 0.084 19.464 ;
    END
  END o[106]
  PIN o[107]
    DIRECTION OUTPUT ;
    USE SIGNAL ;
    PORT
      LAYER M4 ;
        RECT  0 19.536 0.084 19.56 ;
    END
  END o[107]
  PIN o[108]
    DIRECTION OUTPUT ;
    USE SIGNAL ;
    PORT
      LAYER M4 ;
        RECT  0 19.632 0.084 19.656 ;
    END
  END o[108]
  PIN o[109]
    DIRECTION OUTPUT ;
    USE SIGNAL ;
    PORT
      LAYER M4 ;
        RECT  0 19.728 0.084 19.752 ;
    END
  END o[109]
  PIN o[10]
    DIRECTION OUTPUT ;
    USE SIGNAL ;
    PORT
      LAYER M4 ;
        RECT  0 50.928 0.084 50.952 ;
    END
  END o[10]
  PIN o[110]
    DIRECTION OUTPUT ;
    USE SIGNAL ;
    PORT
      LAYER M4 ;
        RECT  0 19.824 0.084 19.848 ;
    END
  END o[110]
  PIN o[111]
    DIRECTION OUTPUT ;
    USE SIGNAL ;
    PORT
      LAYER M4 ;
        RECT  0 19.92 0.084 19.944 ;
    END
  END o[111]
  PIN o[112]
    DIRECTION OUTPUT ;
    USE SIGNAL ;
    PORT
      LAYER M4 ;
        RECT  0 20.016 0.084 20.04 ;
    END
  END o[112]
  PIN o[113]
    DIRECTION OUTPUT ;
    USE SIGNAL ;
    PORT
      LAYER M4 ;
        RECT  0 20.112 0.084 20.136 ;
    END
  END o[113]
  PIN o[114]
    DIRECTION OUTPUT ;
    USE SIGNAL ;
    PORT
      LAYER M4 ;
        RECT  0 20.208 0.084 20.232 ;
    END
  END o[114]
  PIN o[115]
    DIRECTION OUTPUT ;
    USE SIGNAL ;
    PORT
      LAYER M4 ;
        RECT  0 20.304 0.084 20.328 ;
    END
  END o[115]
  PIN o[116]
    DIRECTION OUTPUT ;
    USE SIGNAL ;
    PORT
      LAYER M4 ;
        RECT  0 20.4 0.084 20.424 ;
    END
  END o[116]
  PIN o[117]
    DIRECTION OUTPUT ;
    USE SIGNAL ;
    PORT
      LAYER M4 ;
        RECT  0 20.496 0.084 20.52 ;
    END
  END o[117]
  PIN o[118]
    DIRECTION OUTPUT ;
    USE SIGNAL ;
    PORT
      LAYER M4 ;
        RECT  0 20.592 0.084 20.616 ;
    END
  END o[118]
  PIN o[119]
    DIRECTION OUTPUT ;
    USE SIGNAL ;
    PORT
      LAYER M4 ;
        RECT  0 20.688 0.084 20.712 ;
    END
  END o[119]
  PIN o[11]
    DIRECTION OUTPUT ;
    USE SIGNAL ;
    PORT
      LAYER M4 ;
        RECT  0 51.024 0.084 51.048 ;
    END
  END o[11]
  PIN o[120]
    DIRECTION OUTPUT ;
    USE SIGNAL ;
    PORT
      LAYER M4 ;
        RECT  0 20.784 0.084 20.808 ;
    END
  END o[120]
  PIN o[121]
    DIRECTION OUTPUT ;
    USE SIGNAL ;
    PORT
      LAYER M4 ;
        RECT  0 20.88 0.084 20.904 ;
    END
  END o[121]
  PIN o[122]
    DIRECTION OUTPUT ;
    USE SIGNAL ;
    PORT
      LAYER M4 ;
        RECT  0 20.976 0.084 21 ;
    END
  END o[122]
  PIN o[123]
    DIRECTION OUTPUT ;
    USE SIGNAL ;
    PORT
      LAYER M4 ;
        RECT  0 21.072 0.084 21.096 ;
    END
  END o[123]
  PIN o[124]
    DIRECTION OUTPUT ;
    USE SIGNAL ;
    PORT
      LAYER M4 ;
        RECT  0 21.168 0.084 21.192 ;
    END
  END o[124]
  PIN o[125]
    DIRECTION OUTPUT ;
    USE SIGNAL ;
    PORT
      LAYER M4 ;
        RECT  0 21.264 0.084 21.288 ;
    END
  END o[125]
  PIN o[126]
    DIRECTION OUTPUT ;
    USE SIGNAL ;
    PORT
      LAYER M4 ;
        RECT  0 2.16 0.084 2.184 ;
    END
  END o[126]
  PIN o[127]
    DIRECTION OUTPUT ;
    USE SIGNAL ;
    PORT
      LAYER M4 ;
        RECT  0 2.256 0.084 2.28 ;
    END
  END o[127]
  PIN o[128]
    DIRECTION OUTPUT ;
    USE SIGNAL ;
    PORT
      LAYER M4 ;
        RECT  0 2.352 0.084 2.376 ;
    END
  END o[128]
  PIN o[129]
    DIRECTION OUTPUT ;
    USE SIGNAL ;
    PORT
      LAYER M4 ;
        RECT  0 2.448 0.084 2.472 ;
    END
  END o[129]
  PIN o[12]
    DIRECTION OUTPUT ;
    USE SIGNAL ;
    PORT
      LAYER M4 ;
        RECT  0 51.12 0.084 51.144 ;
    END
  END o[12]
  PIN o[130]
    DIRECTION OUTPUT ;
    USE SIGNAL ;
    PORT
      LAYER M4 ;
        RECT  0 2.544 0.084 2.568 ;
    END
  END o[130]
  PIN o[131]
    DIRECTION OUTPUT ;
    USE SIGNAL ;
    PORT
      LAYER M4 ;
        RECT  0 2.64 0.084 2.664 ;
    END
  END o[131]
  PIN o[132]
    DIRECTION OUTPUT ;
    USE SIGNAL ;
    PORT
      LAYER M4 ;
        RECT  0 2.736 0.084 2.76 ;
    END
  END o[132]
  PIN o[133]
    DIRECTION OUTPUT ;
    USE SIGNAL ;
    PORT
      LAYER M4 ;
        RECT  0 2.832 0.084 2.856 ;
    END
  END o[133]
  PIN o[134]
    DIRECTION OUTPUT ;
    USE SIGNAL ;
    PORT
      LAYER M4 ;
        RECT  0 2.928 0.084 2.952 ;
    END
  END o[134]
  PIN o[135]
    DIRECTION OUTPUT ;
    USE SIGNAL ;
    PORT
      LAYER M4 ;
        RECT  0 3.024 0.084 3.048 ;
    END
  END o[135]
  PIN o[136]
    DIRECTION OUTPUT ;
    USE SIGNAL ;
    PORT
      LAYER M4 ;
        RECT  0 3.12 0.084 3.144 ;
    END
  END o[136]
  PIN o[137]
    DIRECTION OUTPUT ;
    USE SIGNAL ;
    PORT
      LAYER M4 ;
        RECT  0 3.216 0.084 3.24 ;
    END
  END o[137]
  PIN o[138]
    DIRECTION OUTPUT ;
    USE SIGNAL ;
    PORT
      LAYER M4 ;
        RECT  0 3.312 0.084 3.336 ;
    END
  END o[138]
  PIN o[139]
    DIRECTION OUTPUT ;
    USE SIGNAL ;
    PORT
      LAYER M4 ;
        RECT  0 3.408 0.084 3.432 ;
    END
  END o[139]
  PIN o[13]
    DIRECTION OUTPUT ;
    USE SIGNAL ;
    PORT
      LAYER M4 ;
        RECT  0 51.216 0.084 51.24 ;
    END
  END o[13]
  PIN o[140]
    DIRECTION OUTPUT ;
    USE SIGNAL ;
    PORT
      LAYER M4 ;
        RECT  0 3.504 0.084 3.528 ;
    END
  END o[140]
  PIN o[141]
    DIRECTION OUTPUT ;
    USE SIGNAL ;
    PORT
      LAYER M4 ;
        RECT  0 3.6 0.084 3.624 ;
    END
  END o[141]
  PIN o[142]
    DIRECTION OUTPUT ;
    USE SIGNAL ;
    PORT
      LAYER M4 ;
        RECT  0 3.696 0.084 3.72 ;
    END
  END o[142]
  PIN o[143]
    DIRECTION OUTPUT ;
    USE SIGNAL ;
    PORT
      LAYER M4 ;
        RECT  0 3.792 0.084 3.816 ;
    END
  END o[143]
  PIN o[144]
    DIRECTION OUTPUT ;
    USE SIGNAL ;
    PORT
      LAYER M4 ;
        RECT  0 3.888 0.084 3.912 ;
    END
  END o[144]
  PIN o[145]
    DIRECTION OUTPUT ;
    USE SIGNAL ;
    PORT
      LAYER M4 ;
        RECT  0 3.984 0.084 4.008 ;
    END
  END o[145]
  PIN o[146]
    DIRECTION OUTPUT ;
    USE SIGNAL ;
    PORT
      LAYER M4 ;
        RECT  0 4.08 0.084 4.104 ;
    END
  END o[146]
  PIN o[147]
    DIRECTION OUTPUT ;
    USE SIGNAL ;
    PORT
      LAYER M4 ;
        RECT  0 4.176 0.084 4.2 ;
    END
  END o[147]
  PIN o[148]
    DIRECTION OUTPUT ;
    USE SIGNAL ;
    PORT
      LAYER M4 ;
        RECT  0 4.272 0.084 4.296 ;
    END
  END o[148]
  PIN o[149]
    DIRECTION OUTPUT ;
    USE SIGNAL ;
    PORT
      LAYER M4 ;
        RECT  0 4.368 0.084 4.392 ;
    END
  END o[149]
  PIN o[14]
    DIRECTION OUTPUT ;
    USE SIGNAL ;
    PORT
      LAYER M4 ;
        RECT  0 51.312 0.084 51.336 ;
    END
  END o[14]
  PIN o[150]
    DIRECTION OUTPUT ;
    USE SIGNAL ;
    PORT
      LAYER M4 ;
        RECT  0 4.464 0.084 4.488 ;
    END
  END o[150]
  PIN o[151]
    DIRECTION OUTPUT ;
    USE SIGNAL ;
    PORT
      LAYER M4 ;
        RECT  0 4.56 0.084 4.584 ;
    END
  END o[151]
  PIN o[152]
    DIRECTION OUTPUT ;
    USE SIGNAL ;
    PORT
      LAYER M4 ;
        RECT  0 4.656 0.084 4.68 ;
    END
  END o[152]
  PIN o[153]
    DIRECTION OUTPUT ;
    USE SIGNAL ;
    PORT
      LAYER M4 ;
        RECT  0 4.752 0.084 4.776 ;
    END
  END o[153]
  PIN o[154]
    DIRECTION OUTPUT ;
    USE SIGNAL ;
    PORT
      LAYER M4 ;
        RECT  0 4.848 0.084 4.872 ;
    END
  END o[154]
  PIN o[155]
    DIRECTION OUTPUT ;
    USE SIGNAL ;
    PORT
      LAYER M4 ;
        RECT  0 4.944 0.084 4.968 ;
    END
  END o[155]
  PIN o[156]
    DIRECTION OUTPUT ;
    USE SIGNAL ;
    PORT
      LAYER M4 ;
        RECT  0 5.04 0.084 5.064 ;
    END
  END o[156]
  PIN o[157]
    DIRECTION OUTPUT ;
    USE SIGNAL ;
    PORT
      LAYER M4 ;
        RECT  0 5.136 0.084 5.16 ;
    END
  END o[157]
  PIN o[158]
    DIRECTION OUTPUT ;
    USE SIGNAL ;
    PORT
      LAYER M4 ;
        RECT  0 11.376 0.084 11.4 ;
    END
  END o[158]
  PIN o[159]
    DIRECTION OUTPUT ;
    USE SIGNAL ;
    PORT
      LAYER M4 ;
        RECT  0 11.472 0.084 11.496 ;
    END
  END o[159]
  PIN o[15]
    DIRECTION OUTPUT ;
    USE SIGNAL ;
    PORT
      LAYER M4 ;
        RECT  0 51.408 0.084 51.432 ;
    END
  END o[15]
  PIN o[160]
    DIRECTION OUTPUT ;
    USE SIGNAL ;
    PORT
      LAYER M4 ;
        RECT  0 11.568 0.084 11.592 ;
    END
  END o[160]
  PIN o[161]
    DIRECTION OUTPUT ;
    USE SIGNAL ;
    PORT
      LAYER M4 ;
        RECT  0 11.664 0.084 11.688 ;
    END
  END o[161]
  PIN o[162]
    DIRECTION OUTPUT ;
    USE SIGNAL ;
    PORT
      LAYER M4 ;
        RECT  0 11.76 0.084 11.784 ;
    END
  END o[162]
  PIN o[163]
    DIRECTION OUTPUT ;
    USE SIGNAL ;
    PORT
      LAYER M4 ;
        RECT  0 11.856 0.084 11.88 ;
    END
  END o[163]
  PIN o[164]
    DIRECTION OUTPUT ;
    USE SIGNAL ;
    PORT
      LAYER M4 ;
        RECT  0 11.952 0.084 11.976 ;
    END
  END o[164]
  PIN o[165]
    DIRECTION OUTPUT ;
    USE SIGNAL ;
    PORT
      LAYER M4 ;
        RECT  0 12.048 0.084 12.072 ;
    END
  END o[165]
  PIN o[166]
    DIRECTION OUTPUT ;
    USE SIGNAL ;
    PORT
      LAYER M4 ;
        RECT  0 12.144 0.084 12.168 ;
    END
  END o[166]
  PIN o[167]
    DIRECTION OUTPUT ;
    USE SIGNAL ;
    PORT
      LAYER M4 ;
        RECT  0 12.24 0.084 12.264 ;
    END
  END o[167]
  PIN o[168]
    DIRECTION OUTPUT ;
    USE SIGNAL ;
    PORT
      LAYER M4 ;
        RECT  0 12.336 0.084 12.36 ;
    END
  END o[168]
  PIN o[169]
    DIRECTION OUTPUT ;
    USE SIGNAL ;
    PORT
      LAYER M4 ;
        RECT  0 12.432 0.084 12.456 ;
    END
  END o[169]
  PIN o[16]
    DIRECTION OUTPUT ;
    USE SIGNAL ;
    PORT
      LAYER M4 ;
        RECT  0 51.504 0.084 51.528 ;
    END
  END o[16]
  PIN o[170]
    DIRECTION OUTPUT ;
    USE SIGNAL ;
    PORT
      LAYER M4 ;
        RECT  0 12.528 0.084 12.552 ;
    END
  END o[170]
  PIN o[171]
    DIRECTION OUTPUT ;
    USE SIGNAL ;
    PORT
      LAYER M4 ;
        RECT  0 12.624 0.084 12.648 ;
    END
  END o[171]
  PIN o[172]
    DIRECTION OUTPUT ;
    USE SIGNAL ;
    PORT
      LAYER M4 ;
        RECT  0 12.72 0.084 12.744 ;
    END
  END o[172]
  PIN o[173]
    DIRECTION OUTPUT ;
    USE SIGNAL ;
    PORT
      LAYER M4 ;
        RECT  0 12.816 0.084 12.84 ;
    END
  END o[173]
  PIN o[174]
    DIRECTION OUTPUT ;
    USE SIGNAL ;
    PORT
      LAYER M4 ;
        RECT  0 12.912 0.084 12.936 ;
    END
  END o[174]
  PIN o[175]
    DIRECTION OUTPUT ;
    USE SIGNAL ;
    PORT
      LAYER M4 ;
        RECT  0 13.008 0.084 13.032 ;
    END
  END o[175]
  PIN o[176]
    DIRECTION OUTPUT ;
    USE SIGNAL ;
    PORT
      LAYER M4 ;
        RECT  0 13.104 0.084 13.128 ;
    END
  END o[176]
  PIN o[177]
    DIRECTION OUTPUT ;
    USE SIGNAL ;
    PORT
      LAYER M4 ;
        RECT  0 13.2 0.084 13.224 ;
    END
  END o[177]
  PIN o[178]
    DIRECTION OUTPUT ;
    USE SIGNAL ;
    PORT
      LAYER M4 ;
        RECT  0 13.296 0.084 13.32 ;
    END
  END o[178]
  PIN o[179]
    DIRECTION OUTPUT ;
    USE SIGNAL ;
    PORT
      LAYER M4 ;
        RECT  0 13.392 0.084 13.416 ;
    END
  END o[179]
  PIN o[17]
    DIRECTION OUTPUT ;
    USE SIGNAL ;
    PORT
      LAYER M4 ;
        RECT  0 51.6 0.084 51.624 ;
    END
  END o[17]
  PIN o[180]
    DIRECTION OUTPUT ;
    USE SIGNAL ;
    PORT
      LAYER M4 ;
        RECT  0 13.488 0.084 13.512 ;
    END
  END o[180]
  PIN o[181]
    DIRECTION OUTPUT ;
    USE SIGNAL ;
    PORT
      LAYER M4 ;
        RECT  0 13.584 0.084 13.608 ;
    END
  END o[181]
  PIN o[182]
    DIRECTION OUTPUT ;
    USE SIGNAL ;
    PORT
      LAYER M4 ;
        RECT  0 13.68 0.084 13.704 ;
    END
  END o[182]
  PIN o[183]
    DIRECTION OUTPUT ;
    USE SIGNAL ;
    PORT
      LAYER M4 ;
        RECT  0 13.776 0.084 13.8 ;
    END
  END o[183]
  PIN o[184]
    DIRECTION OUTPUT ;
    USE SIGNAL ;
    PORT
      LAYER M4 ;
        RECT  0 13.872 0.084 13.896 ;
    END
  END o[184]
  PIN o[185]
    DIRECTION OUTPUT ;
    USE SIGNAL ;
    PORT
      LAYER M4 ;
        RECT  0 13.968 0.084 13.992 ;
    END
  END o[185]
  PIN o[186]
    DIRECTION OUTPUT ;
    USE SIGNAL ;
    PORT
      LAYER M4 ;
        RECT  0 14.064 0.084 14.088 ;
    END
  END o[186]
  PIN o[187]
    DIRECTION OUTPUT ;
    USE SIGNAL ;
    PORT
      LAYER M4 ;
        RECT  0 14.16 0.084 14.184 ;
    END
  END o[187]
  PIN o[188]
    DIRECTION OUTPUT ;
    USE SIGNAL ;
    PORT
      LAYER M4 ;
        RECT  0 14.256 0.084 14.28 ;
    END
  END o[188]
  PIN o[189]
    DIRECTION OUTPUT ;
    USE SIGNAL ;
    PORT
      LAYER M4 ;
        RECT  0 14.352 0.084 14.376 ;
    END
  END o[189]
  PIN o[18]
    DIRECTION OUTPUT ;
    USE SIGNAL ;
    PORT
      LAYER M4 ;
        RECT  0 51.696 0.084 51.72 ;
    END
  END o[18]
  PIN o[190]
    DIRECTION OUTPUT ;
    USE SIGNAL ;
    PORT
      LAYER M4 ;
        RECT  0 14.448 0.084 14.472 ;
    END
  END o[190]
  PIN o[191]
    DIRECTION OUTPUT ;
    USE SIGNAL ;
    PORT
      LAYER M4 ;
        RECT  0 14.544 0.084 14.568 ;
    END
  END o[191]
  PIN o[192]
    DIRECTION OUTPUT ;
    USE SIGNAL ;
    PORT
      LAYER M4 ;
        RECT  0 14.64 0.084 14.664 ;
    END
  END o[192]
  PIN o[193]
    DIRECTION OUTPUT ;
    USE SIGNAL ;
    PORT
      LAYER M4 ;
        RECT  0 14.736 0.084 14.76 ;
    END
  END o[193]
  PIN o[194]
    DIRECTION OUTPUT ;
    USE SIGNAL ;
    PORT
      LAYER M4 ;
        RECT  0 14.832 0.084 14.856 ;
    END
  END o[194]
  PIN o[195]
    DIRECTION OUTPUT ;
    USE SIGNAL ;
    PORT
      LAYER M4 ;
        RECT  0 14.928 0.084 14.952 ;
    END
  END o[195]
  PIN o[196]
    DIRECTION OUTPUT ;
    USE SIGNAL ;
    PORT
      LAYER M4 ;
        RECT  0 15.024 0.084 15.048 ;
    END
  END o[196]
  PIN o[197]
    DIRECTION OUTPUT ;
    USE SIGNAL ;
    PORT
      LAYER M4 ;
        RECT  0 15.12 0.084 15.144 ;
    END
  END o[197]
  PIN o[198]
    DIRECTION OUTPUT ;
    USE SIGNAL ;
    PORT
      LAYER M4 ;
        RECT  0 15.216 0.084 15.24 ;
    END
  END o[198]
  PIN o[199]
    DIRECTION OUTPUT ;
    USE SIGNAL ;
    PORT
      LAYER M4 ;
        RECT  0 15.312 0.084 15.336 ;
    END
  END o[199]
  PIN o[19]
    DIRECTION OUTPUT ;
    USE SIGNAL ;
    PORT
      LAYER M4 ;
        RECT  0 51.792 0.084 51.816 ;
    END
  END o[19]
  PIN o[1]
    DIRECTION OUTPUT ;
    USE SIGNAL ;
    PORT
      LAYER M4 ;
        RECT  0 50.064 0.084 50.088 ;
    END
  END o[1]
  PIN o[200]
    DIRECTION OUTPUT ;
    USE SIGNAL ;
    PORT
      LAYER M4 ;
        RECT  0 15.408 0.084 15.432 ;
    END
  END o[200]
  PIN o[201]
    DIRECTION OUTPUT ;
    USE SIGNAL ;
    PORT
      LAYER M4 ;
        RECT  0 15.504 0.084 15.528 ;
    END
  END o[201]
  PIN o[202]
    DIRECTION OUTPUT ;
    USE SIGNAL ;
    PORT
      LAYER M4 ;
        RECT  0 15.6 0.084 15.624 ;
    END
  END o[202]
  PIN o[203]
    DIRECTION OUTPUT ;
    USE SIGNAL ;
    PORT
      LAYER M4 ;
        RECT  0 15.696 0.084 15.72 ;
    END
  END o[203]
  PIN o[204]
    DIRECTION OUTPUT ;
    USE SIGNAL ;
    PORT
      LAYER M4 ;
        RECT  0 15.792 0.084 15.816 ;
    END
  END o[204]
  PIN o[205]
    DIRECTION OUTPUT ;
    USE SIGNAL ;
    PORT
      LAYER M4 ;
        RECT  0 15.888 0.084 15.912 ;
    END
  END o[205]
  PIN o[206]
    DIRECTION OUTPUT ;
    USE SIGNAL ;
    PORT
      LAYER M4 ;
        RECT  0 15.984 0.084 16.008 ;
    END
  END o[206]
  PIN o[207]
    DIRECTION OUTPUT ;
    USE SIGNAL ;
    PORT
      LAYER M4 ;
        RECT  0 16.08 0.084 16.104 ;
    END
  END o[207]
  PIN o[208]
    DIRECTION OUTPUT ;
    USE SIGNAL ;
    PORT
      LAYER M4 ;
        RECT  0 16.176 0.084 16.2 ;
    END
  END o[208]
  PIN o[209]
    DIRECTION OUTPUT ;
    USE SIGNAL ;
    PORT
      LAYER M4 ;
        RECT  0 16.272 0.084 16.296 ;
    END
  END o[209]
  PIN o[20]
    DIRECTION OUTPUT ;
    USE SIGNAL ;
    PORT
      LAYER M4 ;
        RECT  0 51.888 0.084 51.912 ;
    END
  END o[20]
  PIN o[210]
    DIRECTION OUTPUT ;
    USE SIGNAL ;
    PORT
      LAYER M4 ;
        RECT  0 16.368 0.084 16.392 ;
    END
  END o[210]
  PIN o[211]
    DIRECTION OUTPUT ;
    USE SIGNAL ;
    PORT
      LAYER M4 ;
        RECT  0 16.464 0.084 16.488 ;
    END
  END o[211]
  PIN o[212]
    DIRECTION OUTPUT ;
    USE SIGNAL ;
    PORT
      LAYER M4 ;
        RECT  0 16.56 0.084 16.584 ;
    END
  END o[212]
  PIN o[213]
    DIRECTION OUTPUT ;
    USE SIGNAL ;
    PORT
      LAYER M4 ;
        RECT  0 16.656 0.084 16.68 ;
    END
  END o[213]
  PIN o[214]
    DIRECTION OUTPUT ;
    USE SIGNAL ;
    PORT
      LAYER M4 ;
        RECT  0 16.752 0.084 16.776 ;
    END
  END o[214]
  PIN o[215]
    DIRECTION OUTPUT ;
    USE SIGNAL ;
    PORT
      LAYER M4 ;
        RECT  0 16.848 0.084 16.872 ;
    END
  END o[215]
  PIN o[216]
    DIRECTION OUTPUT ;
    USE SIGNAL ;
    PORT
      LAYER M4 ;
        RECT  0 16.944 0.084 16.968 ;
    END
  END o[216]
  PIN o[217]
    DIRECTION OUTPUT ;
    USE SIGNAL ;
    PORT
      LAYER M4 ;
        RECT  0 17.04 0.084 17.064 ;
    END
  END o[217]
  PIN o[218]
    DIRECTION OUTPUT ;
    USE SIGNAL ;
    PORT
      LAYER M4 ;
        RECT  0 17.136 0.084 17.16 ;
    END
  END o[218]
  PIN o[219]
    DIRECTION OUTPUT ;
    USE SIGNAL ;
    PORT
      LAYER M4 ;
        RECT  0 17.232 0.084 17.256 ;
    END
  END o[219]
  PIN o[21]
    DIRECTION OUTPUT ;
    USE SIGNAL ;
    PORT
      LAYER M4 ;
        RECT  0 51.984 0.084 52.008 ;
    END
  END o[21]
  PIN o[220]
    DIRECTION OUTPUT ;
    USE SIGNAL ;
    PORT
      LAYER M4 ;
        RECT  0 17.328 0.084 17.352 ;
    END
  END o[220]
  PIN o[221]
    DIRECTION OUTPUT ;
    USE SIGNAL ;
    PORT
      LAYER M4 ;
        RECT  0 17.424 0.084 17.448 ;
    END
  END o[221]
  PIN o[222]
    DIRECTION OUTPUT ;
    USE SIGNAL ;
    PORT
      LAYER M4 ;
        RECT  0 27.504 0.084 27.528 ;
    END
  END o[222]
  PIN o[223]
    DIRECTION OUTPUT ;
    USE SIGNAL ;
    PORT
      LAYER M4 ;
        RECT  0 27.6 0.084 27.624 ;
    END
  END o[223]
  PIN o[224]
    DIRECTION OUTPUT ;
    USE SIGNAL ;
    PORT
      LAYER M4 ;
        RECT  0 27.696 0.084 27.72 ;
    END
  END o[224]
  PIN o[225]
    DIRECTION OUTPUT ;
    USE SIGNAL ;
    PORT
      LAYER M4 ;
        RECT  0 27.792 0.084 27.816 ;
    END
  END o[225]
  PIN o[226]
    DIRECTION OUTPUT ;
    USE SIGNAL ;
    PORT
      LAYER M4 ;
        RECT  0 27.888 0.084 27.912 ;
    END
  END o[226]
  PIN o[227]
    DIRECTION OUTPUT ;
    USE SIGNAL ;
    PORT
      LAYER M4 ;
        RECT  0 27.984 0.084 28.008 ;
    END
  END o[227]
  PIN o[228]
    DIRECTION OUTPUT ;
    USE SIGNAL ;
    PORT
      LAYER M4 ;
        RECT  0 28.08 0.084 28.104 ;
    END
  END o[228]
  PIN o[229]
    DIRECTION OUTPUT ;
    USE SIGNAL ;
    PORT
      LAYER M4 ;
        RECT  0 28.176 0.084 28.2 ;
    END
  END o[229]
  PIN o[22]
    DIRECTION OUTPUT ;
    USE SIGNAL ;
    PORT
      LAYER M4 ;
        RECT  0 52.08 0.084 52.104 ;
    END
  END o[22]
  PIN o[230]
    DIRECTION OUTPUT ;
    USE SIGNAL ;
    PORT
      LAYER M4 ;
        RECT  0 28.272 0.084 28.296 ;
    END
  END o[230]
  PIN o[231]
    DIRECTION OUTPUT ;
    USE SIGNAL ;
    PORT
      LAYER M4 ;
        RECT  0 28.368 0.084 28.392 ;
    END
  END o[231]
  PIN o[232]
    DIRECTION OUTPUT ;
    USE SIGNAL ;
    PORT
      LAYER M4 ;
        RECT  0 28.464 0.084 28.488 ;
    END
  END o[232]
  PIN o[233]
    DIRECTION OUTPUT ;
    USE SIGNAL ;
    PORT
      LAYER M4 ;
        RECT  0 28.56 0.084 28.584 ;
    END
  END o[233]
  PIN o[234]
    DIRECTION OUTPUT ;
    USE SIGNAL ;
    PORT
      LAYER M4 ;
        RECT  0 28.656 0.084 28.68 ;
    END
  END o[234]
  PIN o[235]
    DIRECTION OUTPUT ;
    USE SIGNAL ;
    PORT
      LAYER M4 ;
        RECT  0 28.752 0.084 28.776 ;
    END
  END o[235]
  PIN o[236]
    DIRECTION OUTPUT ;
    USE SIGNAL ;
    PORT
      LAYER M4 ;
        RECT  0 28.848 0.084 28.872 ;
    END
  END o[236]
  PIN o[237]
    DIRECTION OUTPUT ;
    USE SIGNAL ;
    PORT
      LAYER M4 ;
        RECT  0 28.944 0.084 28.968 ;
    END
  END o[237]
  PIN o[238]
    DIRECTION OUTPUT ;
    USE SIGNAL ;
    PORT
      LAYER M4 ;
        RECT  0 29.04 0.084 29.064 ;
    END
  END o[238]
  PIN o[239]
    DIRECTION OUTPUT ;
    USE SIGNAL ;
    PORT
      LAYER M4 ;
        RECT  0 29.136 0.084 29.16 ;
    END
  END o[239]
  PIN o[23]
    DIRECTION OUTPUT ;
    USE SIGNAL ;
    PORT
      LAYER M4 ;
        RECT  0 52.176 0.084 52.2 ;
    END
  END o[23]
  PIN o[240]
    DIRECTION OUTPUT ;
    USE SIGNAL ;
    PORT
      LAYER M4 ;
        RECT  0 29.232 0.084 29.256 ;
    END
  END o[240]
  PIN o[241]
    DIRECTION OUTPUT ;
    USE SIGNAL ;
    PORT
      LAYER M4 ;
        RECT  0 29.328 0.084 29.352 ;
    END
  END o[241]
  PIN o[242]
    DIRECTION OUTPUT ;
    USE SIGNAL ;
    PORT
      LAYER M4 ;
        RECT  0 29.424 0.084 29.448 ;
    END
  END o[242]
  PIN o[243]
    DIRECTION OUTPUT ;
    USE SIGNAL ;
    PORT
      LAYER M4 ;
        RECT  0 29.52 0.084 29.544 ;
    END
  END o[243]
  PIN o[244]
    DIRECTION OUTPUT ;
    USE SIGNAL ;
    PORT
      LAYER M4 ;
        RECT  0 29.616 0.084 29.64 ;
    END
  END o[244]
  PIN o[245]
    DIRECTION OUTPUT ;
    USE SIGNAL ;
    PORT
      LAYER M4 ;
        RECT  0 29.712 0.084 29.736 ;
    END
  END o[245]
  PIN o[246]
    DIRECTION OUTPUT ;
    USE SIGNAL ;
    PORT
      LAYER M4 ;
        RECT  0 29.808 0.084 29.832 ;
    END
  END o[246]
  PIN o[247]
    DIRECTION OUTPUT ;
    USE SIGNAL ;
    PORT
      LAYER M4 ;
        RECT  0 29.904 0.084 29.928 ;
    END
  END o[247]
  PIN o[248]
    DIRECTION OUTPUT ;
    USE SIGNAL ;
    PORT
      LAYER M4 ;
        RECT  0 30 0.084 30.024 ;
    END
  END o[248]
  PIN o[249]
    DIRECTION OUTPUT ;
    USE SIGNAL ;
    PORT
      LAYER M4 ;
        RECT  0 30.096 0.084 30.12 ;
    END
  END o[249]
  PIN o[24]
    DIRECTION OUTPUT ;
    USE SIGNAL ;
    PORT
      LAYER M4 ;
        RECT  0 52.272 0.084 52.296 ;
    END
  END o[24]
  PIN o[250]
    DIRECTION OUTPUT ;
    USE SIGNAL ;
    PORT
      LAYER M4 ;
        RECT  0 30.192 0.084 30.216 ;
    END
  END o[250]
  PIN o[251]
    DIRECTION OUTPUT ;
    USE SIGNAL ;
    PORT
      LAYER M4 ;
        RECT  0 30.288 0.084 30.312 ;
    END
  END o[251]
  PIN o[252]
    DIRECTION OUTPUT ;
    USE SIGNAL ;
    PORT
      LAYER M4 ;
        RECT  0 30.384 0.084 30.408 ;
    END
  END o[252]
  PIN o[253]
    DIRECTION OUTPUT ;
    USE SIGNAL ;
    PORT
      LAYER M4 ;
        RECT  0 30.48 0.084 30.504 ;
    END
  END o[253]
  PIN o[254]
    DIRECTION OUTPUT ;
    USE SIGNAL ;
    PORT
      LAYER M4 ;
        RECT  0 40.56 0.084 40.584 ;
    END
  END o[254]
  PIN o[255]
    DIRECTION OUTPUT ;
    USE SIGNAL ;
    PORT
      LAYER M4 ;
        RECT  0 40.656 0.084 40.68 ;
    END
  END o[255]
  PIN o[256]
    DIRECTION OUTPUT ;
    USE SIGNAL ;
    PORT
      LAYER M4 ;
        RECT  0 40.752 0.084 40.776 ;
    END
  END o[256]
  PIN o[257]
    DIRECTION OUTPUT ;
    USE SIGNAL ;
    PORT
      LAYER M4 ;
        RECT  0 40.848 0.084 40.872 ;
    END
  END o[257]
  PIN o[258]
    DIRECTION OUTPUT ;
    USE SIGNAL ;
    PORT
      LAYER M4 ;
        RECT  0 40.944 0.084 40.968 ;
    END
  END o[258]
  PIN o[259]
    DIRECTION OUTPUT ;
    USE SIGNAL ;
    PORT
      LAYER M4 ;
        RECT  0 41.04 0.084 41.064 ;
    END
  END o[259]
  PIN o[25]
    DIRECTION OUTPUT ;
    USE SIGNAL ;
    PORT
      LAYER M4 ;
        RECT  0 52.368 0.084 52.392 ;
    END
  END o[25]
  PIN o[260]
    DIRECTION OUTPUT ;
    USE SIGNAL ;
    PORT
      LAYER M4 ;
        RECT  0 41.136 0.084 41.16 ;
    END
  END o[260]
  PIN o[261]
    DIRECTION OUTPUT ;
    USE SIGNAL ;
    PORT
      LAYER M4 ;
        RECT  0 41.232 0.084 41.256 ;
    END
  END o[261]
  PIN o[262]
    DIRECTION OUTPUT ;
    USE SIGNAL ;
    PORT
      LAYER M4 ;
        RECT  0 41.328 0.084 41.352 ;
    END
  END o[262]
  PIN o[263]
    DIRECTION OUTPUT ;
    USE SIGNAL ;
    PORT
      LAYER M4 ;
        RECT  0 41.424 0.084 41.448 ;
    END
  END o[263]
  PIN o[264]
    DIRECTION OUTPUT ;
    USE SIGNAL ;
    PORT
      LAYER M4 ;
        RECT  0 41.52 0.084 41.544 ;
    END
  END o[264]
  PIN o[265]
    DIRECTION OUTPUT ;
    USE SIGNAL ;
    PORT
      LAYER M4 ;
        RECT  0 41.616 0.084 41.64 ;
    END
  END o[265]
  PIN o[266]
    DIRECTION OUTPUT ;
    USE SIGNAL ;
    PORT
      LAYER M4 ;
        RECT  0 41.712 0.084 41.736 ;
    END
  END o[266]
  PIN o[267]
    DIRECTION OUTPUT ;
    USE SIGNAL ;
    PORT
      LAYER M4 ;
        RECT  0 41.808 0.084 41.832 ;
    END
  END o[267]
  PIN o[268]
    DIRECTION OUTPUT ;
    USE SIGNAL ;
    PORT
      LAYER M4 ;
        RECT  0 41.904 0.084 41.928 ;
    END
  END o[268]
  PIN o[269]
    DIRECTION OUTPUT ;
    USE SIGNAL ;
    PORT
      LAYER M4 ;
        RECT  0 42 0.084 42.024 ;
    END
  END o[269]
  PIN o[26]
    DIRECTION OUTPUT ;
    USE SIGNAL ;
    PORT
      LAYER M4 ;
        RECT  0 52.464 0.084 52.488 ;
    END
  END o[26]
  PIN o[270]
    DIRECTION OUTPUT ;
    USE SIGNAL ;
    PORT
      LAYER M4 ;
        RECT  0 42.096 0.084 42.12 ;
    END
  END o[270]
  PIN o[271]
    DIRECTION OUTPUT ;
    USE SIGNAL ;
    PORT
      LAYER M4 ;
        RECT  0 42.192 0.084 42.216 ;
    END
  END o[271]
  PIN o[272]
    DIRECTION OUTPUT ;
    USE SIGNAL ;
    PORT
      LAYER M4 ;
        RECT  0 42.288 0.084 42.312 ;
    END
  END o[272]
  PIN o[273]
    DIRECTION OUTPUT ;
    USE SIGNAL ;
    PORT
      LAYER M4 ;
        RECT  0 42.384 0.084 42.408 ;
    END
  END o[273]
  PIN o[274]
    DIRECTION OUTPUT ;
    USE SIGNAL ;
    PORT
      LAYER M4 ;
        RECT  0 42.48 0.084 42.504 ;
    END
  END o[274]
  PIN o[275]
    DIRECTION OUTPUT ;
    USE SIGNAL ;
    PORT
      LAYER M4 ;
        RECT  0 42.576 0.084 42.6 ;
    END
  END o[275]
  PIN o[276]
    DIRECTION OUTPUT ;
    USE SIGNAL ;
    PORT
      LAYER M4 ;
        RECT  0 42.672 0.084 42.696 ;
    END
  END o[276]
  PIN o[277]
    DIRECTION OUTPUT ;
    USE SIGNAL ;
    PORT
      LAYER M4 ;
        RECT  0 42.768 0.084 42.792 ;
    END
  END o[277]
  PIN o[278]
    DIRECTION OUTPUT ;
    USE SIGNAL ;
    PORT
      LAYER M4 ;
        RECT  0 42.864 0.084 42.888 ;
    END
  END o[278]
  PIN o[279]
    DIRECTION OUTPUT ;
    USE SIGNAL ;
    PORT
      LAYER M4 ;
        RECT  0 42.96 0.084 42.984 ;
    END
  END o[279]
  PIN o[27]
    DIRECTION OUTPUT ;
    USE SIGNAL ;
    PORT
      LAYER M4 ;
        RECT  0 52.56 0.084 52.584 ;
    END
  END o[27]
  PIN o[280]
    DIRECTION OUTPUT ;
    USE SIGNAL ;
    PORT
      LAYER M4 ;
        RECT  0 43.056 0.084 43.08 ;
    END
  END o[280]
  PIN o[281]
    DIRECTION OUTPUT ;
    USE SIGNAL ;
    PORT
      LAYER M4 ;
        RECT  0 43.152 0.084 43.176 ;
    END
  END o[281]
  PIN o[282]
    DIRECTION OUTPUT ;
    USE SIGNAL ;
    PORT
      LAYER M4 ;
        RECT  0 43.248 0.084 43.272 ;
    END
  END o[282]
  PIN o[283]
    DIRECTION OUTPUT ;
    USE SIGNAL ;
    PORT
      LAYER M4 ;
        RECT  0 43.344 0.084 43.368 ;
    END
  END o[283]
  PIN o[284]
    DIRECTION OUTPUT ;
    USE SIGNAL ;
    PORT
      LAYER M4 ;
        RECT  0 43.44 0.084 43.464 ;
    END
  END o[284]
  PIN o[285]
    DIRECTION OUTPUT ;
    USE SIGNAL ;
    PORT
      LAYER M4 ;
        RECT  0 43.536 0.084 43.56 ;
    END
  END o[285]
  PIN o[286]
    DIRECTION OUTPUT ;
    USE SIGNAL ;
    PORT
      LAYER M4 ;
        RECT  0 52.848 0.084 52.872 ;
    END
  END o[286]
  PIN o[287]
    DIRECTION OUTPUT ;
    USE SIGNAL ;
    PORT
      LAYER M4 ;
        RECT  0 52.944 0.084 52.968 ;
    END
  END o[287]
  PIN o[288]
    DIRECTION OUTPUT ;
    USE SIGNAL ;
    PORT
      LAYER M4 ;
        RECT  0 53.04 0.084 53.064 ;
    END
  END o[288]
  PIN o[289]
    DIRECTION OUTPUT ;
    USE SIGNAL ;
    PORT
      LAYER M4 ;
        RECT  0 53.136 0.084 53.16 ;
    END
  END o[289]
  PIN o[28]
    DIRECTION OUTPUT ;
    USE SIGNAL ;
    PORT
      LAYER M4 ;
        RECT  0 52.656 0.084 52.68 ;
    END
  END o[28]
  PIN o[290]
    DIRECTION OUTPUT ;
    USE SIGNAL ;
    PORT
      LAYER M4 ;
        RECT  0 53.232 0.084 53.256 ;
    END
  END o[290]
  PIN o[291]
    DIRECTION OUTPUT ;
    USE SIGNAL ;
    PORT
      LAYER M4 ;
        RECT  0 53.328 0.084 53.352 ;
    END
  END o[291]
  PIN o[292]
    DIRECTION OUTPUT ;
    USE SIGNAL ;
    PORT
      LAYER M4 ;
        RECT  0 53.424 0.084 53.448 ;
    END
  END o[292]
  PIN o[293]
    DIRECTION OUTPUT ;
    USE SIGNAL ;
    PORT
      LAYER M4 ;
        RECT  0 53.52 0.084 53.544 ;
    END
  END o[293]
  PIN o[294]
    DIRECTION OUTPUT ;
    USE SIGNAL ;
    PORT
      LAYER M4 ;
        RECT  0 53.616 0.084 53.64 ;
    END
  END o[294]
  PIN o[295]
    DIRECTION OUTPUT ;
    USE SIGNAL ;
    PORT
      LAYER M4 ;
        RECT  0 53.712 0.084 53.736 ;
    END
  END o[295]
  PIN o[296]
    DIRECTION OUTPUT ;
    USE SIGNAL ;
    PORT
      LAYER M4 ;
        RECT  0 53.808 0.084 53.832 ;
    END
  END o[296]
  PIN o[297]
    DIRECTION OUTPUT ;
    USE SIGNAL ;
    PORT
      LAYER M4 ;
        RECT  0 53.904 0.084 53.928 ;
    END
  END o[297]
  PIN o[298]
    DIRECTION OUTPUT ;
    USE SIGNAL ;
    PORT
      LAYER M4 ;
        RECT  0 54 0.084 54.024 ;
    END
  END o[298]
  PIN o[299]
    DIRECTION OUTPUT ;
    USE SIGNAL ;
    PORT
      LAYER M4 ;
        RECT  0 54.096 0.084 54.12 ;
    END
  END o[299]
  PIN o[29]
    DIRECTION OUTPUT ;
    USE SIGNAL ;
    PORT
      LAYER M4 ;
        RECT  0 52.752 0.084 52.776 ;
    END
  END o[29]
  PIN o[2]
    DIRECTION OUTPUT ;
    USE SIGNAL ;
    PORT
      LAYER M4 ;
        RECT  0 50.16 0.084 50.184 ;
    END
  END o[2]
  PIN o[300]
    DIRECTION OUTPUT ;
    USE SIGNAL ;
    PORT
      LAYER M4 ;
        RECT  0 54.192 0.084 54.216 ;
    END
  END o[300]
  PIN o[301]
    DIRECTION OUTPUT ;
    USE SIGNAL ;
    PORT
      LAYER M4 ;
        RECT  0 54.288 0.084 54.312 ;
    END
  END o[301]
  PIN o[302]
    DIRECTION OUTPUT ;
    USE SIGNAL ;
    PORT
      LAYER M4 ;
        RECT  0 54.384 0.084 54.408 ;
    END
  END o[302]
  PIN o[303]
    DIRECTION OUTPUT ;
    USE SIGNAL ;
    PORT
      LAYER M4 ;
        RECT  0 54.48 0.084 54.504 ;
    END
  END o[303]
  PIN o[304]
    DIRECTION OUTPUT ;
    USE SIGNAL ;
    PORT
      LAYER M4 ;
        RECT  0 54.576 0.084 54.6 ;
    END
  END o[304]
  PIN o[305]
    DIRECTION OUTPUT ;
    USE SIGNAL ;
    PORT
      LAYER M4 ;
        RECT  0 54.672 0.084 54.696 ;
    END
  END o[305]
  PIN o[306]
    DIRECTION OUTPUT ;
    USE SIGNAL ;
    PORT
      LAYER M4 ;
        RECT  0 54.768 0.084 54.792 ;
    END
  END o[306]
  PIN o[307]
    DIRECTION OUTPUT ;
    USE SIGNAL ;
    PORT
      LAYER M4 ;
        RECT  0 54.864 0.084 54.888 ;
    END
  END o[307]
  PIN o[308]
    DIRECTION OUTPUT ;
    USE SIGNAL ;
    PORT
      LAYER M4 ;
        RECT  0 54.96 0.084 54.984 ;
    END
  END o[308]
  PIN o[309]
    DIRECTION OUTPUT ;
    USE SIGNAL ;
    PORT
      LAYER M4 ;
        RECT  0 55.056 0.084 55.08 ;
    END
  END o[309]
  PIN o[30]
    DIRECTION OUTPUT ;
    USE SIGNAL ;
    PORT
      LAYER M4 ;
        RECT  0 37.488 0.084 37.512 ;
    END
  END o[30]
  PIN o[310]
    DIRECTION OUTPUT ;
    USE SIGNAL ;
    PORT
      LAYER M4 ;
        RECT  0 55.152 0.084 55.176 ;
    END
  END o[310]
  PIN o[311]
    DIRECTION OUTPUT ;
    USE SIGNAL ;
    PORT
      LAYER M4 ;
        RECT  0 55.248 0.084 55.272 ;
    END
  END o[311]
  PIN o[312]
    DIRECTION OUTPUT ;
    USE SIGNAL ;
    PORT
      LAYER M4 ;
        RECT  0 55.344 0.084 55.368 ;
    END
  END o[312]
  PIN o[313]
    DIRECTION OUTPUT ;
    USE SIGNAL ;
    PORT
      LAYER M4 ;
        RECT  0 55.44 0.084 55.464 ;
    END
  END o[313]
  PIN o[314]
    DIRECTION OUTPUT ;
    USE SIGNAL ;
    PORT
      LAYER M4 ;
        RECT  0 55.536 0.084 55.56 ;
    END
  END o[314]
  PIN o[315]
    DIRECTION OUTPUT ;
    USE SIGNAL ;
    PORT
      LAYER M4 ;
        RECT  0 55.632 0.084 55.656 ;
    END
  END o[315]
  PIN o[316]
    DIRECTION OUTPUT ;
    USE SIGNAL ;
    PORT
      LAYER M4 ;
        RECT  0 55.728 0.084 55.752 ;
    END
  END o[316]
  PIN o[317]
    DIRECTION OUTPUT ;
    USE SIGNAL ;
    PORT
      LAYER M4 ;
        RECT  0 55.824 0.084 55.848 ;
    END
  END o[317]
  PIN o[318]
    DIRECTION OUTPUT ;
    USE SIGNAL ;
    PORT
      LAYER M4 ;
        RECT  0 62.832 0.084 62.856 ;
    END
  END o[318]
  PIN o[319]
    DIRECTION OUTPUT ;
    USE SIGNAL ;
    PORT
      LAYER M4 ;
        RECT  0 62.928 0.084 62.952 ;
    END
  END o[319]
  PIN o[31]
    DIRECTION OUTPUT ;
    USE SIGNAL ;
    PORT
      LAYER M4 ;
        RECT  0 37.584 0.084 37.608 ;
    END
  END o[31]
  PIN o[320]
    DIRECTION OUTPUT ;
    USE SIGNAL ;
    PORT
      LAYER M4 ;
        RECT  0 63.024 0.084 63.048 ;
    END
  END o[320]
  PIN o[321]
    DIRECTION OUTPUT ;
    USE SIGNAL ;
    PORT
      LAYER M4 ;
        RECT  0 63.12 0.084 63.144 ;
    END
  END o[321]
  PIN o[322]
    DIRECTION OUTPUT ;
    USE SIGNAL ;
    PORT
      LAYER M4 ;
        RECT  0 63.216 0.084 63.24 ;
    END
  END o[322]
  PIN o[323]
    DIRECTION OUTPUT ;
    USE SIGNAL ;
    PORT
      LAYER M4 ;
        RECT  0 63.312 0.084 63.336 ;
    END
  END o[323]
  PIN o[324]
    DIRECTION OUTPUT ;
    USE SIGNAL ;
    PORT
      LAYER M4 ;
        RECT  0 63.408 0.084 63.432 ;
    END
  END o[324]
  PIN o[325]
    DIRECTION OUTPUT ;
    USE SIGNAL ;
    PORT
      LAYER M4 ;
        RECT  0 63.504 0.084 63.528 ;
    END
  END o[325]
  PIN o[326]
    DIRECTION OUTPUT ;
    USE SIGNAL ;
    PORT
      LAYER M4 ;
        RECT  0 63.6 0.084 63.624 ;
    END
  END o[326]
  PIN o[327]
    DIRECTION OUTPUT ;
    USE SIGNAL ;
    PORT
      LAYER M4 ;
        RECT  0 63.696 0.084 63.72 ;
    END
  END o[327]
  PIN o[328]
    DIRECTION OUTPUT ;
    USE SIGNAL ;
    PORT
      LAYER M4 ;
        RECT  0 63.792 0.084 63.816 ;
    END
  END o[328]
  PIN o[329]
    DIRECTION OUTPUT ;
    USE SIGNAL ;
    PORT
      LAYER M4 ;
        RECT  0 63.888 0.084 63.912 ;
    END
  END o[329]
  PIN o[32]
    DIRECTION OUTPUT ;
    USE SIGNAL ;
    PORT
      LAYER M4 ;
        RECT  0 37.68 0.084 37.704 ;
    END
  END o[32]
  PIN o[330]
    DIRECTION OUTPUT ;
    USE SIGNAL ;
    PORT
      LAYER M4 ;
        RECT  0 63.984 0.084 64.008 ;
    END
  END o[330]
  PIN o[331]
    DIRECTION OUTPUT ;
    USE SIGNAL ;
    PORT
      LAYER M4 ;
        RECT  0 64.08 0.084 64.104 ;
    END
  END o[331]
  PIN o[332]
    DIRECTION OUTPUT ;
    USE SIGNAL ;
    PORT
      LAYER M4 ;
        RECT  0 64.176 0.084 64.2 ;
    END
  END o[332]
  PIN o[333]
    DIRECTION OUTPUT ;
    USE SIGNAL ;
    PORT
      LAYER M4 ;
        RECT  0 64.272 0.084 64.296 ;
    END
  END o[333]
  PIN o[334]
    DIRECTION OUTPUT ;
    USE SIGNAL ;
    PORT
      LAYER M4 ;
        RECT  0 64.368 0.084 64.392 ;
    END
  END o[334]
  PIN o[335]
    DIRECTION OUTPUT ;
    USE SIGNAL ;
    PORT
      LAYER M4 ;
        RECT  0 64.464 0.084 64.488 ;
    END
  END o[335]
  PIN o[336]
    DIRECTION OUTPUT ;
    USE SIGNAL ;
    PORT
      LAYER M4 ;
        RECT  0 64.56 0.084 64.584 ;
    END
  END o[336]
  PIN o[337]
    DIRECTION OUTPUT ;
    USE SIGNAL ;
    PORT
      LAYER M4 ;
        RECT  0 64.656 0.084 64.68 ;
    END
  END o[337]
  PIN o[338]
    DIRECTION OUTPUT ;
    USE SIGNAL ;
    PORT
      LAYER M4 ;
        RECT  0 64.752 0.084 64.776 ;
    END
  END o[338]
  PIN o[339]
    DIRECTION OUTPUT ;
    USE SIGNAL ;
    PORT
      LAYER M4 ;
        RECT  0 64.848 0.084 64.872 ;
    END
  END o[339]
  PIN o[33]
    DIRECTION OUTPUT ;
    USE SIGNAL ;
    PORT
      LAYER M4 ;
        RECT  0 37.776 0.084 37.8 ;
    END
  END o[33]
  PIN o[340]
    DIRECTION OUTPUT ;
    USE SIGNAL ;
    PORT
      LAYER M4 ;
        RECT  0 64.944 0.084 64.968 ;
    END
  END o[340]
  PIN o[341]
    DIRECTION OUTPUT ;
    USE SIGNAL ;
    PORT
      LAYER M4 ;
        RECT  0 65.04 0.084 65.064 ;
    END
  END o[341]
  PIN o[342]
    DIRECTION OUTPUT ;
    USE SIGNAL ;
    PORT
      LAYER M4 ;
        RECT  0 65.136 0.084 65.16 ;
    END
  END o[342]
  PIN o[343]
    DIRECTION OUTPUT ;
    USE SIGNAL ;
    PORT
      LAYER M4 ;
        RECT  0 65.232 0.084 65.256 ;
    END
  END o[343]
  PIN o[344]
    DIRECTION OUTPUT ;
    USE SIGNAL ;
    PORT
      LAYER M4 ;
        RECT  0 65.328 0.084 65.352 ;
    END
  END o[344]
  PIN o[345]
    DIRECTION OUTPUT ;
    USE SIGNAL ;
    PORT
      LAYER M4 ;
        RECT  0 65.424 0.084 65.448 ;
    END
  END o[345]
  PIN o[346]
    DIRECTION OUTPUT ;
    USE SIGNAL ;
    PORT
      LAYER M4 ;
        RECT  0 65.52 0.084 65.544 ;
    END
  END o[346]
  PIN o[347]
    DIRECTION OUTPUT ;
    USE SIGNAL ;
    PORT
      LAYER M4 ;
        RECT  0 65.616 0.084 65.64 ;
    END
  END o[347]
  PIN o[348]
    DIRECTION OUTPUT ;
    USE SIGNAL ;
    PORT
      LAYER M4 ;
        RECT  0 65.712 0.084 65.736 ;
    END
  END o[348]
  PIN o[349]
    DIRECTION OUTPUT ;
    USE SIGNAL ;
    PORT
      LAYER M4 ;
        RECT  0 65.808 0.084 65.832 ;
    END
  END o[349]
  PIN o[34]
    DIRECTION OUTPUT ;
    USE SIGNAL ;
    PORT
      LAYER M4 ;
        RECT  0 37.872 0.084 37.896 ;
    END
  END o[34]
  PIN o[350]
    DIRECTION OUTPUT ;
    USE SIGNAL ;
    PORT
      LAYER M4 ;
        RECT  0 82.032 0.084 82.056 ;
    END
  END o[350]
  PIN o[351]
    DIRECTION OUTPUT ;
    USE SIGNAL ;
    PORT
      LAYER M4 ;
        RECT  0 82.128 0.084 82.152 ;
    END
  END o[351]
  PIN o[352]
    DIRECTION OUTPUT ;
    USE SIGNAL ;
    PORT
      LAYER M4 ;
        RECT  0 82.224 0.084 82.248 ;
    END
  END o[352]
  PIN o[353]
    DIRECTION OUTPUT ;
    USE SIGNAL ;
    PORT
      LAYER M4 ;
        RECT  0 82.32 0.084 82.344 ;
    END
  END o[353]
  PIN o[354]
    DIRECTION OUTPUT ;
    USE SIGNAL ;
    PORT
      LAYER M4 ;
        RECT  0 82.416 0.084 82.44 ;
    END
  END o[354]
  PIN o[355]
    DIRECTION OUTPUT ;
    USE SIGNAL ;
    PORT
      LAYER M4 ;
        RECT  0 82.512 0.084 82.536 ;
    END
  END o[355]
  PIN o[356]
    DIRECTION OUTPUT ;
    USE SIGNAL ;
    PORT
      LAYER M4 ;
        RECT  0 82.608 0.084 82.632 ;
    END
  END o[356]
  PIN o[357]
    DIRECTION OUTPUT ;
    USE SIGNAL ;
    PORT
      LAYER M4 ;
        RECT  0 82.704 0.084 82.728 ;
    END
  END o[357]
  PIN o[358]
    DIRECTION OUTPUT ;
    USE SIGNAL ;
    PORT
      LAYER M4 ;
        RECT  0 82.8 0.084 82.824 ;
    END
  END o[358]
  PIN o[359]
    DIRECTION OUTPUT ;
    USE SIGNAL ;
    PORT
      LAYER M4 ;
        RECT  0 82.896 0.084 82.92 ;
    END
  END o[359]
  PIN o[35]
    DIRECTION OUTPUT ;
    USE SIGNAL ;
    PORT
      LAYER M4 ;
        RECT  0 37.968 0.084 37.992 ;
    END
  END o[35]
  PIN o[360]
    DIRECTION OUTPUT ;
    USE SIGNAL ;
    PORT
      LAYER M4 ;
        RECT  0 82.992 0.084 83.016 ;
    END
  END o[360]
  PIN o[361]
    DIRECTION OUTPUT ;
    USE SIGNAL ;
    PORT
      LAYER M4 ;
        RECT  0 83.088 0.084 83.112 ;
    END
  END o[361]
  PIN o[362]
    DIRECTION OUTPUT ;
    USE SIGNAL ;
    PORT
      LAYER M4 ;
        RECT  0 83.184 0.084 83.208 ;
    END
  END o[362]
  PIN o[363]
    DIRECTION OUTPUT ;
    USE SIGNAL ;
    PORT
      LAYER M4 ;
        RECT  0 83.28 0.084 83.304 ;
    END
  END o[363]
  PIN o[364]
    DIRECTION OUTPUT ;
    USE SIGNAL ;
    PORT
      LAYER M4 ;
        RECT  0 83.376 0.084 83.4 ;
    END
  END o[364]
  PIN o[365]
    DIRECTION OUTPUT ;
    USE SIGNAL ;
    PORT
      LAYER M4 ;
        RECT  0 83.472 0.084 83.496 ;
    END
  END o[365]
  PIN o[366]
    DIRECTION OUTPUT ;
    USE SIGNAL ;
    PORT
      LAYER M4 ;
        RECT  0 83.568 0.084 83.592 ;
    END
  END o[366]
  PIN o[367]
    DIRECTION OUTPUT ;
    USE SIGNAL ;
    PORT
      LAYER M4 ;
        RECT  0 83.664 0.084 83.688 ;
    END
  END o[367]
  PIN o[368]
    DIRECTION OUTPUT ;
    USE SIGNAL ;
    PORT
      LAYER M4 ;
        RECT  0 83.76 0.084 83.784 ;
    END
  END o[368]
  PIN o[369]
    DIRECTION OUTPUT ;
    USE SIGNAL ;
    PORT
      LAYER M4 ;
        RECT  0 83.856 0.084 83.88 ;
    END
  END o[369]
  PIN o[36]
    DIRECTION OUTPUT ;
    USE SIGNAL ;
    PORT
      LAYER M4 ;
        RECT  0 38.064 0.084 38.088 ;
    END
  END o[36]
  PIN o[370]
    DIRECTION OUTPUT ;
    USE SIGNAL ;
    PORT
      LAYER M4 ;
        RECT  0 83.952 0.084 83.976 ;
    END
  END o[370]
  PIN o[371]
    DIRECTION OUTPUT ;
    USE SIGNAL ;
    PORT
      LAYER M4 ;
        RECT  0 84.048 0.084 84.072 ;
    END
  END o[371]
  PIN o[372]
    DIRECTION OUTPUT ;
    USE SIGNAL ;
    PORT
      LAYER M4 ;
        RECT  0 84.144 0.084 84.168 ;
    END
  END o[372]
  PIN o[373]
    DIRECTION OUTPUT ;
    USE SIGNAL ;
    PORT
      LAYER M4 ;
        RECT  0 84.24 0.084 84.264 ;
    END
  END o[373]
  PIN o[374]
    DIRECTION OUTPUT ;
    USE SIGNAL ;
    PORT
      LAYER M4 ;
        RECT  0 84.336 0.084 84.36 ;
    END
  END o[374]
  PIN o[375]
    DIRECTION OUTPUT ;
    USE SIGNAL ;
    PORT
      LAYER M4 ;
        RECT  0 84.432 0.084 84.456 ;
    END
  END o[375]
  PIN o[376]
    DIRECTION OUTPUT ;
    USE SIGNAL ;
    PORT
      LAYER M4 ;
        RECT  0 84.528 0.084 84.552 ;
    END
  END o[376]
  PIN o[377]
    DIRECTION OUTPUT ;
    USE SIGNAL ;
    PORT
      LAYER M4 ;
        RECT  0 84.624 0.084 84.648 ;
    END
  END o[377]
  PIN o[378]
    DIRECTION OUTPUT ;
    USE SIGNAL ;
    PORT
      LAYER M4 ;
        RECT  0 84.72 0.084 84.744 ;
    END
  END o[378]
  PIN o[379]
    DIRECTION OUTPUT ;
    USE SIGNAL ;
    PORT
      LAYER M4 ;
        RECT  0 84.816 0.084 84.84 ;
    END
  END o[379]
  PIN o[37]
    DIRECTION OUTPUT ;
    USE SIGNAL ;
    PORT
      LAYER M4 ;
        RECT  0 38.16 0.084 38.184 ;
    END
  END o[37]
  PIN o[380]
    DIRECTION OUTPUT ;
    USE SIGNAL ;
    PORT
      LAYER M4 ;
        RECT  0 84.912 0.084 84.936 ;
    END
  END o[380]
  PIN o[381]
    DIRECTION OUTPUT ;
    USE SIGNAL ;
    PORT
      LAYER M4 ;
        RECT  0 85.008 0.084 85.032 ;
    END
  END o[381]
  PIN o[382]
    DIRECTION OUTPUT ;
    USE SIGNAL ;
    PORT
      LAYER M4 ;
        RECT  0 78.96 0.084 78.984 ;
    END
  END o[382]
  PIN o[383]
    DIRECTION OUTPUT ;
    USE SIGNAL ;
    PORT
      LAYER M4 ;
        RECT  0 79.056 0.084 79.08 ;
    END
  END o[383]
  PIN o[384]
    DIRECTION OUTPUT ;
    USE SIGNAL ;
    PORT
      LAYER M4 ;
        RECT  0 79.152 0.084 79.176 ;
    END
  END o[384]
  PIN o[385]
    DIRECTION OUTPUT ;
    USE SIGNAL ;
    PORT
      LAYER M4 ;
        RECT  0 79.248 0.084 79.272 ;
    END
  END o[385]
  PIN o[386]
    DIRECTION OUTPUT ;
    USE SIGNAL ;
    PORT
      LAYER M4 ;
        RECT  0 79.344 0.084 79.368 ;
    END
  END o[386]
  PIN o[387]
    DIRECTION OUTPUT ;
    USE SIGNAL ;
    PORT
      LAYER M4 ;
        RECT  0 79.44 0.084 79.464 ;
    END
  END o[387]
  PIN o[388]
    DIRECTION OUTPUT ;
    USE SIGNAL ;
    PORT
      LAYER M4 ;
        RECT  0 79.536 0.084 79.56 ;
    END
  END o[388]
  PIN o[389]
    DIRECTION OUTPUT ;
    USE SIGNAL ;
    PORT
      LAYER M4 ;
        RECT  0 79.632 0.084 79.656 ;
    END
  END o[389]
  PIN o[38]
    DIRECTION OUTPUT ;
    USE SIGNAL ;
    PORT
      LAYER M4 ;
        RECT  0 38.256 0.084 38.28 ;
    END
  END o[38]
  PIN o[390]
    DIRECTION OUTPUT ;
    USE SIGNAL ;
    PORT
      LAYER M4 ;
        RECT  0 79.728 0.084 79.752 ;
    END
  END o[390]
  PIN o[391]
    DIRECTION OUTPUT ;
    USE SIGNAL ;
    PORT
      LAYER M4 ;
        RECT  0 79.824 0.084 79.848 ;
    END
  END o[391]
  PIN o[392]
    DIRECTION OUTPUT ;
    USE SIGNAL ;
    PORT
      LAYER M4 ;
        RECT  0 79.92 0.084 79.944 ;
    END
  END o[392]
  PIN o[393]
    DIRECTION OUTPUT ;
    USE SIGNAL ;
    PORT
      LAYER M4 ;
        RECT  0 80.016 0.084 80.04 ;
    END
  END o[393]
  PIN o[394]
    DIRECTION OUTPUT ;
    USE SIGNAL ;
    PORT
      LAYER M4 ;
        RECT  0 80.112 0.084 80.136 ;
    END
  END o[394]
  PIN o[395]
    DIRECTION OUTPUT ;
    USE SIGNAL ;
    PORT
      LAYER M4 ;
        RECT  0 80.208 0.084 80.232 ;
    END
  END o[395]
  PIN o[396]
    DIRECTION OUTPUT ;
    USE SIGNAL ;
    PORT
      LAYER M4 ;
        RECT  0 80.304 0.084 80.328 ;
    END
  END o[396]
  PIN o[397]
    DIRECTION OUTPUT ;
    USE SIGNAL ;
    PORT
      LAYER M4 ;
        RECT  0 80.4 0.084 80.424 ;
    END
  END o[397]
  PIN o[398]
    DIRECTION OUTPUT ;
    USE SIGNAL ;
    PORT
      LAYER M4 ;
        RECT  0 80.496 0.084 80.52 ;
    END
  END o[398]
  PIN o[399]
    DIRECTION OUTPUT ;
    USE SIGNAL ;
    PORT
      LAYER M4 ;
        RECT  0 80.592 0.084 80.616 ;
    END
  END o[399]
  PIN o[39]
    DIRECTION OUTPUT ;
    USE SIGNAL ;
    PORT
      LAYER M4 ;
        RECT  0 38.352 0.084 38.376 ;
    END
  END o[39]
  PIN o[3]
    DIRECTION OUTPUT ;
    USE SIGNAL ;
    PORT
      LAYER M4 ;
        RECT  0 50.256 0.084 50.28 ;
    END
  END o[3]
  PIN o[400]
    DIRECTION OUTPUT ;
    USE SIGNAL ;
    PORT
      LAYER M4 ;
        RECT  0 80.688 0.084 80.712 ;
    END
  END o[400]
  PIN o[401]
    DIRECTION OUTPUT ;
    USE SIGNAL ;
    PORT
      LAYER M4 ;
        RECT  0 80.784 0.084 80.808 ;
    END
  END o[401]
  PIN o[402]
    DIRECTION OUTPUT ;
    USE SIGNAL ;
    PORT
      LAYER M4 ;
        RECT  0 80.88 0.084 80.904 ;
    END
  END o[402]
  PIN o[403]
    DIRECTION OUTPUT ;
    USE SIGNAL ;
    PORT
      LAYER M4 ;
        RECT  0 80.976 0.084 81 ;
    END
  END o[403]
  PIN o[404]
    DIRECTION OUTPUT ;
    USE SIGNAL ;
    PORT
      LAYER M4 ;
        RECT  0 81.072 0.084 81.096 ;
    END
  END o[404]
  PIN o[405]
    DIRECTION OUTPUT ;
    USE SIGNAL ;
    PORT
      LAYER M4 ;
        RECT  0 81.168 0.084 81.192 ;
    END
  END o[405]
  PIN o[406]
    DIRECTION OUTPUT ;
    USE SIGNAL ;
    PORT
      LAYER M4 ;
        RECT  0 81.264 0.084 81.288 ;
    END
  END o[406]
  PIN o[407]
    DIRECTION OUTPUT ;
    USE SIGNAL ;
    PORT
      LAYER M4 ;
        RECT  0 81.36 0.084 81.384 ;
    END
  END o[407]
  PIN o[408]
    DIRECTION OUTPUT ;
    USE SIGNAL ;
    PORT
      LAYER M4 ;
        RECT  0 81.456 0.084 81.48 ;
    END
  END o[408]
  PIN o[409]
    DIRECTION OUTPUT ;
    USE SIGNAL ;
    PORT
      LAYER M4 ;
        RECT  0 81.552 0.084 81.576 ;
    END
  END o[409]
  PIN o[40]
    DIRECTION OUTPUT ;
    USE SIGNAL ;
    PORT
      LAYER M4 ;
        RECT  0 38.448 0.084 38.472 ;
    END
  END o[40]
  PIN o[410]
    DIRECTION OUTPUT ;
    USE SIGNAL ;
    PORT
      LAYER M4 ;
        RECT  0 81.648 0.084 81.672 ;
    END
  END o[410]
  PIN o[411]
    DIRECTION OUTPUT ;
    USE SIGNAL ;
    PORT
      LAYER M4 ;
        RECT  0 81.744 0.084 81.768 ;
    END
  END o[411]
  PIN o[412]
    DIRECTION OUTPUT ;
    USE SIGNAL ;
    PORT
      LAYER M4 ;
        RECT  0 81.84 0.084 81.864 ;
    END
  END o[412]
  PIN o[413]
    DIRECTION OUTPUT ;
    USE SIGNAL ;
    PORT
      LAYER M4 ;
        RECT  0 81.936 0.084 81.96 ;
    END
  END o[413]
  PIN o[414]
    DIRECTION OUTPUT ;
    USE SIGNAL ;
    PORT
      LAYER M4 ;
        RECT  0 85.104 0.084 85.128 ;
    END
  END o[414]
  PIN o[415]
    DIRECTION OUTPUT ;
    USE SIGNAL ;
    PORT
      LAYER M4 ;
        RECT  0 85.2 0.084 85.224 ;
    END
  END o[415]
  PIN o[416]
    DIRECTION OUTPUT ;
    USE SIGNAL ;
    PORT
      LAYER M4 ;
        RECT  0 85.296 0.084 85.32 ;
    END
  END o[416]
  PIN o[417]
    DIRECTION OUTPUT ;
    USE SIGNAL ;
    PORT
      LAYER M4 ;
        RECT  0 85.392 0.084 85.416 ;
    END
  END o[417]
  PIN o[418]
    DIRECTION OUTPUT ;
    USE SIGNAL ;
    PORT
      LAYER M4 ;
        RECT  0 85.488 0.084 85.512 ;
    END
  END o[418]
  PIN o[419]
    DIRECTION OUTPUT ;
    USE SIGNAL ;
    PORT
      LAYER M4 ;
        RECT  0 85.584 0.084 85.608 ;
    END
  END o[419]
  PIN o[41]
    DIRECTION OUTPUT ;
    USE SIGNAL ;
    PORT
      LAYER M4 ;
        RECT  0 38.544 0.084 38.568 ;
    END
  END o[41]
  PIN o[420]
    DIRECTION OUTPUT ;
    USE SIGNAL ;
    PORT
      LAYER M4 ;
        RECT  0 85.68 0.084 85.704 ;
    END
  END o[420]
  PIN o[421]
    DIRECTION OUTPUT ;
    USE SIGNAL ;
    PORT
      LAYER M4 ;
        RECT  0 85.776 0.084 85.8 ;
    END
  END o[421]
  PIN o[422]
    DIRECTION OUTPUT ;
    USE SIGNAL ;
    PORT
      LAYER M4 ;
        RECT  0 85.872 0.084 85.896 ;
    END
  END o[422]
  PIN o[423]
    DIRECTION OUTPUT ;
    USE SIGNAL ;
    PORT
      LAYER M4 ;
        RECT  0 85.968 0.084 85.992 ;
    END
  END o[423]
  PIN o[424]
    DIRECTION OUTPUT ;
    USE SIGNAL ;
    PORT
      LAYER M4 ;
        RECT  0 86.064 0.084 86.088 ;
    END
  END o[424]
  PIN o[425]
    DIRECTION OUTPUT ;
    USE SIGNAL ;
    PORT
      LAYER M4 ;
        RECT  0 86.16 0.084 86.184 ;
    END
  END o[425]
  PIN o[426]
    DIRECTION OUTPUT ;
    USE SIGNAL ;
    PORT
      LAYER M4 ;
        RECT  0 86.256 0.084 86.28 ;
    END
  END o[426]
  PIN o[427]
    DIRECTION OUTPUT ;
    USE SIGNAL ;
    PORT
      LAYER M4 ;
        RECT  0 86.352 0.084 86.376 ;
    END
  END o[427]
  PIN o[428]
    DIRECTION OUTPUT ;
    USE SIGNAL ;
    PORT
      LAYER M4 ;
        RECT  0 86.448 0.084 86.472 ;
    END
  END o[428]
  PIN o[429]
    DIRECTION OUTPUT ;
    USE SIGNAL ;
    PORT
      LAYER M4 ;
        RECT  0 86.544 0.084 86.568 ;
    END
  END o[429]
  PIN o[42]
    DIRECTION OUTPUT ;
    USE SIGNAL ;
    PORT
      LAYER M4 ;
        RECT  0 38.64 0.084 38.664 ;
    END
  END o[42]
  PIN o[430]
    DIRECTION OUTPUT ;
    USE SIGNAL ;
    PORT
      LAYER M4 ;
        RECT  0 86.64 0.084 86.664 ;
    END
  END o[430]
  PIN o[431]
    DIRECTION OUTPUT ;
    USE SIGNAL ;
    PORT
      LAYER M4 ;
        RECT  0 86.736 0.084 86.76 ;
    END
  END o[431]
  PIN o[432]
    DIRECTION OUTPUT ;
    USE SIGNAL ;
    PORT
      LAYER M4 ;
        RECT  0 86.832 0.084 86.856 ;
    END
  END o[432]
  PIN o[433]
    DIRECTION OUTPUT ;
    USE SIGNAL ;
    PORT
      LAYER M4 ;
        RECT  0 86.928 0.084 86.952 ;
    END
  END o[433]
  PIN o[434]
    DIRECTION OUTPUT ;
    USE SIGNAL ;
    PORT
      LAYER M4 ;
        RECT  0 87.024 0.084 87.048 ;
    END
  END o[434]
  PIN o[435]
    DIRECTION OUTPUT ;
    USE SIGNAL ;
    PORT
      LAYER M4 ;
        RECT  0 87.12 0.084 87.144 ;
    END
  END o[435]
  PIN o[436]
    DIRECTION OUTPUT ;
    USE SIGNAL ;
    PORT
      LAYER M4 ;
        RECT  0 87.216 0.084 87.24 ;
    END
  END o[436]
  PIN o[437]
    DIRECTION OUTPUT ;
    USE SIGNAL ;
    PORT
      LAYER M4 ;
        RECT  0 87.312 0.084 87.336 ;
    END
  END o[437]
  PIN o[438]
    DIRECTION OUTPUT ;
    USE SIGNAL ;
    PORT
      LAYER M4 ;
        RECT  0 87.408 0.084 87.432 ;
    END
  END o[438]
  PIN o[439]
    DIRECTION OUTPUT ;
    USE SIGNAL ;
    PORT
      LAYER M4 ;
        RECT  0 87.504 0.084 87.528 ;
    END
  END o[439]
  PIN o[43]
    DIRECTION OUTPUT ;
    USE SIGNAL ;
    PORT
      LAYER M4 ;
        RECT  0 38.736 0.084 38.76 ;
    END
  END o[43]
  PIN o[440]
    DIRECTION OUTPUT ;
    USE SIGNAL ;
    PORT
      LAYER M4 ;
        RECT  0 87.6 0.084 87.624 ;
    END
  END o[440]
  PIN o[441]
    DIRECTION OUTPUT ;
    USE SIGNAL ;
    PORT
      LAYER M4 ;
        RECT  0 87.696 0.084 87.72 ;
    END
  END o[441]
  PIN o[442]
    DIRECTION OUTPUT ;
    USE SIGNAL ;
    PORT
      LAYER M4 ;
        RECT  0 87.792 0.084 87.816 ;
    END
  END o[442]
  PIN o[443]
    DIRECTION OUTPUT ;
    USE SIGNAL ;
    PORT
      LAYER M4 ;
        RECT  0 87.888 0.084 87.912 ;
    END
  END o[443]
  PIN o[444]
    DIRECTION OUTPUT ;
    USE SIGNAL ;
    PORT
      LAYER M4 ;
        RECT  0 87.984 0.084 88.008 ;
    END
  END o[444]
  PIN o[445]
    DIRECTION OUTPUT ;
    USE SIGNAL ;
    PORT
      LAYER M4 ;
        RECT  0 88.08 0.084 88.104 ;
    END
  END o[445]
  PIN o[446]
    DIRECTION OUTPUT ;
    USE SIGNAL ;
    PORT
      LAYER M4 ;
        RECT  0 75.888 0.084 75.912 ;
    END
  END o[446]
  PIN o[447]
    DIRECTION OUTPUT ;
    USE SIGNAL ;
    PORT
      LAYER M4 ;
        RECT  0 75.984 0.084 76.008 ;
    END
  END o[447]
  PIN o[448]
    DIRECTION OUTPUT ;
    USE SIGNAL ;
    PORT
      LAYER M4 ;
        RECT  0 76.08 0.084 76.104 ;
    END
  END o[448]
  PIN o[449]
    DIRECTION OUTPUT ;
    USE SIGNAL ;
    PORT
      LAYER M4 ;
        RECT  0 76.176 0.084 76.2 ;
    END
  END o[449]
  PIN o[44]
    DIRECTION OUTPUT ;
    USE SIGNAL ;
    PORT
      LAYER M4 ;
        RECT  0 38.832 0.084 38.856 ;
    END
  END o[44]
  PIN o[450]
    DIRECTION OUTPUT ;
    USE SIGNAL ;
    PORT
      LAYER M4 ;
        RECT  0 76.272 0.084 76.296 ;
    END
  END o[450]
  PIN o[451]
    DIRECTION OUTPUT ;
    USE SIGNAL ;
    PORT
      LAYER M4 ;
        RECT  0 76.368 0.084 76.392 ;
    END
  END o[451]
  PIN o[452]
    DIRECTION OUTPUT ;
    USE SIGNAL ;
    PORT
      LAYER M4 ;
        RECT  0 76.464 0.084 76.488 ;
    END
  END o[452]
  PIN o[453]
    DIRECTION OUTPUT ;
    USE SIGNAL ;
    PORT
      LAYER M4 ;
        RECT  0 76.56 0.084 76.584 ;
    END
  END o[453]
  PIN o[454]
    DIRECTION OUTPUT ;
    USE SIGNAL ;
    PORT
      LAYER M4 ;
        RECT  0 76.656 0.084 76.68 ;
    END
  END o[454]
  PIN o[455]
    DIRECTION OUTPUT ;
    USE SIGNAL ;
    PORT
      LAYER M4 ;
        RECT  0 76.752 0.084 76.776 ;
    END
  END o[455]
  PIN o[456]
    DIRECTION OUTPUT ;
    USE SIGNAL ;
    PORT
      LAYER M4 ;
        RECT  0 76.848 0.084 76.872 ;
    END
  END o[456]
  PIN o[457]
    DIRECTION OUTPUT ;
    USE SIGNAL ;
    PORT
      LAYER M4 ;
        RECT  0 76.944 0.084 76.968 ;
    END
  END o[457]
  PIN o[458]
    DIRECTION OUTPUT ;
    USE SIGNAL ;
    PORT
      LAYER M4 ;
        RECT  0 77.04 0.084 77.064 ;
    END
  END o[458]
  PIN o[459]
    DIRECTION OUTPUT ;
    USE SIGNAL ;
    PORT
      LAYER M4 ;
        RECT  0 77.136 0.084 77.16 ;
    END
  END o[459]
  PIN o[45]
    DIRECTION OUTPUT ;
    USE SIGNAL ;
    PORT
      LAYER M4 ;
        RECT  0 38.928 0.084 38.952 ;
    END
  END o[45]
  PIN o[460]
    DIRECTION OUTPUT ;
    USE SIGNAL ;
    PORT
      LAYER M4 ;
        RECT  0 77.232 0.084 77.256 ;
    END
  END o[460]
  PIN o[461]
    DIRECTION OUTPUT ;
    USE SIGNAL ;
    PORT
      LAYER M4 ;
        RECT  0 77.328 0.084 77.352 ;
    END
  END o[461]
  PIN o[462]
    DIRECTION OUTPUT ;
    USE SIGNAL ;
    PORT
      LAYER M4 ;
        RECT  0 77.424 0.084 77.448 ;
    END
  END o[462]
  PIN o[463]
    DIRECTION OUTPUT ;
    USE SIGNAL ;
    PORT
      LAYER M4 ;
        RECT  0 77.52 0.084 77.544 ;
    END
  END o[463]
  PIN o[464]
    DIRECTION OUTPUT ;
    USE SIGNAL ;
    PORT
      LAYER M4 ;
        RECT  0 77.616 0.084 77.64 ;
    END
  END o[464]
  PIN o[465]
    DIRECTION OUTPUT ;
    USE SIGNAL ;
    PORT
      LAYER M4 ;
        RECT  0 77.712 0.084 77.736 ;
    END
  END o[465]
  PIN o[466]
    DIRECTION OUTPUT ;
    USE SIGNAL ;
    PORT
      LAYER M4 ;
        RECT  0 77.808 0.084 77.832 ;
    END
  END o[466]
  PIN o[467]
    DIRECTION OUTPUT ;
    USE SIGNAL ;
    PORT
      LAYER M4 ;
        RECT  0 77.904 0.084 77.928 ;
    END
  END o[467]
  PIN o[468]
    DIRECTION OUTPUT ;
    USE SIGNAL ;
    PORT
      LAYER M4 ;
        RECT  0 78 0.084 78.024 ;
    END
  END o[468]
  PIN o[469]
    DIRECTION OUTPUT ;
    USE SIGNAL ;
    PORT
      LAYER M4 ;
        RECT  0 78.096 0.084 78.12 ;
    END
  END o[469]
  PIN o[46]
    DIRECTION OUTPUT ;
    USE SIGNAL ;
    PORT
      LAYER M4 ;
        RECT  0 39.024 0.084 39.048 ;
    END
  END o[46]
  PIN o[470]
    DIRECTION OUTPUT ;
    USE SIGNAL ;
    PORT
      LAYER M4 ;
        RECT  0 78.192 0.084 78.216 ;
    END
  END o[470]
  PIN o[471]
    DIRECTION OUTPUT ;
    USE SIGNAL ;
    PORT
      LAYER M4 ;
        RECT  0 78.288 0.084 78.312 ;
    END
  END o[471]
  PIN o[472]
    DIRECTION OUTPUT ;
    USE SIGNAL ;
    PORT
      LAYER M4 ;
        RECT  0 78.384 0.084 78.408 ;
    END
  END o[472]
  PIN o[473]
    DIRECTION OUTPUT ;
    USE SIGNAL ;
    PORT
      LAYER M4 ;
        RECT  0 78.48 0.084 78.504 ;
    END
  END o[473]
  PIN o[474]
    DIRECTION OUTPUT ;
    USE SIGNAL ;
    PORT
      LAYER M4 ;
        RECT  0 78.576 0.084 78.6 ;
    END
  END o[474]
  PIN o[475]
    DIRECTION OUTPUT ;
    USE SIGNAL ;
    PORT
      LAYER M4 ;
        RECT  0 78.672 0.084 78.696 ;
    END
  END o[475]
  PIN o[476]
    DIRECTION OUTPUT ;
    USE SIGNAL ;
    PORT
      LAYER M4 ;
        RECT  0 78.768 0.084 78.792 ;
    END
  END o[476]
  PIN o[477]
    DIRECTION OUTPUT ;
    USE SIGNAL ;
    PORT
      LAYER M4 ;
        RECT  0 78.864 0.084 78.888 ;
    END
  END o[477]
  PIN o[478]
    DIRECTION OUTPUT ;
    USE SIGNAL ;
    PORT
      LAYER M4 ;
        RECT  0 56.688 0.084 56.712 ;
    END
  END o[478]
  PIN o[479]
    DIRECTION OUTPUT ;
    USE SIGNAL ;
    PORT
      LAYER M4 ;
        RECT  0 56.784 0.084 56.808 ;
    END
  END o[479]
  PIN o[47]
    DIRECTION OUTPUT ;
    USE SIGNAL ;
    PORT
      LAYER M4 ;
        RECT  0 39.12 0.084 39.144 ;
    END
  END o[47]
  PIN o[480]
    DIRECTION OUTPUT ;
    USE SIGNAL ;
    PORT
      LAYER M4 ;
        RECT  0 56.88 0.084 56.904 ;
    END
  END o[480]
  PIN o[481]
    DIRECTION OUTPUT ;
    USE SIGNAL ;
    PORT
      LAYER M4 ;
        RECT  0 56.976 0.084 57 ;
    END
  END o[481]
  PIN o[482]
    DIRECTION OUTPUT ;
    USE SIGNAL ;
    PORT
      LAYER M4 ;
        RECT  0 57.072 0.084 57.096 ;
    END
  END o[482]
  PIN o[483]
    DIRECTION OUTPUT ;
    USE SIGNAL ;
    PORT
      LAYER M4 ;
        RECT  0 57.168 0.084 57.192 ;
    END
  END o[483]
  PIN o[484]
    DIRECTION OUTPUT ;
    USE SIGNAL ;
    PORT
      LAYER M4 ;
        RECT  0 57.264 0.084 57.288 ;
    END
  END o[484]
  PIN o[485]
    DIRECTION OUTPUT ;
    USE SIGNAL ;
    PORT
      LAYER M4 ;
        RECT  0 57.36 0.084 57.384 ;
    END
  END o[485]
  PIN o[486]
    DIRECTION OUTPUT ;
    USE SIGNAL ;
    PORT
      LAYER M4 ;
        RECT  0 57.456 0.084 57.48 ;
    END
  END o[486]
  PIN o[487]
    DIRECTION OUTPUT ;
    USE SIGNAL ;
    PORT
      LAYER M4 ;
        RECT  0 57.552 0.084 57.576 ;
    END
  END o[487]
  PIN o[488]
    DIRECTION OUTPUT ;
    USE SIGNAL ;
    PORT
      LAYER M4 ;
        RECT  0 57.648 0.084 57.672 ;
    END
  END o[488]
  PIN o[489]
    DIRECTION OUTPUT ;
    USE SIGNAL ;
    PORT
      LAYER M4 ;
        RECT  0 57.744 0.084 57.768 ;
    END
  END o[489]
  PIN o[48]
    DIRECTION OUTPUT ;
    USE SIGNAL ;
    PORT
      LAYER M4 ;
        RECT  0 39.216 0.084 39.24 ;
    END
  END o[48]
  PIN o[490]
    DIRECTION OUTPUT ;
    USE SIGNAL ;
    PORT
      LAYER M4 ;
        RECT  0 57.84 0.084 57.864 ;
    END
  END o[490]
  PIN o[491]
    DIRECTION OUTPUT ;
    USE SIGNAL ;
    PORT
      LAYER M4 ;
        RECT  0 57.936 0.084 57.96 ;
    END
  END o[491]
  PIN o[492]
    DIRECTION OUTPUT ;
    USE SIGNAL ;
    PORT
      LAYER M4 ;
        RECT  0 58.032 0.084 58.056 ;
    END
  END o[492]
  PIN o[493]
    DIRECTION OUTPUT ;
    USE SIGNAL ;
    PORT
      LAYER M4 ;
        RECT  0 58.128 0.084 58.152 ;
    END
  END o[493]
  PIN o[494]
    DIRECTION OUTPUT ;
    USE SIGNAL ;
    PORT
      LAYER M4 ;
        RECT  0 58.224 0.084 58.248 ;
    END
  END o[494]
  PIN o[495]
    DIRECTION OUTPUT ;
    USE SIGNAL ;
    PORT
      LAYER M4 ;
        RECT  0 58.32 0.084 58.344 ;
    END
  END o[495]
  PIN o[496]
    DIRECTION OUTPUT ;
    USE SIGNAL ;
    PORT
      LAYER M4 ;
        RECT  0 58.416 0.084 58.44 ;
    END
  END o[496]
  PIN o[497]
    DIRECTION OUTPUT ;
    USE SIGNAL ;
    PORT
      LAYER M4 ;
        RECT  0 58.512 0.084 58.536 ;
    END
  END o[497]
  PIN o[498]
    DIRECTION OUTPUT ;
    USE SIGNAL ;
    PORT
      LAYER M4 ;
        RECT  0 58.608 0.084 58.632 ;
    END
  END o[498]
  PIN o[499]
    DIRECTION OUTPUT ;
    USE SIGNAL ;
    PORT
      LAYER M4 ;
        RECT  0 58.704 0.084 58.728 ;
    END
  END o[499]
  PIN o[49]
    DIRECTION OUTPUT ;
    USE SIGNAL ;
    PORT
      LAYER M4 ;
        RECT  0 39.312 0.084 39.336 ;
    END
  END o[49]
  PIN o[4]
    DIRECTION OUTPUT ;
    USE SIGNAL ;
    PORT
      LAYER M4 ;
        RECT  0 50.352 0.084 50.376 ;
    END
  END o[4]
  PIN o[500]
    DIRECTION OUTPUT ;
    USE SIGNAL ;
    PORT
      LAYER M4 ;
        RECT  0 58.8 0.084 58.824 ;
    END
  END o[500]
  PIN o[501]
    DIRECTION OUTPUT ;
    USE SIGNAL ;
    PORT
      LAYER M4 ;
        RECT  0 58.896 0.084 58.92 ;
    END
  END o[501]
  PIN o[502]
    DIRECTION OUTPUT ;
    USE SIGNAL ;
    PORT
      LAYER M4 ;
        RECT  0 58.992 0.084 59.016 ;
    END
  END o[502]
  PIN o[503]
    DIRECTION OUTPUT ;
    USE SIGNAL ;
    PORT
      LAYER M4 ;
        RECT  0 59.088 0.084 59.112 ;
    END
  END o[503]
  PIN o[504]
    DIRECTION OUTPUT ;
    USE SIGNAL ;
    PORT
      LAYER M4 ;
        RECT  0 59.184 0.084 59.208 ;
    END
  END o[504]
  PIN o[505]
    DIRECTION OUTPUT ;
    USE SIGNAL ;
    PORT
      LAYER M4 ;
        RECT  0 59.28 0.084 59.304 ;
    END
  END o[505]
  PIN o[506]
    DIRECTION OUTPUT ;
    USE SIGNAL ;
    PORT
      LAYER M4 ;
        RECT  0 59.376 0.084 59.4 ;
    END
  END o[506]
  PIN o[507]
    DIRECTION OUTPUT ;
    USE SIGNAL ;
    PORT
      LAYER M4 ;
        RECT  0 59.472 0.084 59.496 ;
    END
  END o[507]
  PIN o[508]
    DIRECTION OUTPUT ;
    USE SIGNAL ;
    PORT
      LAYER M4 ;
        RECT  0 59.568 0.084 59.592 ;
    END
  END o[508]
  PIN o[509]
    DIRECTION OUTPUT ;
    USE SIGNAL ;
    PORT
      LAYER M4 ;
        RECT  0 59.664 0.084 59.688 ;
    END
  END o[509]
  PIN o[50]
    DIRECTION OUTPUT ;
    USE SIGNAL ;
    PORT
      LAYER M4 ;
        RECT  0 39.408 0.084 39.432 ;
    END
  END o[50]
  PIN o[510]
    DIRECTION OUTPUT ;
    USE SIGNAL ;
    PORT
      LAYER M4 ;
        RECT  0 49.584 0.084 49.608 ;
    END
  END o[510]
  PIN o[511]
    DIRECTION OUTPUT ;
    USE SIGNAL ;
    PORT
      LAYER M4 ;
        RECT  0 49.68 0.084 49.704 ;
    END
  END o[511]
  PIN o[51]
    DIRECTION OUTPUT ;
    USE SIGNAL ;
    PORT
      LAYER M4 ;
        RECT  0 39.504 0.084 39.528 ;
    END
  END o[51]
  PIN o[52]
    DIRECTION OUTPUT ;
    USE SIGNAL ;
    PORT
      LAYER M4 ;
        RECT  0 39.6 0.084 39.624 ;
    END
  END o[52]
  PIN o[53]
    DIRECTION OUTPUT ;
    USE SIGNAL ;
    PORT
      LAYER M4 ;
        RECT  0 39.696 0.084 39.72 ;
    END
  END o[53]
  PIN o[54]
    DIRECTION OUTPUT ;
    USE SIGNAL ;
    PORT
      LAYER M4 ;
        RECT  0 39.792 0.084 39.816 ;
    END
  END o[54]
  PIN o[55]
    DIRECTION OUTPUT ;
    USE SIGNAL ;
    PORT
      LAYER M4 ;
        RECT  0 39.888 0.084 39.912 ;
    END
  END o[55]
  PIN o[56]
    DIRECTION OUTPUT ;
    USE SIGNAL ;
    PORT
      LAYER M4 ;
        RECT  0 39.984 0.084 40.008 ;
    END
  END o[56]
  PIN o[57]
    DIRECTION OUTPUT ;
    USE SIGNAL ;
    PORT
      LAYER M4 ;
        RECT  0 40.08 0.084 40.104 ;
    END
  END o[57]
  PIN o[58]
    DIRECTION OUTPUT ;
    USE SIGNAL ;
    PORT
      LAYER M4 ;
        RECT  0 40.176 0.084 40.2 ;
    END
  END o[58]
  PIN o[59]
    DIRECTION OUTPUT ;
    USE SIGNAL ;
    PORT
      LAYER M4 ;
        RECT  0 40.272 0.084 40.296 ;
    END
  END o[59]
  PIN o[5]
    DIRECTION OUTPUT ;
    USE SIGNAL ;
    PORT
      LAYER M4 ;
        RECT  0 50.448 0.084 50.472 ;
    END
  END o[5]
  PIN o[60]
    DIRECTION OUTPUT ;
    USE SIGNAL ;
    PORT
      LAYER M4 ;
        RECT  0 40.368 0.084 40.392 ;
    END
  END o[60]
  PIN o[61]
    DIRECTION OUTPUT ;
    USE SIGNAL ;
    PORT
      LAYER M4 ;
        RECT  0 40.464 0.084 40.488 ;
    END
  END o[61]
  PIN o[62]
    DIRECTION OUTPUT ;
    USE SIGNAL ;
    PORT
      LAYER M4 ;
        RECT  0 24.432 0.084 24.456 ;
    END
  END o[62]
  PIN o[63]
    DIRECTION OUTPUT ;
    USE SIGNAL ;
    PORT
      LAYER M4 ;
        RECT  0 24.528 0.084 24.552 ;
    END
  END o[63]
  PIN o[64]
    DIRECTION OUTPUT ;
    USE SIGNAL ;
    PORT
      LAYER M4 ;
        RECT  0 24.624 0.084 24.648 ;
    END
  END o[64]
  PIN o[65]
    DIRECTION OUTPUT ;
    USE SIGNAL ;
    PORT
      LAYER M4 ;
        RECT  0 24.72 0.084 24.744 ;
    END
  END o[65]
  PIN o[66]
    DIRECTION OUTPUT ;
    USE SIGNAL ;
    PORT
      LAYER M4 ;
        RECT  0 24.816 0.084 24.84 ;
    END
  END o[66]
  PIN o[67]
    DIRECTION OUTPUT ;
    USE SIGNAL ;
    PORT
      LAYER M4 ;
        RECT  0 24.912 0.084 24.936 ;
    END
  END o[67]
  PIN o[68]
    DIRECTION OUTPUT ;
    USE SIGNAL ;
    PORT
      LAYER M4 ;
        RECT  0 25.008 0.084 25.032 ;
    END
  END o[68]
  PIN o[69]
    DIRECTION OUTPUT ;
    USE SIGNAL ;
    PORT
      LAYER M4 ;
        RECT  0 25.104 0.084 25.128 ;
    END
  END o[69]
  PIN o[6]
    DIRECTION OUTPUT ;
    USE SIGNAL ;
    PORT
      LAYER M4 ;
        RECT  0 50.544 0.084 50.568 ;
    END
  END o[6]
  PIN o[70]
    DIRECTION OUTPUT ;
    USE SIGNAL ;
    PORT
      LAYER M4 ;
        RECT  0 25.2 0.084 25.224 ;
    END
  END o[70]
  PIN o[71]
    DIRECTION OUTPUT ;
    USE SIGNAL ;
    PORT
      LAYER M4 ;
        RECT  0 25.296 0.084 25.32 ;
    END
  END o[71]
  PIN o[72]
    DIRECTION OUTPUT ;
    USE SIGNAL ;
    PORT
      LAYER M4 ;
        RECT  0 25.392 0.084 25.416 ;
    END
  END o[72]
  PIN o[73]
    DIRECTION OUTPUT ;
    USE SIGNAL ;
    PORT
      LAYER M4 ;
        RECT  0 25.488 0.084 25.512 ;
    END
  END o[73]
  PIN o[74]
    DIRECTION OUTPUT ;
    USE SIGNAL ;
    PORT
      LAYER M4 ;
        RECT  0 25.584 0.084 25.608 ;
    END
  END o[74]
  PIN o[75]
    DIRECTION OUTPUT ;
    USE SIGNAL ;
    PORT
      LAYER M4 ;
        RECT  0 25.68 0.084 25.704 ;
    END
  END o[75]
  PIN o[76]
    DIRECTION OUTPUT ;
    USE SIGNAL ;
    PORT
      LAYER M4 ;
        RECT  0 25.776 0.084 25.8 ;
    END
  END o[76]
  PIN o[77]
    DIRECTION OUTPUT ;
    USE SIGNAL ;
    PORT
      LAYER M4 ;
        RECT  0 25.872 0.084 25.896 ;
    END
  END o[77]
  PIN o[78]
    DIRECTION OUTPUT ;
    USE SIGNAL ;
    PORT
      LAYER M4 ;
        RECT  0 25.968 0.084 25.992 ;
    END
  END o[78]
  PIN o[79]
    DIRECTION OUTPUT ;
    USE SIGNAL ;
    PORT
      LAYER M4 ;
        RECT  0 26.064 0.084 26.088 ;
    END
  END o[79]
  PIN o[7]
    DIRECTION OUTPUT ;
    USE SIGNAL ;
    PORT
      LAYER M4 ;
        RECT  0 50.64 0.084 50.664 ;
    END
  END o[7]
  PIN o[80]
    DIRECTION OUTPUT ;
    USE SIGNAL ;
    PORT
      LAYER M4 ;
        RECT  0 26.16 0.084 26.184 ;
    END
  END o[80]
  PIN o[81]
    DIRECTION OUTPUT ;
    USE SIGNAL ;
    PORT
      LAYER M4 ;
        RECT  0 26.256 0.084 26.28 ;
    END
  END o[81]
  PIN o[82]
    DIRECTION OUTPUT ;
    USE SIGNAL ;
    PORT
      LAYER M4 ;
        RECT  0 26.352 0.084 26.376 ;
    END
  END o[82]
  PIN o[83]
    DIRECTION OUTPUT ;
    USE SIGNAL ;
    PORT
      LAYER M4 ;
        RECT  0 26.448 0.084 26.472 ;
    END
  END o[83]
  PIN o[84]
    DIRECTION OUTPUT ;
    USE SIGNAL ;
    PORT
      LAYER M4 ;
        RECT  0 26.544 0.084 26.568 ;
    END
  END o[84]
  PIN o[85]
    DIRECTION OUTPUT ;
    USE SIGNAL ;
    PORT
      LAYER M4 ;
        RECT  0 26.64 0.084 26.664 ;
    END
  END o[85]
  PIN o[86]
    DIRECTION OUTPUT ;
    USE SIGNAL ;
    PORT
      LAYER M4 ;
        RECT  0 26.736 0.084 26.76 ;
    END
  END o[86]
  PIN o[87]
    DIRECTION OUTPUT ;
    USE SIGNAL ;
    PORT
      LAYER M4 ;
        RECT  0 26.832 0.084 26.856 ;
    END
  END o[87]
  PIN o[88]
    DIRECTION OUTPUT ;
    USE SIGNAL ;
    PORT
      LAYER M4 ;
        RECT  0 26.928 0.084 26.952 ;
    END
  END o[88]
  PIN o[89]
    DIRECTION OUTPUT ;
    USE SIGNAL ;
    PORT
      LAYER M4 ;
        RECT  0 27.024 0.084 27.048 ;
    END
  END o[89]
  PIN o[8]
    DIRECTION OUTPUT ;
    USE SIGNAL ;
    PORT
      LAYER M4 ;
        RECT  0 50.736 0.084 50.76 ;
    END
  END o[8]
  PIN o[90]
    DIRECTION OUTPUT ;
    USE SIGNAL ;
    PORT
      LAYER M4 ;
        RECT  0 27.12 0.084 27.144 ;
    END
  END o[90]
  PIN o[91]
    DIRECTION OUTPUT ;
    USE SIGNAL ;
    PORT
      LAYER M4 ;
        RECT  0 27.216 0.084 27.24 ;
    END
  END o[91]
  PIN o[92]
    DIRECTION OUTPUT ;
    USE SIGNAL ;
    PORT
      LAYER M4 ;
        RECT  0 27.312 0.084 27.336 ;
    END
  END o[92]
  PIN o[93]
    DIRECTION OUTPUT ;
    USE SIGNAL ;
    PORT
      LAYER M4 ;
        RECT  0 27.408 0.084 27.432 ;
    END
  END o[93]
  PIN o[94]
    DIRECTION OUTPUT ;
    USE SIGNAL ;
    PORT
      LAYER M4 ;
        RECT  0 18.288 0.084 18.312 ;
    END
  END o[94]
  PIN o[95]
    DIRECTION OUTPUT ;
    USE SIGNAL ;
    PORT
      LAYER M4 ;
        RECT  0 18.384 0.084 18.408 ;
    END
  END o[95]
  PIN o[96]
    DIRECTION OUTPUT ;
    USE SIGNAL ;
    PORT
      LAYER M4 ;
        RECT  0 18.48 0.084 18.504 ;
    END
  END o[96]
  PIN o[97]
    DIRECTION OUTPUT ;
    USE SIGNAL ;
    PORT
      LAYER M4 ;
        RECT  0 18.576 0.084 18.6 ;
    END
  END o[97]
  PIN o[98]
    DIRECTION OUTPUT ;
    USE SIGNAL ;
    PORT
      LAYER M4 ;
        RECT  0 18.672 0.084 18.696 ;
    END
  END o[98]
  PIN o[99]
    DIRECTION OUTPUT ;
    USE SIGNAL ;
    PORT
      LAYER M4 ;
        RECT  0 18.768 0.084 18.792 ;
    END
  END o[99]
  PIN o[9]
    DIRECTION OUTPUT ;
    USE SIGNAL ;
    PORT
      LAYER M4 ;
        RECT  0 50.832 0.084 50.856 ;
    END
  END o[9]
  PIN rs
    DIRECTION INPUT ;
    USE SIGNAL ;
    PORT
      LAYER M5 ;
        RECT  11.184 94.956 11.208 95.04 ;
    END
  END rs
  PIN VDD
    DIRECTION INOUT ;
    USE POWER ;
    PORT
      LAYER M5 ;
        RECT  34.992 2.151 35.112 92.889 ;
        RECT  32.292 2.151 32.412 92.889 ;
        RECT  29.592 2.151 29.712 92.889 ;
        RECT  26.892 2.151 27.012 92.889 ;
        RECT  24.192 2.151 24.312 92.889 ;
        RECT  21.492 2.151 21.612 92.889 ;
        RECT  18.792 2.151 18.912 92.889 ;
        RECT  16.092 2.151 16.212 92.889 ;
        RECT  13.392 2.151 13.512 92.889 ;
        RECT  10.692 2.151 10.812 92.889 ;
        RECT  7.992 2.151 8.112 92.889 ;
        RECT  5.292 2.151 5.412 92.889 ;
        RECT  2.592 2.151 2.712 92.889 ;
    END
  END VDD
  PIN VSS
    DIRECTION INOUT ;
    USE GROUND ;
    PORT
      LAYER M5 ;
        RECT  34.8 2.137 34.92 92.903 ;
        RECT  32.1 2.137 32.22 92.903 ;
        RECT  29.4 2.137 29.52 92.903 ;
        RECT  26.7 2.137 26.82 92.903 ;
        RECT  24 2.137 24.12 92.903 ;
        RECT  21.3 2.137 21.42 92.903 ;
        RECT  18.6 2.137 18.72 92.903 ;
        RECT  15.9 2.137 16.02 92.903 ;
        RECT  13.2 2.137 13.32 92.903 ;
        RECT  10.5 2.137 10.62 92.903 ;
        RECT  7.8 2.137 7.92 92.903 ;
        RECT  5.1 2.137 5.22 92.903 ;
        RECT  2.4 2.137 2.52 92.903 ;
    END
  END VSS
  OBS
    LAYER RVTN ;
     RECT  2.16 2.16 36.72 2.295 ;
     RECT  2.16 2.565 36.72 2.835 ;
     RECT  2.16 3.105 36.72 3.375 ;
     RECT  2.16 3.645 36.72 3.915 ;
     RECT  2.16 4.185 36.72 4.455 ;
     RECT  2.16 4.725 36.72 4.995 ;
     RECT  2.16 5.265 36.72 5.535 ;
     RECT  2.16 5.805 36.72 6.075 ;
     RECT  2.16 6.345 36.72 6.615 ;
     RECT  2.16 6.885 36.72 7.155 ;
     RECT  2.16 7.425 36.72 7.695 ;
     RECT  2.16 7.965 36.72 8.235 ;
     RECT  2.16 8.505 36.72 8.775 ;
     RECT  2.16 9.045 36.72 9.315 ;
     RECT  2.16 9.585 36.72 9.855 ;
     RECT  2.16 10.125 36.72 10.395 ;
     RECT  2.16 10.665 36.72 10.935 ;
     RECT  2.16 11.205 36.72 11.475 ;
     RECT  2.16 11.745 36.72 12.015 ;
     RECT  2.16 12.285 36.72 12.555 ;
     RECT  2.16 12.825 36.72 13.095 ;
     RECT  2.16 13.365 36.72 13.635 ;
     RECT  2.16 13.905 36.72 14.175 ;
     RECT  2.16 14.445 36.72 14.715 ;
     RECT  2.16 14.985 36.72 15.255 ;
     RECT  2.16 15.525 36.72 15.795 ;
     RECT  2.16 16.065 36.72 16.335 ;
     RECT  2.16 16.605 36.72 16.875 ;
     RECT  2.16 17.145 36.72 17.415 ;
     RECT  2.16 17.685 36.72 17.955 ;
     RECT  2.16 18.225 36.72 18.495 ;
     RECT  2.16 18.765 36.72 19.035 ;
     RECT  2.16 19.305 36.72 19.575 ;
     RECT  2.16 19.845 36.72 20.115 ;
     RECT  2.16 20.385 36.72 20.655 ;
     RECT  2.16 20.925 36.72 21.195 ;
     RECT  2.16 21.465 36.72 21.735 ;
     RECT  2.16 22.005 36.72 22.275 ;
     RECT  2.16 22.545 36.72 22.815 ;
     RECT  2.16 23.085 36.72 23.355 ;
     RECT  2.16 23.625 36.72 23.895 ;
     RECT  2.16 24.165 36.72 24.435 ;
     RECT  2.16 24.705 36.72 24.975 ;
     RECT  2.16 25.245 36.72 25.515 ;
     RECT  2.16 25.785 36.72 26.055 ;
     RECT  2.16 26.325 36.72 26.595 ;
     RECT  2.16 26.865 36.72 27.135 ;
     RECT  2.16 27.405 36.72 27.675 ;
     RECT  2.16 27.945 36.72 28.215 ;
     RECT  2.16 28.485 36.72 28.755 ;
     RECT  2.16 29.025 36.72 29.295 ;
     RECT  2.16 29.565 36.72 29.835 ;
     RECT  2.16 30.105 36.72 30.375 ;
     RECT  2.16 30.645 36.72 30.915 ;
     RECT  2.16 31.185 36.72 31.455 ;
     RECT  2.16 31.725 36.72 31.995 ;
     RECT  2.16 32.265 36.72 32.535 ;
     RECT  2.16 32.805 36.72 33.075 ;
     RECT  2.16 33.345 36.72 33.615 ;
     RECT  2.16 33.885 36.72 34.155 ;
     RECT  2.16 34.425 36.72 34.695 ;
     RECT  2.16 34.965 36.72 35.235 ;
     RECT  2.16 35.505 36.72 35.775 ;
     RECT  2.16 36.045 36.72 36.315 ;
     RECT  2.16 36.585 36.72 36.855 ;
     RECT  2.16 37.125 36.72 37.395 ;
     RECT  2.16 37.665 36.72 37.935 ;
     RECT  2.16 38.205 36.72 38.475 ;
     RECT  2.16 38.745 36.72 39.015 ;
     RECT  2.16 39.285 36.72 39.555 ;
     RECT  2.16 39.825 36.72 40.095 ;
     RECT  2.16 40.365 36.72 40.635 ;
     RECT  2.16 40.905 36.72 41.175 ;
     RECT  2.16 41.445 36.72 41.715 ;
     RECT  2.16 41.985 36.72 42.255 ;
     RECT  2.16 42.525 36.72 42.795 ;
     RECT  2.16 43.065 36.72 43.335 ;
     RECT  2.16 43.605 36.72 43.875 ;
     RECT  2.16 44.145 36.72 44.415 ;
     RECT  2.16 44.685 36.72 44.955 ;
     RECT  2.16 45.225 36.72 45.495 ;
     RECT  2.16 45.765 36.72 46.035 ;
     RECT  2.16 46.305 36.72 46.575 ;
     RECT  2.16 46.845 36.72 47.115 ;
     RECT  2.16 47.385 36.72 47.655 ;
     RECT  2.16 47.925 36.72 48.195 ;
     RECT  2.16 48.465 36.72 48.735 ;
     RECT  2.16 49.005 36.72 49.275 ;
     RECT  2.16 49.545 36.72 49.815 ;
     RECT  2.16 50.085 36.72 50.355 ;
     RECT  2.16 50.625 36.72 50.895 ;
     RECT  2.16 51.165 36.72 51.435 ;
     RECT  2.16 51.705 36.72 51.975 ;
     RECT  2.16 52.245 36.72 52.515 ;
     RECT  2.16 52.785 36.72 53.055 ;
     RECT  2.16 53.325 36.72 53.595 ;
     RECT  2.16 53.865 36.72 54.135 ;
     RECT  2.16 54.405 36.72 54.675 ;
     RECT  2.16 54.945 36.72 55.215 ;
     RECT  2.16 55.485 36.72 55.755 ;
     RECT  2.16 56.025 36.72 56.295 ;
     RECT  2.16 56.565 36.72 56.835 ;
     RECT  2.16 57.105 36.72 57.375 ;
     RECT  2.16 57.645 36.72 57.915 ;
     RECT  2.16 58.185 36.72 58.455 ;
     RECT  2.16 58.725 36.72 58.995 ;
     RECT  2.16 59.265 36.72 59.535 ;
     RECT  2.16 59.805 36.72 60.075 ;
     RECT  2.16 60.345 36.72 60.615 ;
     RECT  2.16 60.885 36.72 61.155 ;
     RECT  2.16 61.425 36.72 61.695 ;
     RECT  2.16 61.965 36.72 62.235 ;
     RECT  2.16 62.505 36.72 62.775 ;
     RECT  2.16 63.045 36.72 63.315 ;
     RECT  2.16 63.585 36.72 63.855 ;
     RECT  2.16 64.125 36.72 64.395 ;
     RECT  2.16 64.665 36.72 64.935 ;
     RECT  2.16 65.205 36.72 65.475 ;
     RECT  2.16 65.745 36.72 66.015 ;
     RECT  2.16 66.285 36.72 66.555 ;
     RECT  2.16 66.825 36.72 67.095 ;
     RECT  2.16 67.365 36.72 67.635 ;
     RECT  2.16 67.905 36.72 68.175 ;
     RECT  2.16 68.445 36.72 68.715 ;
     RECT  2.16 68.985 36.72 69.255 ;
     RECT  2.16 69.525 36.72 69.795 ;
     RECT  2.16 70.065 36.72 70.335 ;
     RECT  2.16 70.605 36.72 70.875 ;
     RECT  2.16 71.145 36.72 71.415 ;
     RECT  2.16 71.685 36.72 71.955 ;
     RECT  2.16 72.225 36.72 72.495 ;
     RECT  2.16 72.765 36.72 73.035 ;
     RECT  2.16 73.305 36.72 73.575 ;
     RECT  2.16 73.845 36.72 74.115 ;
     RECT  2.16 74.385 36.72 74.655 ;
     RECT  2.16 74.925 36.72 75.195 ;
     RECT  2.16 75.465 36.72 75.735 ;
     RECT  2.16 76.005 36.72 76.275 ;
     RECT  2.16 76.545 36.72 76.815 ;
     RECT  2.16 77.085 36.72 77.355 ;
     RECT  2.16 77.625 36.72 77.895 ;
     RECT  2.16 78.165 36.72 78.435 ;
     RECT  2.16 78.705 36.72 78.975 ;
     RECT  2.16 79.245 36.72 79.515 ;
     RECT  2.16 79.785 36.72 80.055 ;
     RECT  2.16 80.325 36.72 80.595 ;
     RECT  2.16 80.865 36.72 81.135 ;
     RECT  2.16 81.405 36.72 81.675 ;
     RECT  2.16 81.945 36.72 82.215 ;
     RECT  2.16 82.485 36.72 82.755 ;
     RECT  2.16 83.025 36.72 83.295 ;
     RECT  2.16 83.565 36.72 83.835 ;
     RECT  2.16 84.105 36.72 84.375 ;
     RECT  2.16 84.645 36.72 84.915 ;
     RECT  2.16 85.185 36.72 85.455 ;
     RECT  2.16 85.725 36.72 85.995 ;
     RECT  2.16 86.265 36.72 86.535 ;
     RECT  2.16 86.805 36.72 87.075 ;
     RECT  2.16 87.345 36.72 87.615 ;
     RECT  2.16 87.885 36.72 88.155 ;
     RECT  2.16 88.425 36.72 88.695 ;
     RECT  2.16 88.965 36.72 89.235 ;
     RECT  2.16 89.505 36.72 89.775 ;
     RECT  2.16 90.045 36.72 90.315 ;
     RECT  2.16 90.585 36.72 90.855 ;
     RECT  2.16 91.125 36.72 91.395 ;
     RECT  2.16 91.665 36.72 91.935 ;
     RECT  2.16 92.205 36.72 92.475 ;
     RECT  2.16 92.745 36.72 92.88 ;
    LAYER RVTP ;
     RECT  2.16 2.295 36.72 2.565 ;
     RECT  2.16 2.835 36.72 3.105 ;
     RECT  2.16 3.375 36.72 3.645 ;
     RECT  2.16 3.915 36.72 4.185 ;
     RECT  2.16 4.455 36.72 4.725 ;
     RECT  2.16 4.995 36.72 5.265 ;
     RECT  2.16 5.535 36.72 5.805 ;
     RECT  2.16 6.075 36.72 6.345 ;
     RECT  2.16 6.615 36.72 6.885 ;
     RECT  2.16 7.155 36.72 7.425 ;
     RECT  2.16 7.695 36.72 7.965 ;
     RECT  2.16 8.235 36.72 8.505 ;
     RECT  2.16 8.775 36.72 9.045 ;
     RECT  2.16 9.315 36.72 9.585 ;
     RECT  2.16 9.855 36.72 10.125 ;
     RECT  2.16 10.395 36.72 10.665 ;
     RECT  2.16 10.935 36.72 11.205 ;
     RECT  2.16 11.475 36.72 11.745 ;
     RECT  2.16 12.015 36.72 12.285 ;
     RECT  2.16 12.555 36.72 12.825 ;
     RECT  2.16 13.095 36.72 13.365 ;
     RECT  2.16 13.635 36.72 13.905 ;
     RECT  2.16 14.175 36.72 14.445 ;
     RECT  2.16 14.715 36.72 14.985 ;
     RECT  2.16 15.255 36.72 15.525 ;
     RECT  2.16 15.795 36.72 16.065 ;
     RECT  2.16 16.335 36.72 16.605 ;
     RECT  2.16 16.875 36.72 17.145 ;
     RECT  2.16 17.415 36.72 17.685 ;
     RECT  2.16 17.955 36.72 18.225 ;
     RECT  2.16 18.495 36.72 18.765 ;
     RECT  2.16 19.035 36.72 19.305 ;
     RECT  2.16 19.575 36.72 19.845 ;
     RECT  2.16 20.115 36.72 20.385 ;
     RECT  2.16 20.655 36.72 20.925 ;
     RECT  2.16 21.195 36.72 21.465 ;
     RECT  2.16 21.735 36.72 22.005 ;
     RECT  2.16 22.275 36.72 22.545 ;
     RECT  2.16 22.815 36.72 23.085 ;
     RECT  2.16 23.355 36.72 23.625 ;
     RECT  2.16 23.895 36.72 24.165 ;
     RECT  2.16 24.435 36.72 24.705 ;
     RECT  2.16 24.975 36.72 25.245 ;
     RECT  2.16 25.515 36.72 25.785 ;
     RECT  2.16 26.055 36.72 26.325 ;
     RECT  2.16 26.595 36.72 26.865 ;
     RECT  2.16 27.135 36.72 27.405 ;
     RECT  2.16 27.675 36.72 27.945 ;
     RECT  2.16 28.215 36.72 28.485 ;
     RECT  2.16 28.755 36.72 29.025 ;
     RECT  2.16 29.295 36.72 29.565 ;
     RECT  2.16 29.835 36.72 30.105 ;
     RECT  2.16 30.375 36.72 30.645 ;
     RECT  2.16 30.915 36.72 31.185 ;
     RECT  2.16 31.455 36.72 31.725 ;
     RECT  2.16 31.995 36.72 32.265 ;
     RECT  2.16 32.535 36.72 32.805 ;
     RECT  2.16 33.075 36.72 33.345 ;
     RECT  2.16 33.615 36.72 33.885 ;
     RECT  2.16 34.155 36.72 34.425 ;
     RECT  2.16 34.695 36.72 34.965 ;
     RECT  2.16 35.235 36.72 35.505 ;
     RECT  2.16 35.775 36.72 36.045 ;
     RECT  2.16 36.315 36.72 36.585 ;
     RECT  2.16 36.855 36.72 37.125 ;
     RECT  2.16 37.395 36.72 37.665 ;
     RECT  2.16 37.935 36.72 38.205 ;
     RECT  2.16 38.475 36.72 38.745 ;
     RECT  2.16 39.015 36.72 39.285 ;
     RECT  2.16 39.555 36.72 39.825 ;
     RECT  2.16 40.095 36.72 40.365 ;
     RECT  2.16 40.635 36.72 40.905 ;
     RECT  2.16 41.175 36.72 41.445 ;
     RECT  2.16 41.715 36.72 41.985 ;
     RECT  2.16 42.255 36.72 42.525 ;
     RECT  2.16 42.795 36.72 43.065 ;
     RECT  2.16 43.335 36.72 43.605 ;
     RECT  2.16 43.875 36.72 44.145 ;
     RECT  2.16 44.415 36.72 44.685 ;
     RECT  2.16 44.955 36.72 45.225 ;
     RECT  2.16 45.495 36.72 45.765 ;
     RECT  2.16 46.035 36.72 46.305 ;
     RECT  2.16 46.575 36.72 46.845 ;
     RECT  2.16 47.115 36.72 47.385 ;
     RECT  2.16 47.655 36.72 47.925 ;
     RECT  2.16 48.195 36.72 48.465 ;
     RECT  2.16 48.735 36.72 49.005 ;
     RECT  2.16 49.275 36.72 49.545 ;
     RECT  2.16 49.815 36.72 50.085 ;
     RECT  2.16 50.355 36.72 50.625 ;
     RECT  2.16 50.895 36.72 51.165 ;
     RECT  2.16 51.435 36.72 51.705 ;
     RECT  2.16 51.975 36.72 52.245 ;
     RECT  2.16 52.515 36.72 52.785 ;
     RECT  2.16 53.055 36.72 53.325 ;
     RECT  2.16 53.595 36.72 53.865 ;
     RECT  2.16 54.135 36.72 54.405 ;
     RECT  2.16 54.675 36.72 54.945 ;
     RECT  2.16 55.215 36.72 55.485 ;
     RECT  2.16 55.755 36.72 56.025 ;
     RECT  2.16 56.295 36.72 56.565 ;
     RECT  2.16 56.835 36.72 57.105 ;
     RECT  2.16 57.375 36.72 57.645 ;
     RECT  2.16 57.915 36.72 58.185 ;
     RECT  2.16 58.455 36.72 58.725 ;
     RECT  2.16 58.995 36.72 59.265 ;
     RECT  2.16 59.535 36.72 59.805 ;
     RECT  2.16 60.075 36.72 60.345 ;
     RECT  2.16 60.615 36.72 60.885 ;
     RECT  2.16 61.155 36.72 61.425 ;
     RECT  2.16 61.695 36.72 61.965 ;
     RECT  2.16 62.235 36.72 62.505 ;
     RECT  2.16 62.775 36.72 63.045 ;
     RECT  2.16 63.315 36.72 63.585 ;
     RECT  2.16 63.855 36.72 64.125 ;
     RECT  2.16 64.395 36.72 64.665 ;
     RECT  2.16 64.935 36.72 65.205 ;
     RECT  2.16 65.475 36.72 65.745 ;
     RECT  2.16 66.015 36.72 66.285 ;
     RECT  2.16 66.555 36.72 66.825 ;
     RECT  2.16 67.095 36.72 67.365 ;
     RECT  2.16 67.635 36.72 67.905 ;
     RECT  2.16 68.175 36.72 68.445 ;
     RECT  2.16 68.715 36.72 68.985 ;
     RECT  2.16 69.255 36.72 69.525 ;
     RECT  2.16 69.795 36.72 70.065 ;
     RECT  2.16 70.335 36.72 70.605 ;
     RECT  2.16 70.875 36.72 71.145 ;
     RECT  2.16 71.415 36.72 71.685 ;
     RECT  2.16 71.955 36.72 72.225 ;
     RECT  2.16 72.495 36.72 72.765 ;
     RECT  2.16 73.035 36.72 73.305 ;
     RECT  2.16 73.575 36.72 73.845 ;
     RECT  2.16 74.115 36.72 74.385 ;
     RECT  2.16 74.655 36.72 74.925 ;
     RECT  2.16 75.195 36.72 75.465 ;
     RECT  2.16 75.735 36.72 76.005 ;
     RECT  2.16 76.275 36.72 76.545 ;
     RECT  2.16 76.815 36.72 77.085 ;
     RECT  2.16 77.355 36.72 77.625 ;
     RECT  2.16 77.895 36.72 78.165 ;
     RECT  2.16 78.435 36.72 78.705 ;
     RECT  2.16 78.975 36.72 79.245 ;
     RECT  2.16 79.515 36.72 79.785 ;
     RECT  2.16 80.055 36.72 80.325 ;
     RECT  2.16 80.595 36.72 80.865 ;
     RECT  2.16 81.135 36.72 81.405 ;
     RECT  2.16 81.675 36.72 81.945 ;
     RECT  2.16 82.215 36.72 82.485 ;
     RECT  2.16 82.755 36.72 83.025 ;
     RECT  2.16 83.295 36.72 83.565 ;
     RECT  2.16 83.835 36.72 84.105 ;
     RECT  2.16 84.375 36.72 84.645 ;
     RECT  2.16 84.915 36.72 85.185 ;
     RECT  2.16 85.455 36.72 85.725 ;
     RECT  2.16 85.995 36.72 86.265 ;
     RECT  2.16 86.535 36.72 86.805 ;
     RECT  2.16 87.075 36.72 87.345 ;
     RECT  2.16 87.615 36.72 87.885 ;
     RECT  2.16 88.155 36.72 88.425 ;
     RECT  2.16 88.695 36.72 88.965 ;
     RECT  2.16 89.235 36.72 89.505 ;
     RECT  2.16 89.775 36.72 90.045 ;
     RECT  2.16 90.315 36.72 90.585 ;
     RECT  2.16 90.855 36.72 91.125 ;
     RECT  2.16 91.395 36.72 91.665 ;
     RECT  2.16 91.935 36.72 92.205 ;
     RECT  2.16 92.475 36.72 92.745 ;
    LAYER M1 ;
     RECT  2.16 2.151 36.72 92.889 ;
    LAYER M2 ;
     RECT  0.103 37.026 0.139 37.044 ;
     RECT  0.103 64.296 0.175 64.998 ;
     RECT  0.103 85.896 0.175 85.914 ;
     RECT  0.103 14.22 0.203 14.238 ;
     RECT  0.103 15.264 0.203 16.254 ;
     RECT  0.103 29.916 0.203 29.934 ;
     RECT  0.103 40.914 0.203 42.174 ;
     RECT  0.175 64.296 0.203 65.538 ;
     RECT  0.103 53.334 0.211 53.352 ;
     RECT  0.203 15.264 0.239 15.354 ;
     RECT  0.139 51.786 0.239 51.804 ;
     RECT  0.175 20.466 0.347 20.484 ;
     RECT  0.203 65.52 0.347 65.538 ;
     RECT  0.355 80.064 0.427 80.082 ;
     RECT  0.355 80.91 0.455 80.928 ;
     RECT  0.427 79.488 0.463 80.082 ;
     RECT  0.103 3.888 0.499 4.374 ;
     RECT  0.463 38.556 0.499 38.574 ;
     RECT  0.203 40.914 0.499 40.932 ;
     RECT  0.103 49.446 0.499 50.076 ;
     RECT  0.103 56.736 0.499 56.754 ;
     RECT  0.103 62.676 0.499 63.27 ;
     RECT  0.175 76.824 0.499 76.842 ;
     RECT  0.463 78.912 0.499 80.082 ;
     RECT  0.499 3.654 0.535 4.374 ;
     RECT  0.499 10.944 0.535 10.962 ;
     RECT  0.103 12.456 0.535 12.474 ;
     RECT  0.463 13.95 0.535 14.166 ;
     RECT  0.203 16.236 0.535 16.254 ;
     RECT  0.103 24.336 0.535 24.354 ;
     RECT  0.499 27.216 0.535 27.504 ;
     RECT  0.139 37.026 0.535 37.584 ;
     RECT  0.499 38.448 0.535 38.574 ;
     RECT  0.499 40.338 0.535 40.932 ;
     RECT  0.499 49.356 0.535 50.076 ;
     RECT  0.211 52.956 0.535 53.352 ;
     RECT  0.499 56.736 0.535 57.474 ;
     RECT  0.499 62.244 0.535 63.27 ;
     RECT  0.203 64.296 0.535 64.314 ;
     RECT  0.499 75.636 0.535 75.654 ;
     RECT  0.499 76.824 0.535 77.814 ;
     RECT  0.499 81.918 0.535 81.936 ;
     RECT  0.103 83.07 0.535 83.664 ;
     RECT  0.535 75.636 1.175 75.798 ;
     RECT  0.535 37.026 1.211 38.574 ;
     RECT  0.535 1.962 2.16 1.98 ;
     RECT  0.535 3.186 2.16 4.374 ;
     RECT  0.535 10.944 2.16 11.034 ;
     RECT  0.535 12.024 2.16 12.474 ;
     RECT  0.535 13.878 2.16 14.166 ;
     RECT  0.239 15.336 2.16 15.354 ;
     RECT  0.535 16.236 2.16 16.434 ;
     RECT  0.103 18.126 2.16 18.684 ;
     RECT  0.535 24.246 2.16 24.354 ;
     RECT  0.103 25.488 2.16 25.506 ;
     RECT  0.535 27.216 2.16 28.008 ;
     RECT  1.211 37.026 2.16 38.466 ;
     RECT  0.535 39.366 2.16 40.932 ;
     RECT  0.203 41.688 2.16 42.174 ;
     RECT  0.535 48.51 2.16 48.528 ;
     RECT  0.535 49.356 2.16 50.544 ;
     RECT  0.535 52.254 2.16 53.352 ;
     RECT  0.103 54.684 2.16 54.702 ;
     RECT  0.535 56.736 2.16 58.554 ;
     RECT  0.535 62.244 2.16 64.314 ;
     RECT  1.175 75.636 2.16 75.726 ;
     RECT  0.535 76.716 2.16 77.922 ;
     RECT  0.499 78.912 2.16 80.154 ;
     RECT  0.535 81.918 2.16 82.044 ;
     RECT  0.535 82.998 2.16 84.204 ;
     RECT  0.175 85.194 2.16 85.914 ;
     RECT  2.16 1.962 3.479 92.889 ;
     RECT  3.479 2.034 4.675 92.889 ;
     RECT  4.675 1.926 7.583 92.889 ;
     RECT  7.583 1.998 9.311 92.889 ;
     RECT  9.311 2.151 14.251 92.889 ;
     RECT  14.251 2.106 14.323 92.889 ;
     RECT  14.323 2.07 14.531 92.889 ;
     RECT  14.531 2.106 15.431 92.889 ;
     RECT  15.431 2.151 36.72 92.889 ;
     RECT  36.72 36.396 36.995 37.584 ;
     RECT  36.72 77.058 36.995 89.496 ;
     RECT  36.72 38.412 37.031 41.778 ;
     RECT  36.72 68.76 37.031 70.056 ;
     RECT  36.995 77.058 37.067 87.066 ;
     RECT  36.72 45.27 37.319 57.132 ;
     RECT  37.031 70.038 37.319 70.056 ;
     RECT  36.72 72 37.319 74.214 ;
     RECT  36.72 11.79 37.499 18.45 ;
     RECT  37.319 45.27 37.571 49.338 ;
     RECT  37.067 77.13 37.571 87.066 ;
     RECT  36.995 87.93 37.571 89.496 ;
     RECT  36.72 6.084 37.607 10.89 ;
     RECT  37.499 11.79 37.607 16.398 ;
     RECT  37.499 17.388 37.607 18.45 ;
     RECT  36.72 27.99 37.607 33.876 ;
     RECT  36.72 34.704 37.607 35.226 ;
     RECT  36.72 43.146 37.607 44.442 ;
     RECT  37.571 45.27 37.607 47.448 ;
     RECT  37.319 50.4 37.607 57.132 ;
     RECT  36.72 57.996 37.607 61.488 ;
     RECT  36.72 63.828 37.607 67.968 ;
     RECT  37.571 77.13 37.607 86.904 ;
     RECT  37.031 38.412 37.643 41.508 ;
     RECT  37.607 63.828 37.643 64.962 ;
     RECT  37.607 77.13 37.643 85.554 ;
     RECT  37.643 39.6 37.715 41.508 ;
     RECT  37.643 78.678 37.715 85.554 ;
     RECT  37.607 43.146 37.895 43.164 ;
     RECT  37.571 48.438 37.895 49.338 ;
     RECT  37.031 68.76 37.895 68.976 ;
     RECT  36.72 71.226 37.895 71.244 ;
     RECT  37.319 72.396 37.931 74.214 ;
     RECT  37.643 77.13 38.003 77.922 ;
     RECT  37.607 50.4 38.183 53.154 ;
     RECT  37.715 79.326 38.183 85.554 ;
     RECT  37.607 8.406 38.219 10.89 ;
     RECT  37.607 11.79 38.219 14.814 ;
     RECT  37.607 30.15 38.219 33.876 ;
     RECT  37.607 34.704 38.219 35.154 ;
     RECT  37.715 39.636 38.219 41.508 ;
     RECT  37.607 43.92 38.219 44.442 ;
     RECT  37.607 53.946 38.219 57.132 ;
     RECT  37.607 58.428 38.219 60.372 ;
     RECT  36.72 62.82 38.219 62.838 ;
     RECT  37.607 66.06 38.219 67.968 ;
     RECT  38.003 77.364 38.219 77.922 ;
     RECT  38.183 80.874 38.219 85.554 ;
     RECT  37.607 86.544 38.219 86.904 ;
     RECT  37.607 15.57 38.255 15.894 ;
     RECT  37.607 17.658 38.255 18.45 ;
     RECT  36.72 27.216 38.255 27.234 ;
     RECT  38.219 43.956 38.255 44.442 ;
     RECT  37.643 63.828 38.255 64.728 ;
     RECT  38.219 66.06 38.255 67.734 ;
     RECT  36.72 75.204 38.255 75.834 ;
     RECT  38.219 80.874 38.255 82.548 ;
     RECT  37.571 87.93 38.255 89.262 ;
     RECT  38.219 11.79 38.291 13.194 ;
     RECT  38.255 17.73 38.291 18.45 ;
     RECT  37.607 27.99 38.291 29.358 ;
     RECT  38.219 34.704 38.291 34.758 ;
     RECT  38.255 44.001 38.291 44.442 ;
     RECT  38.183 50.751 38.291 53.154 ;
     RECT  38.255 63.828 38.291 64.152 ;
     RECT  38.219 77.364 38.291 77.418 ;
     RECT  38.183 79.326 38.291 80.01 ;
     RECT  38.291 11.79 38.327 13.122 ;
     RECT  38.219 33.084 38.327 33.876 ;
     RECT  38.291 44.001 38.327 44.019 ;
     RECT  38.219 54.378 38.327 55.044 ;
     RECT  38.255 80.874 38.327 81.396 ;
     RECT  38.291 28.026 38.363 29.358 ;
     RECT  38.327 33.201 38.363 33.876 ;
     RECT  38.327 81.378 38.363 81.396 ;
     RECT  37.607 6.084 38.399 7.614 ;
     RECT  37.931 74.196 38.407 74.214 ;
     RECT  38.255 75.204 38.407 75.222 ;
     RECT  38.219 8.406 38.435 10.692 ;
     RECT  37.607 45.27 38.471 47.412 ;
     RECT  38.291 77.4 38.471 77.418 ;
     RECT  38.363 28.188 38.507 29.358 ;
     RECT  38.471 45.468 38.507 47.412 ;
     RECT  36.995 36.396 38.543 36.414 ;
     RECT  38.407 74.196 38.543 75.222 ;
     RECT  38.255 87.93 38.551 88.92 ;
     RECT  38.507 28.926 38.579 29.358 ;
     RECT  38.291 64.134 38.579 64.152 ;
     RECT  38.543 74.196 38.579 74.754 ;
     RECT  38.399 6.084 38.615 7.344 ;
     RECT  38.435 8.748 38.615 10.692 ;
     RECT  38.219 86.886 38.623 86.904 ;
     RECT  38.551 87.696 38.623 88.92 ;
     RECT  38.615 6.084 38.651 6.102 ;
     RECT  38.615 8.748 38.651 10.422 ;
     RECT  37.643 38.412 38.651 38.844 ;
     RECT  38.623 86.886 38.651 88.92 ;
     RECT  38.579 29.34 38.687 29.358 ;
     RECT  36.995 37.17 38.687 37.584 ;
     RECT  38.507 45.468 38.687 46.134 ;
     RECT  38.219 58.428 38.687 59.526 ;
     RECT  38.219 14.796 38.695 14.814 ;
     RECT  38.659 16.776 38.695 16.794 ;
     RECT  38.507 46.89 38.695 47.412 ;
     RECT  37.895 48.438 38.695 48.456 ;
     RECT  38.219 60.318 38.695 60.372 ;
     RECT  37.607 61.128 38.695 61.488 ;
     RECT  38.255 66.06 38.695 66.51 ;
     RECT  38.615 6.93 38.723 7.344 ;
     RECT  38.651 9.828 38.723 10.422 ;
     RECT  38.219 30.15 38.723 31.824 ;
     RECT  37.895 49.32 38.723 49.338 ;
     RECT  38.695 60.318 38.723 61.488 ;
     RECT  37.895 68.958 38.723 68.976 ;
     RECT  37.931 72.396 38.723 73.332 ;
     RECT  38.651 86.886 38.723 87.066 ;
     RECT  38.651 8.748 38.759 8.964 ;
     RECT  38.695 16.344 38.759 16.794 ;
     RECT  38.723 31.536 38.759 31.824 ;
     RECT  38.291 34.74 38.759 34.758 ;
     RECT  38.687 37.566 38.759 37.584 ;
     RECT  38.651 38.754 38.759 38.844 ;
     RECT  38.695 46.89 38.759 48.456 ;
     RECT  38.291 50.751 38.759 52.848 ;
     RECT  38.723 72.576 38.759 73.332 ;
     RECT  38.723 87.048 38.759 87.066 ;
     RECT  38.723 6.93 38.795 6.948 ;
     RECT  38.759 8.748 38.795 8.919 ;
     RECT  38.723 10.17 38.795 10.422 ;
     RECT  38.327 12.294 38.795 13.122 ;
     RECT  38.219 13.95 38.795 13.968 ;
     RECT  38.695 14.796 38.795 15.318 ;
     RECT  38.759 16.344 38.795 16.362 ;
     RECT  38.291 17.73 38.795 17.829 ;
     RECT  38.363 33.858 38.795 33.876 ;
     RECT  38.219 39.762 38.795 41.004 ;
     RECT  38.687 45.81 38.795 46.134 ;
     RECT  38.759 46.89 38.795 48.186 ;
     RECT  38.759 51.75 38.795 52.848 ;
     RECT  38.327 54.378 38.795 54.972 ;
     RECT  38.219 55.8 38.795 56.826 ;
     RECT  38.687 58.428 38.795 59.094 ;
     RECT  38.723 60.354 38.795 61.488 ;
     RECT  38.695 65.718 38.795 66.51 ;
     RECT  38.255 67.266 38.795 67.734 ;
     RECT  38.759 72.576 38.795 72.594 ;
     RECT  38.291 79.56 38.795 80.01 ;
     RECT  38.255 82.53 38.795 82.548 ;
     RECT  38.219 84.231 38.795 85.446 ;
     RECT  38.651 88.47 38.795 88.92 ;
     RECT  38.795 8.748 38.831 8.766 ;
     RECT  38.795 13.104 38.831 13.122 ;
     RECT  38.795 17.811 38.831 17.829 ;
     RECT  36.72 20.088 38.831 20.106 ;
     RECT  38.759 38.826 38.831 38.844 ;
     RECT  38.795 47.394 38.831 47.412 ;
     RECT  38.795 52.371 38.831 52.389 ;
     RECT  38.731 78.561 38.831 78.66 ;
     RECT  38.767 19.044 38.867 19.062 ;
     RECT  36.72 23.976 38.867 23.994 ;
     RECT  38.767 30.078 38.867 30.096 ;
     RECT  38.795 39.762 38.867 39.78 ;
     RECT  38.795 45.81 38.867 45.828 ;
     RECT  38.795 54.378 38.867 54.396 ;
     RECT  38.795 56.691 38.867 56.709 ;
     RECT  38.795 61.281 38.867 61.299 ;
     RECT  38.579 74.664 38.867 74.754 ;
     RECT  38.831 78.561 38.867 78.579 ;
     RECT  38.795 79.992 38.867 80.01 ;
     RECT  38.795 84.231 38.867 84.249 ;
     RECT  38.795 85.428 38.867 85.446 ;
     RECT  38.767 89.712 38.867 89.73 ;
    LAYER M3 ;
     RECT  5.544 1.957 5.562 1.993 ;
     RECT  6.768 1.957 6.786 1.993 ;
     RECT  3.456 1.957 3.474 2.065 ;
     RECT  3.42 2.065 3.474 2.101 ;
     RECT  4.68 1.921 4.698 2.101 ;
     RECT  7.56 1.921 7.578 2.101 ;
     RECT  14.328 2.065 14.526 2.101 ;
     RECT  2.952 2.101 3.474 2.143 ;
     RECT  4.212 2.101 4.698 2.143 ;
     RECT  5.544 1.993 6.786 2.143 ;
     RECT  15.408 2.101 15.426 2.143 ;
     RECT  2.415 2.143 3.474 2.155 ;
     RECT  7.56 2.101 8.01 2.191 ;
     RECT  9.288 1.993 9.306 2.191 ;
     RECT  10.515 2.143 10.605 2.191 ;
     RECT  13.215 2.143 13.305 2.191 ;
     RECT  14.256 2.101 14.526 2.191 ;
     RECT  15.408 2.143 16.005 2.191 ;
     RECT  18.615 2.143 18.705 2.191 ;
     RECT  24.015 2.143 24.105 2.191 ;
     RECT  26.715 2.143 26.805 2.191 ;
     RECT  29.415 2.143 29.505 2.191 ;
     RECT  32.115 2.143 32.205 2.191 ;
     RECT  4.212 2.143 6.786 2.227 ;
     RECT  7.56 2.191 9.306 2.227 ;
     RECT  13.215 2.191 14.598 2.227 ;
     RECT  17.964 2.191 18.705 2.227 ;
     RECT  21.315 2.143 21.405 2.227 ;
     RECT  29.415 2.191 29.574 2.227 ;
     RECT  30.708 2.191 30.726 2.227 ;
     RECT  24.015 2.191 24.174 2.251 ;
     RECT  25.416 2.191 25.434 2.251 ;
     RECT  28.62 2.191 28.638 2.251 ;
     RECT  29.415 2.227 30.726 2.251 ;
     RECT  4.212 2.227 9.306 2.263 ;
     RECT  10.515 2.191 11.214 2.263 ;
     RECT  17.244 2.227 18.705 2.263 ;
     RECT  27.684 2.227 27.702 2.263 ;
     RECT  28.62 2.251 30.726 2.263 ;
     RECT  15.408 2.191 16.398 2.293 ;
     RECT  15.336 2.293 16.398 2.299 ;
     RECT  17.244 2.263 19.098 2.299 ;
     RECT  32.115 2.191 33.318 2.335 ;
     RECT  0.54 1.957 0.558 2.347 ;
     RECT  4.212 2.263 11.214 2.371 ;
     RECT  20.664 2.227 21.405 2.371 ;
     RECT  23.256 2.227 23.274 2.371 ;
     RECT  24.015 2.251 25.434 2.371 ;
     RECT  26.316 2.191 26.805 2.371 ;
     RECT  23.256 2.371 26.805 2.413 ;
     RECT  27.684 2.263 30.726 2.413 ;
     RECT  34.815 2.143 34.905 2.413 ;
     RECT  4.212 2.371 11.322 2.461 ;
     RECT  12.528 2.227 14.598 2.461 ;
     RECT  15.336 2.299 19.098 2.461 ;
     RECT  20.664 2.371 21.654 2.461 ;
     RECT  0.54 2.347 0.666 2.477 ;
     RECT  4.212 2.461 11.358 2.491 ;
     RECT  4.212 2.491 11.466 2.497 ;
     RECT  12.528 2.461 19.098 2.497 ;
     RECT  2.304 2.155 3.474 2.569 ;
     RECT  4.212 2.497 19.098 2.569 ;
     RECT  2.304 2.569 19.098 2.605 ;
     RECT  20.664 2.461 21.906 2.605 ;
     RECT  0.54 2.477 0.558 2.635 ;
     RECT  2.304 2.605 19.674 2.635 ;
     RECT  2.304 2.635 19.89 2.641 ;
     RECT  20.664 2.605 22.41 2.641 ;
     RECT  23.256 2.413 30.726 2.641 ;
     RECT  2.304 2.641 31.374 2.731 ;
     RECT  32.115 2.335 33.642 2.731 ;
     RECT  2.304 2.731 33.642 2.759 ;
     RECT  2.304 2.759 33.462 2.768 ;
     RECT  2.415 2.768 33.462 2.795 ;
     RECT  2.415 2.795 33.426 3.541 ;
     RECT  2.415 3.541 33.786 3.577 ;
     RECT  2.415 3.577 33.93 3.685 ;
     RECT  0.144 2.635 0.558 3.883 ;
     RECT  2.415 3.685 34.038 3.883 ;
     RECT  34.815 2.413 35.097 3.883 ;
     RECT  0.108 3.883 0.558 4.013 ;
     RECT  0.108 4.013 0.522 4.109 ;
     RECT  36.504 3.685 36.522 4.109 ;
     RECT  2.415 3.883 35.097 4.363 ;
     RECT  0.108 4.109 0.198 4.493 ;
     RECT  0.108 4.493 0.126 4.685 ;
     RECT  2.304 4.363 35.097 4.693 ;
     RECT  2.268 4.693 35.097 4.877 ;
     RECT  2.304 4.877 35.097 5.261 ;
     RECT  36.36 4.225 36.378 5.341 ;
     RECT  2.415 5.261 35.097 5.467 ;
     RECT  36.108 5.341 36.378 5.701 ;
     RECT  2.415 5.467 35.154 5.881 ;
     RECT  36.108 5.701 36.522 5.881 ;
     RECT  38.7 4.747 38.718 6.079 ;
     RECT  38.628 6.079 38.718 6.151 ;
     RECT  38.196 6.151 38.718 6.331 ;
     RECT  2.415 5.881 36.522 6.449 ;
     RECT  38.196 6.331 38.862 6.655 ;
     RECT  2.415 6.449 11.25 6.667 ;
     RECT  2.376 6.667 11.25 6.809 ;
     RECT  38.16 6.655 38.862 6.817 ;
     RECT  2.415 6.809 11.25 6.845 ;
     RECT  11.988 6.449 36.522 6.845 ;
     RECT  12.132 6.845 36.522 7.195 ;
     RECT  37.62 6.817 38.862 7.195 ;
     RECT  12.132 7.195 38.862 7.349 ;
     RECT  12.132 7.349 36.378 7.421 ;
     RECT  37.62 7.349 38.862 7.469 ;
     RECT  2.415 6.845 11.178 7.591 ;
     RECT  12.132 7.421 24.534 7.591 ;
     RECT  2.415 7.591 24.534 7.663 ;
     RECT  2.376 7.663 24.534 7.997 ;
     RECT  25.308 7.421 36.378 8.141 ;
     RECT  25.308 8.141 36.126 8.159 ;
     RECT  2.415 7.997 24.534 8.167 ;
     RECT  25.308 8.159 36.09 8.167 ;
     RECT  37.656 7.469 38.862 8.275 ;
     RECT  37.584 8.275 38.862 8.525 ;
     RECT  36.936 8.626 37.026 8.771 ;
     RECT  2.415 8.167 36.09 8.861 ;
     RECT  38.16 8.525 38.862 8.924 ;
     RECT  2.415 8.861 35.91 9.115 ;
     RECT  2.304 9.115 35.91 9.239 ;
     RECT  38.196 8.924 38.862 9.293 ;
     RECT  2.376 9.239 35.91 9.509 ;
     RECT  12.168 9.509 35.91 9.625 ;
     RECT  38.232 9.293 38.862 9.968 ;
     RECT  37.584 10.12 37.602 10.157 ;
     RECT  2.376 9.509 11.178 10.193 ;
     RECT  2.412 10.193 11.178 10.205 ;
     RECT  2.415 10.205 11.178 10.291 ;
     RECT  12.168 9.625 36.09 10.291 ;
     RECT  2.415 10.291 36.09 10.435 ;
     RECT  37.08 10.363 37.098 10.435 ;
     RECT  38.52 9.968 38.862 10.867 ;
     RECT  2.415 10.435 37.098 10.925 ;
     RECT  38.196 10.867 38.862 10.987 ;
     RECT  0.504 10.939 0.522 11.011 ;
     RECT  2.415 10.925 36.522 11.101 ;
     RECT  38.088 10.987 38.862 11.117 ;
     RECT  2.304 11.101 36.522 11.309 ;
     RECT  2.304 11.309 36.342 11.939 ;
     RECT  38.304 11.117 38.862 12.043 ;
     RECT  0.504 11.011 0.558 12.139 ;
     RECT  0.144 12.139 0.558 12.451 ;
     RECT  0.108 12.451 0.558 12.557 ;
     RECT  0.18 12.557 0.558 12.619 ;
     RECT  0.18 12.619 1.17 12.749 ;
     RECT  2.304 11.939 36.27 12.811 ;
     RECT  2.304 12.811 36.414 12.907 ;
     RECT  0.54 12.749 1.17 13.037 ;
     RECT  37.584 12.043 38.862 13.063 ;
     RECT  0.54 13.037 0.558 13.133 ;
     RECT  0.144 13.483 0.162 13.873 ;
     RECT  37.548 13.063 38.862 13.997 ;
     RECT  2.304 12.907 36.558 14.099 ;
     RECT  0.144 13.873 0.558 14.215 ;
     RECT  0.108 14.215 0.558 14.285 ;
     RECT  2.412 14.099 36.558 14.369 ;
     RECT  2.412 14.369 36.414 14.381 ;
     RECT  0.108 14.285 0.522 14.669 ;
     RECT  0.108 14.669 0.486 14.861 ;
     RECT  37.62 13.997 38.862 15.025 ;
     RECT  0.108 14.861 0.342 15.245 ;
     RECT  2.415 14.381 36.414 15.355 ;
     RECT  37.584 15.025 38.862 15.403 ;
     RECT  0.108 15.245 0.234 15.485 ;
     RECT  2.412 15.355 36.414 15.601 ;
     RECT  37.548 15.403 38.862 15.899 ;
     RECT  2.412 15.601 36.522 15.961 ;
     RECT  37.548 15.899 37.602 16.267 ;
     RECT  0.108 15.485 0.198 16.411 ;
     RECT  37.368 16.267 37.602 16.493 ;
     RECT  0.108 16.411 0.558 16.589 ;
     RECT  2.304 15.961 36.522 16.673 ;
     RECT  0.324 16.589 0.558 16.685 ;
     RECT  38.7 15.899 38.862 16.771 ;
     RECT  0.324 16.685 0.342 16.877 ;
     RECT  37.476 16.493 37.602 16.943 ;
     RECT  2.304 16.673 36.414 17.221 ;
     RECT  2.268 17.221 36.414 17.357 ;
     RECT  2.304 17.357 36.414 17.411 ;
     RECT  37.584 16.943 37.602 17.411 ;
     RECT  38.664 16.771 38.862 17.419 ;
     RECT  38.088 17.419 38.862 17.549 ;
     RECT  2.34 17.411 36.414 17.645 ;
     RECT  0.108 18.121 0.126 18.193 ;
     RECT  2.34 17.645 36.126 18.265 ;
     RECT  0.108 18.193 0.522 18.379 ;
     RECT  0.108 18.379 1.17 18.509 ;
     RECT  38.196 17.549 38.862 18.509 ;
     RECT  2.304 18.265 36.126 18.599 ;
     RECT  2.412 18.599 36.126 18.805 ;
     RECT  0.108 18.509 0.558 18.893 ;
     RECT  38.268 18.509 38.862 18.893 ;
     RECT  0.108 18.893 0.126 18.989 ;
     RECT  38.772 18.893 38.862 19.067 ;
     RECT  38.772 19.067 38.826 19.085 ;
     RECT  2.412 18.805 36.414 19.435 ;
     RECT  2.304 19.435 36.414 19.651 ;
     RECT  2.304 19.651 36.522 19.805 ;
     RECT  38.808 19.085 38.826 20.111 ;
     RECT  0.324 20.299 0.342 20.395 ;
     RECT  0.18 20.395 0.342 20.525 ;
     RECT  2.304 19.805 36.198 20.579 ;
     RECT  1.152 19.771 1.17 20.587 ;
     RECT  1.152 20.587 1.386 20.717 ;
     RECT  1.152 20.717 1.17 20.957 ;
     RECT  0.144 20.923 0.162 21.101 ;
     RECT  2.304 20.579 36.162 21.361 ;
     RECT  2.304 21.361 36.342 21.659 ;
     RECT  2.415 21.659 36.342 21.821 ;
     RECT  28.728 21.821 36.342 22.001 ;
     RECT  28.836 22.001 36.342 22.045 ;
     RECT  28.836 22.045 36.378 22.199 ;
     RECT  2.415 21.821 27.99 22.585 ;
     RECT  2.376 22.585 27.99 23.125 ;
     RECT  2.376 23.125 28.026 23.315 ;
     RECT  28.836 22.199 36.198 23.431 ;
     RECT  2.415 23.315 28.026 23.459 ;
     RECT  12.924 23.459 28.026 23.665 ;
     RECT  28.836 23.431 36.594 23.665 ;
     RECT  12.924 23.665 36.594 23.693 ;
     RECT  12.924 23.693 36.45 24.125 ;
     RECT  12.924 24.125 36.126 24.205 ;
     RECT  2.415 23.459 11.718 24.241 ;
     RECT  12.744 24.205 36.126 24.241 ;
     RECT  0.54 24.241 0.558 24.331 ;
     RECT  0.108 24.331 0.558 24.557 ;
     RECT  2.415 24.241 36.126 24.629 ;
     RECT  0.108 24.557 0.342 24.653 ;
     RECT  2.415 24.629 36.054 24.715 ;
     RECT  2.376 24.715 36.054 24.745 ;
     RECT  2.304 24.745 36.054 24.811 ;
     RECT  0.324 24.653 0.342 24.941 ;
     RECT  2.268 24.811 36.054 25.007 ;
     RECT  0.144 25.387 0.162 25.483 ;
     RECT  0.108 25.483 0.162 25.675 ;
     RECT  0.108 25.675 0.342 25.805 ;
     RECT  2.304 25.007 36.054 25.861 ;
     RECT  2.304 25.861 36.522 26.011 ;
     RECT  1.98 26.011 36.522 26.059 ;
     RECT  1.98 26.059 36.594 26.861 ;
     RECT  1.98 26.861 36.522 26.957 ;
     RECT  1.152 25.819 1.17 27.101 ;
     RECT  38.844 23.971 38.862 27.115 ;
     RECT  0.18 26.779 0.198 27.163 ;
     RECT  0.18 27.163 0.27 27.211 ;
     RECT  38.772 27.115 38.862 27.211 ;
     RECT  0.18 27.211 0.558 27.245 ;
     RECT  0.252 27.245 0.558 27.341 ;
     RECT  2.304 26.957 36.522 27.679 ;
     RECT  0.504 27.341 0.558 27.979 ;
     RECT  0.504 27.979 0.63 28.109 ;
     RECT  2.304 27.679 36.594 28.453 ;
     RECT  0.504 28.109 0.558 28.589 ;
     RECT  38.232 27.211 38.862 28.687 ;
     RECT  2.304 28.453 37.062 28.843 ;
     RECT  0.18 28.699 0.198 28.973 ;
     RECT  1.98 28.843 37.062 28.973 ;
     RECT  2.304 28.973 37.062 29.029 ;
     RECT  38.196 28.687 38.862 29.029 ;
     RECT  2.304 29.029 38.862 29.549 ;
     RECT  37.584 29.549 38.862 29.831 ;
     RECT  0.144 29.707 0.162 29.911 ;
     RECT  38.124 29.831 38.862 30.101 ;
     RECT  38.124 30.101 38.79 30.125 ;
     RECT  0.108 29.911 0.198 30.283 ;
     RECT  2.304 29.549 36.558 30.407 ;
     RECT  0.108 30.283 0.342 30.413 ;
     RECT  38.124 30.125 38.718 30.413 ;
     RECT  0.108 30.413 0.126 30.605 ;
     RECT  2.415 30.407 36.558 30.613 ;
     RECT  2.415 30.613 37.062 30.883 ;
     RECT  2.415 30.883 37.098 31.181 ;
     RECT  38.196 30.413 38.718 31.435 ;
     RECT  38.196 31.435 38.79 31.915 ;
     RECT  2.415 31.181 36.594 31.919 ;
     RECT  37.548 31.915 38.79 32.539 ;
     RECT  3.996 31.919 36.594 32.729 ;
     RECT  2.415 31.919 3.186 32.737 ;
     RECT  3.996 32.729 25.146 32.737 ;
     RECT  26.172 32.729 36.594 33.115 ;
     RECT  26.172 33.115 36.774 33.313 ;
     RECT  37.548 32.539 38.862 33.313 ;
     RECT  26.172 33.313 38.862 33.485 ;
     RECT  26.172 33.485 36.558 33.539 ;
     RECT  26.172 33.539 36.522 33.583 ;
     RECT  2.415 32.737 25.146 33.787 ;
     RECT  2.415 33.787 25.218 34.171 ;
     RECT  25.992 33.583 36.522 34.171 ;
     RECT  2.415 34.171 36.522 34.891 ;
     RECT  37.584 33.485 38.862 34.891 ;
     RECT  2.415 34.891 38.862 35.131 ;
     RECT  2.376 35.131 38.862 35.159 ;
     RECT  38.592 35.159 38.862 35.213 ;
     RECT  2.376 35.159 37.602 35.231 ;
     RECT  2.376 35.231 36.99 35.735 ;
     RECT  2.376 35.735 36.162 35.969 ;
     RECT  38.808 35.213 38.862 36.391 ;
     RECT  36.972 35.735 36.99 36.581 ;
     RECT  2.415 35.969 36.162 36.895 ;
     RECT  2.415 36.895 36.522 37.049 ;
     RECT  2.415 37.049 36.162 37.319 ;
     RECT  0.108 37.021 0.126 37.399 ;
     RECT  1.152 37.327 1.17 37.399 ;
     RECT  0.108 37.399 1.17 37.427 ;
     RECT  38.52 36.391 38.862 37.471 ;
     RECT  0.108 37.427 0.558 37.613 ;
     RECT  0.144 37.613 0.558 37.709 ;
     RECT  2.415 37.319 36.054 37.771 ;
     RECT  0.54 37.709 0.558 38.347 ;
     RECT  0.54 38.347 1.17 38.371 ;
     RECT  2.304 37.771 36.054 38.395 ;
     RECT  0.54 38.371 1.206 38.443 ;
     RECT  2.268 38.395 36.054 38.471 ;
     RECT  0.504 38.443 1.206 38.551 ;
     RECT  2.304 38.471 36.054 38.551 ;
     RECT  0.468 38.551 1.206 38.579 ;
     RECT  38.232 37.471 38.862 38.768 ;
     RECT  2.304 38.551 36.234 39.055 ;
     RECT  0.468 38.579 0.558 39.067 ;
     RECT  2.304 39.055 36.522 39.245 ;
     RECT  2.304 39.245 30.078 39.403 ;
     RECT  2.268 39.403 30.078 39.479 ;
     RECT  38.196 38.768 38.862 39.499 ;
     RECT  37.62 39.499 38.862 39.785 ;
     RECT  31.248 39.245 36.522 39.865 ;
     RECT  37.62 39.785 38.79 39.883 ;
     RECT  31.248 39.865 36.594 39.991 ;
     RECT  2.304 39.479 30.078 40.063 ;
     RECT  30.996 39.991 36.594 40.063 ;
     RECT  37.512 39.883 38.79 40.163 ;
     RECT  2.304 40.063 36.594 40.433 ;
     RECT  0.144 39.067 0.558 40.603 ;
     RECT  0.144 40.603 1.278 40.909 ;
     RECT  37.584 40.163 38.79 41.009 ;
     RECT  37.584 41.009 38.718 41.069 ;
     RECT  0.108 40.909 1.278 41.131 ;
     RECT  2.304 40.433 35.982 41.243 ;
     RECT  0.108 41.131 1.386 41.261 ;
     RECT  0.108 41.261 1.17 41.357 ;
     RECT  37.044 41.215 37.062 41.453 ;
     RECT  34.056 41.243 35.982 41.611 ;
     RECT  2.304 41.243 33.21 41.648 ;
     RECT  38.196 41.069 38.718 41.755 ;
     RECT  37.008 41.755 37.026 41.837 ;
     RECT  38.196 41.755 38.862 41.933 ;
     RECT  34.056 41.611 36.09 42.061 ;
     RECT  38.592 41.933 38.862 42.125 ;
     RECT  2.415 41.648 33.21 42.187 ;
     RECT  34.056 42.061 36.594 42.187 ;
     RECT  0.108 41.357 0.558 42.221 ;
     RECT  2.415 42.187 36.594 42.251 ;
     RECT  0.108 42.221 0.198 42.317 ;
     RECT  0.144 42.317 0.198 42.509 ;
     RECT  2.415 42.251 36.522 42.667 ;
     RECT  1.152 43.099 1.17 43.277 ;
     RECT  37.872 43.141 37.89 43.303 ;
     RECT  0.144 42.509 0.162 43.325 ;
     RECT  2.304 42.667 36.522 43.637 ;
     RECT  2.304 43.637 22.914 43.799 ;
     RECT  37.584 43.303 37.89 43.915 ;
     RECT  38.844 42.125 38.862 43.915 ;
     RECT  23.652 43.637 36.522 43.979 ;
     RECT  23.94 43.979 36.522 44.149 ;
     RECT  37.584 43.915 38.862 44.149 ;
     RECT  2.415 43.799 22.878 44.653 ;
     RECT  2.415 44.653 22.914 44.689 ;
     RECT  2.415 44.689 22.986 44.725 ;
     RECT  23.94 44.149 38.862 44.761 ;
     RECT  2.415 44.725 23.022 44.971 ;
     RECT  2.412 44.971 23.022 45.023 ;
     RECT  2.415 45.023 23.022 45.157 ;
     RECT  23.904 44.761 38.862 45.157 ;
     RECT  2.415 45.157 38.862 45.293 ;
     RECT  2.415 45.293 36.378 45.341 ;
     RECT  33.336 45.341 36.378 45.581 ;
     RECT  37.548 45.293 38.862 45.833 ;
     RECT  37.548 45.833 38.79 46.139 ;
     RECT  37.548 46.139 38.718 46.253 ;
     RECT  2.415 45.341 32.49 46.345 ;
     RECT  33.372 45.581 36.378 46.345 ;
     RECT  2.415 46.345 32.526 46.651 ;
     RECT  33.372 46.345 37.134 46.651 ;
     RECT  37.872 46.253 38.718 46.885 ;
     RECT  2.415 46.651 37.134 47.075 ;
     RECT  28.224 47.075 37.134 47.309 ;
     RECT  37.872 46.885 38.79 47.389 ;
     RECT  37.872 47.389 38.826 47.425 ;
     RECT  37.548 47.425 38.826 47.693 ;
     RECT  2.415 47.075 27.45 47.821 ;
     RECT  28.224 47.309 36.522 47.821 ;
     RECT  38.448 47.693 38.826 47.885 ;
     RECT  38.664 47.885 38.826 47.981 ;
     RECT  38.7 47.981 38.826 48.221 ;
     RECT  37.548 47.693 37.602 48.269 ;
     RECT  38.736 48.221 38.826 48.715 ;
     RECT  38.736 48.715 38.862 49.315 ;
     RECT  0.54 48.505 0.558 49.351 ;
     RECT  0.504 49.351 0.558 49.441 ;
     RECT  0.108 49.441 0.558 49.709 ;
     RECT  2.415 47.821 36.522 49.747 ;
     RECT  2.304 49.747 36.522 49.805 ;
     RECT  2.412 49.805 36.522 50.009 ;
     RECT  37.872 48.775 37.89 50.053 ;
     RECT  0.108 49.709 0.522 50.189 ;
     RECT  37.296 50.053 37.89 50.395 ;
     RECT  38.7 49.315 38.862 50.395 ;
     RECT  0.216 50.189 0.522 50.521 ;
     RECT  0.216 50.521 0.558 50.525 ;
     RECT  2.412 50.009 36.414 50.731 ;
     RECT  2.304 50.731 36.414 50.791 ;
     RECT  2.196 50.791 36.414 50.861 ;
     RECT  0.504 50.525 0.558 51.053 ;
     RECT  2.304 50.861 36.414 52.171 ;
     RECT  37.296 50.395 38.862 52.171 ;
     RECT  2.304 52.171 38.862 52.241 ;
     RECT  0.144 51.307 0.342 52.249 ;
     RECT  0.144 52.249 0.558 52.253 ;
     RECT  2.304 52.241 36.414 52.321 ;
     RECT  2.268 52.321 36.414 52.397 ;
     RECT  2.304 52.397 36.414 52.987 ;
     RECT  37.188 52.241 38.862 52.987 ;
     RECT  0.216 52.253 0.558 53.329 ;
     RECT  1.368 53.227 1.386 53.357 ;
     RECT  0.108 53.329 0.558 53.371 ;
     RECT  2.304 52.987 38.862 53.453 ;
     RECT  0.108 53.371 1.17 53.549 ;
     RECT  0.108 53.549 0.666 53.837 ;
     RECT  2.304 53.453 36.414 53.933 ;
     RECT  37.296 53.453 38.862 54.029 ;
     RECT  0.144 53.837 0.666 54.317 ;
     RECT  37.872 54.029 38.862 54.401 ;
     RECT  0.144 54.317 0.162 54.679 ;
     RECT  37.872 54.401 38.79 54.701 ;
     RECT  2.304 53.933 36.162 54.763 ;
     RECT  37.044 54.643 37.062 54.763 ;
     RECT  0.108 54.679 0.162 54.797 ;
     RECT  38.16 54.701 38.79 54.989 ;
     RECT  2.304 54.763 37.062 55.003 ;
     RECT  1.152 54.475 1.17 55.051 ;
     RECT  2.268 55.003 37.062 55.139 ;
     RECT  1.152 55.051 1.278 55.181 ;
     RECT  0.144 54.797 0.162 55.339 ;
     RECT  2.304 55.139 37.062 55.435 ;
     RECT  38.16 54.989 38.646 55.435 ;
     RECT  0.144 55.339 0.342 55.469 ;
     RECT  0.216 55.469 0.234 55.661 ;
     RECT  2.304 55.435 38.646 55.795 ;
     RECT  2.304 55.795 38.79 56.057 ;
     RECT  38.196 56.057 38.79 56.686 ;
     RECT  2.304 56.057 37.422 56.714 ;
     RECT  2.304 56.714 36.558 56.759 ;
     RECT  37.404 56.714 37.422 56.839 ;
     RECT  38.196 56.686 38.862 56.839 ;
     RECT  37.404 56.839 38.862 56.903 ;
     RECT  2.304 56.759 36.522 57.005 ;
     RECT  36.504 57.005 36.522 57.029 ;
     RECT  0.108 56.731 0.126 57.067 ;
     RECT  0.108 57.067 0.342 57.101 ;
     RECT  37.476 56.903 38.862 57.197 ;
     RECT  0.18 57.101 0.342 57.293 ;
     RECT  37.476 57.197 37.638 57.293 ;
     RECT  37.584 57.293 37.638 57.389 ;
     RECT  0.504 57.451 0.522 57.541 ;
     RECT  2.34 57.005 35.658 57.991 ;
     RECT  37.584 57.389 37.602 58.019 ;
     RECT  2.34 57.991 36.27 58.027 ;
     RECT  0.504 57.541 0.558 58.315 ;
     RECT  38.664 57.197 38.862 58.423 ;
     RECT  2.304 58.027 36.27 58.459 ;
     RECT  0.144 58.315 0.558 58.493 ;
     RECT  2.304 58.459 36.522 58.699 ;
     RECT  0.54 58.493 0.558 58.733 ;
     RECT  2.304 58.699 37.314 58.801 ;
     RECT  2.268 58.801 37.314 58.829 ;
     RECT  38.16 58.423 38.862 59.021 ;
     RECT  2.268 58.829 36.486 59.405 ;
     RECT  2.304 59.405 36.486 59.837 ;
     RECT  37.296 58.829 37.314 59.851 ;
     RECT  38.196 59.021 38.862 59.851 ;
     RECT  2.304 59.837 35.622 59.999 ;
     RECT  2.34 59.999 35.622 60.269 ;
     RECT  2.415 60.269 35.622 60.691 ;
     RECT  36.396 59.837 36.486 60.691 ;
     RECT  2.415 60.691 36.486 60.845 ;
     RECT  37.296 59.851 38.862 60.907 ;
     RECT  2.415 60.845 35.55 61.079 ;
     RECT  2.415 61.079 35.442 61.187 ;
     RECT  37.26 60.907 38.862 61.223 ;
     RECT  37.296 61.223 38.862 61.229 ;
     RECT  38.736 61.229 38.862 61.304 ;
     RECT  38.736 61.304 38.79 61.325 ;
     RECT  38.772 61.325 38.79 61.493 ;
     RECT  2.415 61.187 30.222 62.155 ;
     RECT  30.96 61.187 35.442 62.155 ;
     RECT  2.415 62.155 35.442 62.311 ;
     RECT  36.36 60.845 36.486 62.311 ;
     RECT  2.415 62.311 36.486 62.473 ;
     RECT  0.504 62.239 0.522 62.581 ;
     RECT  0.504 62.581 0.558 62.671 ;
     RECT  2.415 62.473 36.558 62.699 ;
     RECT  2.415 62.699 36.486 62.735 ;
     RECT  37.296 61.229 37.89 62.815 ;
     RECT  0.108 62.671 0.558 62.851 ;
     RECT  2.415 62.735 36.378 62.851 ;
     RECT  2.376 62.851 36.378 63.013 ;
     RECT  0.108 62.851 1.17 63.533 ;
     RECT  0.144 63.533 1.17 63.815 ;
     RECT  37.296 62.815 38.214 63.823 ;
     RECT  0.144 63.815 0.558 64.013 ;
     RECT  0.144 64.013 0.486 64.109 ;
     RECT  37.296 63.823 38.286 64.129 ;
     RECT  0.144 64.109 0.162 64.291 ;
     RECT  2.304 63.013 36.378 64.363 ;
     RECT  37.296 64.129 38.574 64.555 ;
     RECT  2.304 64.363 36.522 64.795 ;
     RECT  0.108 64.291 0.162 64.843 ;
     RECT  2.232 64.795 36.522 64.859 ;
     RECT  2.304 64.859 36.414 64.895 ;
     RECT  0.108 64.843 0.342 65.165 ;
     RECT  1.152 65.371 1.17 65.501 ;
     RECT  0.18 65.165 0.342 65.543 ;
     RECT  0.324 65.543 0.342 65.549 ;
     RECT  37.296 64.555 38.718 65.704 ;
     RECT  2.304 64.895 36.378 65.713 ;
     RECT  2.268 65.713 36.378 65.785 ;
     RECT  37.296 65.704 38.79 65.785 ;
     RECT  2.268 65.785 38.79 65.837 ;
     RECT  2.304 65.837 38.79 66.119 ;
     RECT  2.415 66.119 38.79 66.515 ;
     RECT  2.415 66.515 38.718 66.623 ;
     RECT  37.296 66.623 38.718 67.243 ;
     RECT  2.415 66.623 36.378 67.435 ;
     RECT  37.296 67.243 38.79 67.435 ;
     RECT  2.415 67.435 38.79 67.559 ;
     RECT  4.248 67.559 38.79 67.739 ;
     RECT  2.415 67.559 3.33 67.829 ;
     RECT  4.248 67.739 38.718 67.973 ;
     RECT  4.248 67.973 37.89 68.377 ;
     RECT  3.708 68.377 37.89 68.405 ;
     RECT  3.708 68.405 35.298 68.429 ;
     RECT  37.008 68.405 37.89 68.783 ;
     RECT  4.176 68.429 35.298 68.909 ;
     RECT  38.7 67.973 38.718 68.981 ;
     RECT  4.212 68.909 35.298 69.259 ;
     RECT  37.008 68.783 37.314 69.307 ;
     RECT  36.504 69.307 37.314 69.449 ;
     RECT  37.008 69.449 37.314 69.521 ;
     RECT  4.212 69.259 35.586 69.601 ;
     RECT  4.212 69.601 35.982 69.719 ;
     RECT  35.964 69.719 35.982 69.791 ;
     RECT  4.212 69.719 35.19 69.827 ;
     RECT  4.212 69.827 35.097 69.931 ;
     RECT  37.296 69.521 37.314 70.061 ;
     RECT  3.672 69.931 35.097 70.259 ;
     RECT  4.068 70.259 35.097 70.771 ;
     RECT  4.068 70.771 35.802 71.185 ;
     RECT  4.068 71.185 36.054 71.221 ;
     RECT  3.996 71.221 36.054 71.275 ;
     RECT  3.708 71.275 36.054 71.339 ;
     RECT  37.872 71.221 37.89 71.995 ;
     RECT  37.296 71.995 37.89 72.265 ;
     RECT  38.808 72.139 38.826 72.391 ;
     RECT  38.7 72.391 38.826 72.475 ;
     RECT  3.708 71.339 35.586 72.523 ;
     RECT  36.756 72.265 37.89 72.841 ;
     RECT  2.415 67.829 2.697 72.931 ;
     RECT  3.708 72.523 35.622 72.931 ;
     RECT  36.576 72.841 37.89 72.931 ;
     RECT  38.7 72.475 38.862 73.111 ;
     RECT  2.415 72.931 37.89 73.535 ;
     RECT  33.624 73.535 37.89 73.615 ;
     RECT  33.624 73.615 37.926 73.853 ;
     RECT  33.66 73.853 37.926 73.867 ;
     RECT  38.664 73.111 38.862 73.867 ;
     RECT  2.415 73.535 32.886 74.623 ;
     RECT  33.66 73.867 38.862 74.623 ;
     RECT  0.504 75.631 0.522 75.703 ;
     RECT  0.504 75.703 1.17 75.803 ;
     RECT  0.504 75.803 0.558 75.917 ;
     RECT  2.415 74.623 38.862 75.973 ;
     RECT  2.304 75.973 38.862 76.081 ;
     RECT  2.268 76.081 38.862 76.205 ;
     RECT  0.504 75.917 0.522 76.363 ;
     RECT  0.144 76.363 0.522 76.541 ;
     RECT  0.18 76.541 0.522 76.711 ;
     RECT  0.18 76.711 0.558 76.847 ;
     RECT  0.324 76.847 0.558 76.877 ;
     RECT  2.304 76.205 38.862 77.053 ;
     RECT  2.232 77.053 38.862 77.131 ;
     RECT  1.98 77.131 38.862 77.261 ;
     RECT  2.232 77.261 38.862 77.279 ;
     RECT  0.504 76.877 0.558 77.851 ;
     RECT  2.268 77.279 38.862 77.855 ;
     RECT  0.144 77.851 0.558 78.029 ;
     RECT  0.216 78.029 0.558 78.125 ;
     RECT  0.216 78.125 0.522 78.317 ;
     RECT  1.26 78.379 1.278 78.509 ;
     RECT  0.216 78.317 0.486 78.859 ;
     RECT  0.18 78.859 0.486 79.051 ;
     RECT  2.304 77.855 38.862 79.051 ;
     RECT  0.18 79.051 0.522 79.141 ;
     RECT  1.98 79.051 38.862 79.277 ;
     RECT  0.18 79.141 0.558 79.915 ;
     RECT  2.304 79.277 38.862 80.015 ;
     RECT  0.144 79.915 0.558 80.093 ;
     RECT  0.36 80.093 0.558 80.237 ;
     RECT  2.304 80.015 38.79 80.491 ;
     RECT  2.268 80.491 38.79 80.525 ;
     RECT  0.36 80.237 0.522 80.717 ;
     RECT  2.268 80.525 36.342 81.005 ;
     RECT  37.332 80.525 38.79 81.101 ;
     RECT  37.872 81.101 38.79 81.115 ;
     RECT  37.872 81.115 38.862 81.197 ;
     RECT  0.36 80.717 0.45 81.307 ;
     RECT  0.144 81.307 0.45 81.485 ;
     RECT  38.16 81.197 38.862 81.677 ;
     RECT  2.304 81.005 36.342 81.913 ;
     RECT  0.504 81.913 0.522 82.021 ;
     RECT  2.304 81.913 37.062 82.061 ;
     RECT  0.504 82.021 0.558 82.157 ;
     RECT  2.304 82.061 36.162 82.175 ;
     RECT  37.044 82.061 37.062 82.253 ;
     RECT  38.196 81.677 38.862 82.795 ;
     RECT  0.504 82.157 0.522 82.891 ;
     RECT  2.304 82.175 35.946 82.987 ;
     RECT  0.144 82.891 0.522 82.993 ;
     RECT  0.144 82.993 0.558 83.065 ;
     RECT  37.584 82.795 38.862 83.065 ;
     RECT  2.304 82.987 36.054 83.179 ;
     RECT  2.268 83.179 36.054 83.461 ;
     RECT  37.044 83.065 38.862 83.461 ;
     RECT  2.268 83.461 38.862 83.659 ;
     RECT  1.98 83.659 38.862 83.789 ;
     RECT  2.304 83.789 38.862 83.795 ;
     RECT  2.304 83.795 37.062 83.981 ;
     RECT  2.304 83.981 37.026 84.029 ;
     RECT  0.108 83.065 0.558 84.173 ;
     RECT  28.152 84.029 37.026 84.209 ;
     RECT  38.16 83.795 38.862 84.254 ;
     RECT  28.152 84.209 36.522 84.365 ;
     RECT  2.304 84.029 27.414 84.811 ;
     RECT  28.152 84.365 35.946 84.811 ;
     RECT  2.268 84.811 35.946 84.941 ;
     RECT  38.16 84.254 38.79 85.099 ;
     RECT  0.54 84.173 0.558 85.133 ;
     RECT  37.476 85.099 38.79 85.253 ;
     RECT  0.18 85.189 0.342 85.291 ;
     RECT  2.268 84.941 35.766 85.387 ;
     RECT  37.584 85.253 38.79 85.423 ;
     RECT  2.232 85.387 35.766 85.483 ;
     RECT  2.124 85.483 35.766 85.523 ;
     RECT  0.144 85.291 0.342 85.709 ;
     RECT  2.304 85.523 35.766 85.801 ;
     RECT  0.144 85.709 0.234 85.891 ;
     RECT  2.304 85.801 35.838 85.891 ;
     RECT  0.108 85.891 0.234 85.901 ;
     RECT  37.584 85.423 38.862 86.093 ;
     RECT  0.108 85.901 0.198 86.189 ;
     RECT  2.304 85.891 35.91 86.305 ;
     RECT  2.304 86.305 36.486 86.443 ;
     RECT  0.18 86.189 0.198 86.477 ;
     RECT  2.304 86.443 36.522 86.731 ;
     RECT  38.196 86.093 38.862 86.765 ;
     RECT  2.232 86.731 36.522 86.971 ;
     RECT  2.196 86.971 36.522 86.999 ;
     RECT  37.548 86.827 37.566 87.071 ;
     RECT  2.196 86.999 35.874 87.539 ;
     RECT  0.324 87.019 0.342 87.629 ;
     RECT  38.556 86.765 38.862 87.961 ;
     RECT  2.304 87.539 35.874 88.079 ;
     RECT  2.415 88.079 35.874 88.123 ;
     RECT  36.972 87.211 36.99 88.195 ;
     RECT  38.196 87.961 38.862 88.195 ;
     RECT  2.415 88.123 36.018 88.349 ;
     RECT  36.972 88.195 38.862 88.397 ;
     RECT  36.972 88.397 37.026 88.421 ;
     RECT  2.415 88.349 35.73 88.493 ;
     RECT  2.415 88.493 35.334 89.311 ;
     RECT  37.008 88.421 37.026 89.339 ;
     RECT  38.088 88.397 38.862 89.419 ;
     RECT  2.415 89.311 35.694 89.465 ;
     RECT  37.548 89.419 38.862 89.501 ;
     RECT  38.232 89.501 38.862 89.549 ;
     RECT  38.736 89.549 38.862 89.645 ;
     RECT  38.772 89.645 38.862 89.735 ;
     RECT  38.772 89.735 38.79 89.744 ;
     RECT  2.415 89.465 35.097 90.851 ;
     RECT  36.216 89.581 36.234 90.959 ;
     RECT  2.415 90.851 33.822 91.355 ;
     RECT  2.415 91.355 33.75 91.427 ;
     RECT  2.415 91.427 33.714 91.901 ;
     RECT  3.42 91.901 33.714 92.003 ;
     RECT  3.42 92.003 33.642 92.129 ;
     RECT  6.804 92.129 20.286 92.243 ;
     RECT  21.06 92.129 33.642 92.273 ;
     RECT  21.06 92.273 22.266 92.399 ;
     RECT  23.148 92.273 33.642 92.399 ;
     RECT  23.148 92.399 32.814 92.429 ;
     RECT  3.708 92.129 5.994 92.435 ;
     RECT  6.804 92.243 20.142 92.435 ;
     RECT  21.168 92.399 22.266 92.435 ;
     RECT  30.528 92.429 32.814 92.435 ;
     RECT  23.148 92.429 29.697 92.477 ;
     RECT  23.148 92.477 26.997 92.507 ;
     RECT  6.804 92.435 16.938 92.543 ;
     RECT  23.4 92.507 26.997 92.543 ;
     RECT  33.624 92.399 33.642 92.543 ;
     RECT  17.712 92.435 19.962 92.579 ;
     RECT  2.415 91.901 2.697 92.627 ;
     RECT  21.315 92.435 21.597 92.627 ;
     RECT  25.92 92.543 26.997 92.627 ;
     RECT  28.152 92.477 29.697 92.627 ;
     RECT  34.815 90.851 35.097 92.627 ;
     RECT  4.032 92.435 5.994 92.669 ;
     RECT  7.128 92.543 16.938 92.669 ;
     RECT  17.712 92.579 19.494 92.669 ;
     RECT  25.92 92.627 26.805 92.669 ;
     RECT  30.528 92.435 32.778 92.669 ;
     RECT  4.176 92.669 5.922 92.705 ;
     RECT  8.676 92.669 10.89 92.705 ;
     RECT  13.032 92.669 16.938 92.705 ;
     RECT  17.712 92.669 19.386 92.705 ;
     RECT  23.4 92.543 24.858 92.705 ;
     RECT  28.152 92.627 29.538 92.705 ;
     RECT  30.78 92.669 32.67 92.705 ;
     RECT  13.032 92.705 13.59 92.717 ;
     RECT  4.176 92.705 5.274 92.741 ;
     RECT  30.78 92.705 32.205 92.741 ;
     RECT  4.824 92.741 5.274 92.777 ;
     RECT  13.104 92.717 13.554 92.777 ;
     RECT  17.892 92.705 19.386 92.777 ;
     RECT  23.616 92.705 24.105 92.777 ;
     RECT  28.404 92.705 29.505 92.777 ;
     RECT  4.824 92.777 5.205 92.813 ;
     RECT  7.128 92.669 7.905 92.813 ;
     RECT  8.676 92.705 8.694 92.813 ;
     RECT  10.515 92.705 10.89 92.813 ;
     RECT  11.772 92.669 12.222 92.813 ;
     RECT  13.104 92.777 13.446 92.813 ;
     RECT  9.684 92.705 9.702 92.849 ;
     RECT  10.515 92.813 10.674 92.849 ;
     RECT  13.176 92.813 13.446 92.849 ;
     RECT  14.868 92.705 16.47 92.849 ;
     RECT  17.892 92.777 18.705 92.849 ;
     RECT  23.94 92.777 24.105 92.849 ;
     RECT  29.196 92.777 29.505 92.849 ;
     RECT  31.428 92.741 32.205 92.849 ;
     RECT  2.415 92.627 2.505 92.897 ;
     RECT  5.115 92.813 5.205 92.897 ;
     RECT  7.815 92.813 7.905 92.897 ;
     RECT  10.515 92.849 10.605 92.897 ;
     RECT  13.215 92.849 13.305 92.897 ;
     RECT  15.264 92.849 16.005 92.897 ;
     RECT  18.615 92.849 18.705 92.897 ;
     RECT  21.315 92.627 21.405 92.897 ;
     RECT  24.015 92.849 24.105 92.897 ;
     RECT  26.715 92.669 26.805 92.897 ;
     RECT  29.415 92.849 29.505 92.897 ;
     RECT  32.115 92.849 32.205 92.897 ;
     RECT  34.815 92.627 34.905 92.897 ;
     RECT  15.264 92.897 15.282 95.021 ;
    LAYER M4 ;
     RECT  0.06 24.432 0.097 30.504 ;
     RECT  0.06 49.584 0.137 59.688 ;
     RECT  0.137 49.68 0.569 59.688 ;
     RECT  0.06 75.888 0.569 88.104 ;
     RECT  0.06 11.376 1.181 21.288 ;
     RECT  0.06 2.16 2.293 5.16 ;
     RECT  0.569 49.872 2.293 59.688 ;
     RECT  2.293 2.16 2.408 5.256 ;
     RECT  2.365 6.672 2.408 6.696 ;
     RECT  2.293 7.968 2.408 7.992 ;
     RECT  2.252 9.12 2.408 9.144 ;
     RECT  2.401 10.176 2.408 10.2 ;
     RECT  1.181 11.376 2.408 17.448 ;
     RECT  1.181 18.48 2.408 21.288 ;
     RECT  0.097 24.432 2.408 30.6 ;
     RECT  0.06 37.488 2.408 43.56 ;
     RECT  2.401 44.976 2.408 45 ;
     RECT  0.133 46.8 2.408 46.824 ;
     RECT  2.293 49.776 2.408 59.688 ;
     RECT  0.06 62.832 2.408 65.832 ;
     RECT  0.569 76.08 2.408 88.104 ;
     RECT  2.408 2.148 2.512 92.892 ;
     RECT  2.512 2.256 2.704 92.622 ;
     RECT  2.704 24.432 2.765 30.6 ;
     RECT  2.704 11.424 3.089 22.248 ;
     RECT  3.089 11.424 3.203 20.952 ;
     RECT  2.704 62.16 3.347 66.744 ;
     RECT  3.347 62.16 3.449 65.544 ;
     RECT  2.704 35.424 3.685 43.656 ;
     RECT  2.704 44.736 3.685 45 ;
     RECT  2.704 72.96 3.697 72.984 ;
     RECT  2.704 74.928 3.697 88.968 ;
     RECT  2.704 91.152 3.697 91.896 ;
     RECT  2.704 31.776 3.733 32.76 ;
     RECT  2.704 46.704 3.733 61.032 ;
     RECT  3.449 62.16 3.733 63.528 ;
     RECT  3.347 66.72 3.733 66.744 ;
     RECT  3.697 68.4 3.781 68.424 ;
     RECT  2.704 69.936 3.827 69.96 ;
     RECT  3.089 21.936 3.836 22.248 ;
     RECT  2.704 23.328 3.836 23.352 ;
     RECT  3.697 72.96 3.877 88.968 ;
     RECT  3.697 71.28 3.925 71.304 ;
     RECT  2.704 2.256 3.985 10.344 ;
     RECT  3.203 11.424 3.985 17.256 ;
     RECT  3.733 31.776 4.057 33.096 ;
     RECT  3.769 34.224 4.057 34.248 ;
     RECT  3.685 35.424 4.057 45 ;
     RECT  2.765 24.624 4.093 30.408 ;
     RECT  4.057 31.776 4.093 45 ;
     RECT  3.697 91.152 4.093 92.424 ;
     RECT  3.985 2.256 4.097 17.256 ;
     RECT  3.733 66.72 4.129 66.84 ;
     RECT  3.925 71.232 4.129 71.304 ;
     RECT  3.877 72.672 4.201 88.968 ;
     RECT  3.203 18.48 4.213 20.952 ;
     RECT  3.836 21.936 4.213 23.352 ;
     RECT  4.097 8.496 4.237 17.256 ;
     RECT  4.213 18.48 4.237 23.352 ;
     RECT  4.237 8.496 4.345 23.352 ;
     RECT  3.733 46.704 4.345 63.528 ;
     RECT  3.781 68.4 4.345 68.664 ;
     RECT  4.345 46.224 4.412 63.528 ;
     RECT  3.449 64.656 4.412 65.544 ;
     RECT  4.412 46.224 4.525 65.544 ;
     RECT  4.129 66.72 4.525 67.128 ;
     RECT  4.093 24.624 4.633 45 ;
     RECT  4.525 46.224 4.633 67.128 ;
     RECT  4.129 70.848 4.669 71.304 ;
     RECT  4.201 72.672 4.669 89.016 ;
     RECT  4.093 90.528 4.669 92.424 ;
     RECT  4.345 8.496 4.705 23.4 ;
     RECT  4.633 24.624 4.705 67.128 ;
     RECT  4.669 90.528 4.741 92.472 ;
     RECT  4.345 68.208 4.921 69.528 ;
     RECT  4.705 8.496 5.029 67.128 ;
     RECT  4.921 68.208 5.029 69.576 ;
     RECT  4.669 70.848 5.065 89.016 ;
     RECT  4.097 2.256 5.108 7.416 ;
     RECT  5.029 8.496 5.108 69.576 ;
     RECT  5.065 70.8 5.108 89.016 ;
     RECT  4.741 90.336 5.108 92.472 ;
     RECT  5.108 2.148 5.212 92.892 ;
     RECT  5.212 2.352 5.404 92.622 ;
     RECT  5.404 2.352 5.573 91.992 ;
     RECT  5.573 2.352 5.681 69.576 ;
     RECT  5.573 70.608 5.725 91.8 ;
     RECT  5.681 2.64 5.897 69.576 ;
     RECT  5.725 70.608 6.041 91.704 ;
     RECT  6.041 72.528 6.323 91.704 ;
     RECT  5.897 8.736 6.545 69.576 ;
     RECT  6.323 81.36 6.793 91.704 ;
     RECT  6.545 20.88 6.937 69.576 ;
     RECT  6.041 70.608 6.937 71.4 ;
     RECT  6.937 20.88 7.009 71.4 ;
     RECT  6.323 72.528 7.009 80.376 ;
     RECT  5.897 2.64 7.081 7.128 ;
     RECT  6.545 8.736 7.081 19.848 ;
     RECT  7.081 2.64 7.261 19.848 ;
     RECT  7.009 20.88 7.628 80.376 ;
     RECT  6.793 81.36 7.628 92.52 ;
     RECT  7.261 2.496 7.657 19.848 ;
     RECT  7.628 20.88 7.657 92.52 ;
     RECT  7.657 2.496 7.808 92.52 ;
     RECT  7.808 2.148 7.912 92.892 ;
     RECT  7.912 2.256 8.104 92.622 ;
     RECT  8.104 70.8 8.129 92.424 ;
     RECT  8.104 2.256 8.531 69.816 ;
     RECT  8.531 2.352 8.597 69.816 ;
     RECT  8.597 2.352 8.741 61.416 ;
     RECT  8.129 76.8 9.169 92.424 ;
     RECT  8.129 70.8 9.241 75.816 ;
     RECT  9.169 76.8 9.241 92.52 ;
     RECT  8.741 48.144 9.637 61.416 ;
     RECT  8.597 62.4 9.637 69.816 ;
     RECT  8.741 2.352 9.817 47.16 ;
     RECT  9.637 48.144 9.817 69.816 ;
     RECT  9.817 2.352 10.508 69.816 ;
     RECT  9.241 70.8 10.508 92.52 ;
     RECT  10.508 2.148 10.612 92.892 ;
     RECT  10.612 2.352 10.804 92.622 ;
     RECT  10.804 2.352 11.081 21.528 ;
     RECT  10.804 22.704 11.117 43.56 ;
     RECT  11.077 94.704 11.219 94.92 ;
     RECT  11.219 94.896 11.269 94.92 ;
     RECT  11.269 94.896 11.315 95.016 ;
     RECT  11.081 2.4 11.333 21.528 ;
     RECT  11.333 2.496 11.477 21.528 ;
     RECT  10.804 44.928 11.585 92.622 ;
     RECT  11.585 44.976 11.717 92.622 ;
     RECT  11.717 44.976 11.801 92.808 ;
     RECT  11.117 22.704 11.869 22.872 ;
     RECT  11.477 2.592 11.953 21.528 ;
     RECT  11.869 22.608 12.157 22.872 ;
     RECT  11.117 23.904 12.157 43.56 ;
     RECT  12.157 22.608 12.193 43.56 ;
     RECT  11.953 9.84 12.229 21.528 ;
     RECT  12.193 22.608 12.229 43.656 ;
     RECT  12.229 9.84 12.301 43.656 ;
     RECT  12.301 9.84 13.021 43.848 ;
     RECT  11.801 44.976 13.021 92.376 ;
     RECT  11.953 2.592 13.208 8.76 ;
     RECT  13.021 9.84 13.208 92.712 ;
     RECT  13.208 2.148 13.312 92.892 ;
     RECT  13.312 2.418 13.504 92.712 ;
     RECT  13.504 71.136 13.601 92.712 ;
     RECT  13.504 46.176 13.756 69.816 ;
     RECT  13.504 2.418 14.321 45 ;
     RECT  14.321 2.418 14.389 44.904 ;
     RECT  13.756 46.224 14.501 69.816 ;
     RECT  13.601 71.136 14.579 91.896 ;
     RECT  14.579 71.184 14.681 91.896 ;
     RECT  14.681 71.664 14.86 91.896 ;
     RECT  14.86 91.632 14.861 91.896 ;
     RECT  11.315 94.992 15.293 95.016 ;
     RECT  14.501 69.792 15.397 69.816 ;
     RECT  14.501 46.224 15.605 68.76 ;
     RECT  15.397 69.792 15.605 70.104 ;
     RECT  14.389 2.256 15.637 44.904 ;
     RECT  15.605 46.224 15.637 70.104 ;
     RECT  15.637 2.256 15.908 70.104 ;
     RECT  14.86 71.664 15.908 90.504 ;
     RECT  14.861 91.632 15.908 91.8 ;
     RECT  15.908 2.148 16.012 92.892 ;
     RECT  16.012 2.304 16.204 92.622 ;
     RECT  16.204 71.712 16.547 92.424 ;
     RECT  16.204 2.304 16.553 70.728 ;
     RECT  16.547 71.856 16.625 92.424 ;
     RECT  16.553 2.544 16.733 35.304 ;
     RECT  16.553 36.528 16.797 70.728 ;
     RECT  16.797 37.008 17.309 70.728 ;
     RECT  16.733 2.544 17.417 34.776 ;
     RECT  16.625 71.856 17.633 75.72 ;
     RECT  17.417 22.752 18.205 34.776 ;
     RECT  18.205 22.752 18.277 35.256 ;
     RECT  17.417 2.544 18.608 21.672 ;
     RECT  18.277 22.752 18.608 36.12 ;
     RECT  17.309 37.104 18.608 70.728 ;
     RECT  17.633 71.952 18.608 75.72 ;
     RECT  16.625 76.944 18.608 92.424 ;
     RECT  18.608 2.148 18.712 92.892 ;
     RECT  18.712 2.418 18.904 92.622 ;
     RECT  18.904 8.496 19.829 22.776 ;
     RECT  19.829 8.496 19.865 18.984 ;
     RECT  18.904 2.64 19.933 7.224 ;
     RECT  19.865 8.496 19.933 18.84 ;
     RECT  19.829 20.112 19.933 22.776 ;
     RECT  18.904 23.856 19.933 25.272 ;
     RECT  19.933 20.112 19.957 25.272 ;
     RECT  18.904 26.544 19.957 91.224 ;
     RECT  19.957 20.112 20.045 91.224 ;
     RECT  20.045 91.056 20.257 91.224 ;
     RECT  18.904 92.208 20.257 92.232 ;
     RECT  20.257 91.056 20.297 92.232 ;
     RECT  19.933 2.64 20.636 18.84 ;
     RECT  20.045 20.112 20.869 90.072 ;
     RECT  20.869 19.968 21.049 90.072 ;
     RECT  20.297 91.056 21.049 91.992 ;
     RECT  20.636 2.256 21.301 18.84 ;
     RECT  21.049 19.968 21.301 91.992 ;
     RECT  21.301 2.256 21.308 91.992 ;
     RECT  21.308 2.148 21.412 92.892 ;
     RECT  21.412 2.418 21.604 92.622 ;
     RECT  21.604 2.784 21.737 34.728 ;
     RECT  21.604 35.712 22.025 45.048 ;
     RECT  21.737 2.784 22.061 22.008 ;
     RECT  22.061 2.784 22.241 21.24 ;
     RECT  21.604 70.896 22.259 92.136 ;
     RECT  22.259 92.112 22.349 92.136 ;
     RECT  22.025 35.712 22.529 45 ;
     RECT  22.241 2.832 22.745 21.24 ;
     RECT  21.604 46.224 22.777 69.864 ;
     RECT  22.259 70.896 22.777 90.6 ;
     RECT  22.529 35.712 23.033 44.904 ;
     RECT  22.745 9.84 23.065 21.24 ;
     RECT  22.745 2.832 23.245 8.808 ;
     RECT  23.065 9.84 23.557 21.576 ;
     RECT  21.737 23.136 23.557 34.728 ;
     RECT  23.033 35.712 23.557 44.184 ;
     RECT  22.777 46.224 23.893 90.6 ;
     RECT  23.245 2.256 24.008 8.808 ;
     RECT  23.557 9.84 24.008 44.184 ;
     RECT  23.569 45.168 24.008 45.192 ;
     RECT  23.893 46.224 24.008 90.648 ;
     RECT  23.173 92.448 24.008 92.472 ;
     RECT  24.008 2.148 24.112 92.892 ;
     RECT  24.112 2.256 24.304 92.622 ;
     RECT  24.304 2.256 24.581 61.224 ;
     RECT  24.304 62.496 24.604 92.04 ;
     RECT  24.581 26.544 24.689 61.224 ;
     RECT  24.581 2.256 24.833 25.464 ;
     RECT  24.833 2.784 25.337 25.464 ;
     RECT  24.604 70.848 25.373 92.04 ;
     RECT  25.337 20.928 25.445 25.464 ;
     RECT  24.689 26.688 25.549 61.224 ;
     RECT  25.337 2.784 25.553 19.848 ;
     RECT  25.445 20.976 25.621 25.464 ;
     RECT  25.373 70.848 25.66 90.792 ;
     RECT  25.621 20.976 25.873 25.656 ;
     RECT  25.549 26.688 25.873 61.416 ;
     RECT  24.604 62.496 26.089 69.816 ;
     RECT  25.553 3.024 26.485 19.848 ;
     RECT  25.873 20.976 26.485 61.416 ;
     RECT  25.66 70.848 26.629 70.872 ;
     RECT  25.66 71.952 26.629 90.792 ;
     RECT  26.485 3.024 26.665 61.416 ;
     RECT  26.665 3.024 26.708 61.464 ;
     RECT  26.089 62.448 26.708 69.816 ;
     RECT  26.629 70.848 26.708 90.792 ;
     RECT  25.373 92.016 26.708 92.04 ;
     RECT  26.708 2.148 26.812 92.892 ;
     RECT  26.812 2.256 27.004 92.622 ;
     RECT  27.004 2.256 27.029 18.6 ;
     RECT  27.004 36.096 27.065 70.68 ;
     RECT  27.065 36.24 27.155 70.68 ;
     RECT  27.155 43.296 27.173 70.68 ;
     RECT  27.004 71.76 27.353 91.32 ;
     RECT  27.004 19.584 27.425 35.016 ;
     RECT  27.353 71.76 27.628 90.072 ;
     RECT  27.628 71.952 27.785 90.072 ;
     RECT  27.173 43.296 27.813 70.152 ;
     RECT  27.425 19.584 27.929 21.96 ;
     RECT  27.425 23.04 27.929 35.016 ;
     RECT  27.929 21.504 27.965 21.816 ;
     RECT  27.029 2.256 28.033 2.808 ;
     RECT  27.029 3.84 28.033 18.6 ;
     RECT  28.033 2.256 28.141 18.6 ;
     RECT  27.929 19.584 28.141 20.328 ;
     RECT  27.155 36.24 28.177 42.216 ;
     RECT  27.813 43.296 28.177 61.464 ;
     RECT  28.141 2.256 28.289 20.328 ;
     RECT  27.929 23.712 28.321 35.016 ;
     RECT  27.785 71.952 28.681 79.608 ;
     RECT  28.681 71.664 28.741 79.608 ;
     RECT  27.353 91.296 28.753 91.32 ;
     RECT  27.004 92.448 28.753 92.472 ;
     RECT  28.177 36.24 28.817 61.464 ;
     RECT  27.813 62.496 28.817 70.152 ;
     RECT  28.321 23.712 29.005 35.064 ;
     RECT  28.817 36.24 29.005 70.152 ;
     RECT  28.741 71.232 29.113 79.608 ;
     RECT  28.289 9.84 29.125 20.328 ;
     RECT  27.965 21.792 29.125 21.816 ;
     RECT  29.005 23.712 29.293 70.152 ;
     RECT  29.113 71.184 29.293 79.608 ;
     RECT  28.289 2.256 29.408 8.808 ;
     RECT  29.125 9.84 29.408 21.816 ;
     RECT  29.293 23.712 29.408 79.608 ;
     RECT  27.785 80.64 29.408 90.072 ;
     RECT  28.753 91.296 29.408 92.472 ;
     RECT  29.408 2.148 29.512 92.892 ;
     RECT  29.512 2.304 29.704 92.622 ;
     RECT  29.704 2.304 29.765 19.8 ;
     RECT  29.704 46.224 29.981 50.04 ;
     RECT  29.704 20.928 30.053 45.048 ;
     RECT  30.053 25.104 30.413 45.048 ;
     RECT  30.053 20.928 30.593 24.12 ;
     RECT  29.704 51.312 30.593 60.936 ;
     RECT  30.413 25.104 30.629 44.472 ;
     RECT  29.981 46.224 30.709 49.848 ;
     RECT  30.593 51.408 30.733 60.936 ;
     RECT  30.593 20.928 30.881 23.976 ;
     RECT  30.629 25.296 30.989 44.472 ;
     RECT  30.733 51.408 31.021 61.176 ;
     RECT  29.704 62.16 31.021 90.6 ;
     RECT  31.021 51.408 31.061 90.6 ;
     RECT  29.704 91.776 31.093 92.424 ;
     RECT  29.765 2.88 31.196 19.8 ;
     RECT  30.881 20.928 31.196 21.144 ;
     RECT  30.989 25.776 31.381 44.472 ;
     RECT  30.709 45.6 31.381 49.848 ;
     RECT  31.381 25.776 31.669 49.848 ;
     RECT  31.669 25.776 31.849 50.136 ;
     RECT  31.061 51.408 31.849 69.816 ;
     RECT  31.196 2.88 31.957 21.144 ;
     RECT  31.849 25.776 32.029 69.816 ;
     RECT  31.061 70.8 32.029 90.6 ;
     RECT  31.957 2.832 32.108 21.144 ;
     RECT  30.881 22.464 32.108 23.976 ;
     RECT  32.029 25.776 32.108 90.6 ;
     RECT  31.093 91.728 32.108 92.424 ;
     RECT  32.108 2.148 32.212 92.892 ;
     RECT  32.212 2.418 32.404 92.622 ;
     RECT  32.404 64.416 32.465 90.6 ;
     RECT  32.404 2.832 32.537 20.952 ;
     RECT  32.537 3.696 32.681 20.952 ;
     RECT  32.404 37.44 32.861 63.336 ;
     RECT  32.404 24.384 33.005 36.264 ;
     RECT  32.861 37.44 33.113 63.288 ;
     RECT  32.465 64.416 33.185 90.36 ;
     RECT  33.185 64.416 33.257 90.024 ;
     RECT  32.404 22.032 33.505 22.056 ;
     RECT  32.404 23.04 33.505 23.352 ;
     RECT  33.505 22.032 33.644 23.352 ;
     RECT  32.681 3.696 33.685 20.184 ;
     RECT  33.644 21.552 33.685 23.352 ;
     RECT  33.257 64.416 33.721 89.544 ;
     RECT  33.685 3.696 33.731 23.352 ;
     RECT  33.005 24.384 34.297 28.776 ;
     RECT  33.005 29.76 34.297 36.264 ;
     RECT  34.297 24.384 34.369 36.264 ;
     RECT  33.113 37.44 34.369 63.096 ;
     RECT  34.369 24.384 34.405 63.096 ;
     RECT  33.721 64.368 34.405 89.544 ;
     RECT  33.731 22.032 34.477 23.352 ;
     RECT  34.405 24.384 34.477 89.544 ;
     RECT  33.731 3.696 34.808 20.952 ;
     RECT  34.477 22.032 34.808 89.544 ;
     RECT  34.808 2.148 34.912 92.892 ;
     RECT  34.912 2.418 35.104 92.622 ;
     RECT  35.104 4.752 35.165 7.368 ;
     RECT  35.104 62.16 35.165 62.52 ;
     RECT  35.104 8.544 35.201 36.072 ;
     RECT  35.104 50.736 35.219 60.888 ;
     RECT  35.104 72.144 35.219 89.256 ;
     RECT  35.104 37.44 35.237 42.84 ;
     RECT  35.104 44.16 35.237 49.56 ;
     RECT  35.104 63.648 35.267 68.232 ;
     RECT  35.201 8.544 35.273 20.712 ;
     RECT  35.219 54.624 35.273 60.888 ;
     RECT  35.273 8.544 35.309 20.424 ;
     RECT  35.219 50.736 35.309 53.64 ;
     RECT  35.267 63.888 35.309 67.944 ;
     RECT  35.201 22.032 35.363 36.072 ;
     RECT  35.309 8.832 35.381 20.424 ;
     RECT  35.363 31.632 35.389 36.072 ;
     RECT  35.165 62.208 35.417 62.52 ;
     RECT  35.219 78.192 35.417 89.256 ;
     RECT  35.381 9.84 35.453 20.424 ;
     RECT  35.237 44.16 35.453 49.32 ;
     RECT  35.453 9.888 35.489 20.424 ;
     RECT  35.453 44.16 35.489 46.584 ;
     RECT  35.489 9.888 35.525 20.184 ;
     RECT  35.417 78.192 35.561 81.96 ;
     RECT  35.525 9.888 35.597 19.656 ;
     RECT  35.389 31.632 35.597 35.832 ;
     RECT  35.417 62.496 35.597 62.52 ;
     RECT  35.309 64.32 35.597 67.944 ;
     RECT  35.363 22.032 35.603 30.6 ;
     RECT  35.603 23.184 35.633 24.264 ;
     RECT  35.603 25.68 35.633 30.6 ;
     RECT  35.237 37.44 35.633 42.168 ;
     RECT  35.219 72.144 35.633 76.824 ;
     RECT  35.603 22.176 35.644 22.2 ;
     RECT  35.633 23.328 35.644 24.264 ;
     RECT  35.633 25.68 35.644 25.704 ;
     RECT  35.644 24.144 35.669 24.264 ;
     RECT  35.273 54.672 35.669 60.888 ;
     RECT  35.633 74.88 35.669 76.824 ;
     RECT  35.669 24.24 35.705 24.264 ;
     RECT  35.597 31.728 35.705 35.832 ;
     RECT  35.597 64.32 35.705 66.888 ;
     RECT  35.597 67.92 35.705 67.944 ;
     RECT  35.633 72.144 35.705 73.896 ;
     RECT  35.669 58.128 35.777 60.888 ;
     RECT  35.633 26.832 35.849 30.456 ;
     RECT  35.849 26.832 35.957 28.2 ;
     RECT  35.489 45.408 35.993 46.584 ;
     RECT  35.957 26.832 36.065 27.864 ;
     RECT  35.633 37.44 36.065 41.784 ;
     RECT  35.381 8.832 36.101 8.856 ;
     RECT  35.669 76.032 36.173 76.824 ;
     RECT  36.065 27.12 36.245 27.864 ;
     RECT  35.165 6.336 36.349 7.368 ;
     RECT  35.777 58.32 36.349 60.888 ;
     RECT  35.309 51.408 36.385 53.64 ;
     RECT  35.669 54.672 36.385 57.096 ;
     RECT  35.561 78.384 36.493 81.96 ;
     RECT  35.417 82.944 36.493 89.256 ;
     RECT  35.104 69.312 36.533 69.816 ;
     RECT  36.173 76.512 36.533 76.824 ;
     RECT  35.849 29.808 36.997 30.456 ;
     RECT  36.065 37.968 36.997 41.784 ;
     RECT  35.705 64.416 36.997 66.888 ;
     RECT  36.997 29.808 37.033 30.696 ;
     RECT  35.705 31.728 37.033 35.016 ;
     RECT  35.993 46.032 37.033 46.584 ;
     RECT  35.453 47.712 37.033 49.32 ;
     RECT  36.493 78.384 37.033 89.256 ;
     RECT  37.033 78.192 37.285 89.256 ;
     RECT  37.285 77.904 37.357 89.256 ;
     RECT  36.385 51.408 37.465 57.096 ;
     RECT  37.357 77.616 37.537 89.256 ;
     RECT  36.349 6.336 37.573 8.136 ;
     RECT  37.465 51.408 37.573 57.288 ;
     RECT  36.349 58.32 37.573 61.032 ;
     RECT  37.537 77.616 37.897 89.448 ;
     RECT  37.573 6.336 38.185 8.52 ;
     RECT  35.597 9.888 38.185 18.984 ;
     RECT  37.033 29.136 38.185 35.016 ;
     RECT  36.997 37.968 38.185 41.832 ;
     RECT  37.573 51.408 38.185 61.032 ;
     RECT  37.897 77.52 38.221 89.448 ;
     RECT  35.669 74.88 38.513 74.904 ;
     RECT  38.185 29.136 38.581 35.112 ;
     RECT  38.185 37.968 38.581 41.928 ;
     RECT  38.581 37.968 38.585 42.12 ;
     RECT  36.533 76.512 38.621 76.536 ;
     RECT  35.705 73.872 38.657 73.896 ;
     RECT  36.997 64.416 38.723 67.464 ;
     RECT  38.185 51.408 38.725 61.224 ;
     RECT  38.221 77.52 38.725 89.544 ;
     RECT  35.165 4.752 38.729 4.776 ;
     RECT  38.185 6.336 38.761 18.984 ;
     RECT  38.725 77.52 38.761 89.64 ;
     RECT  36.533 69.792 38.771 69.816 ;
     RECT  36.245 27.12 38.801 27.144 ;
     RECT  38.585 37.968 38.801 37.992 ;
     RECT  35.489 44.16 38.801 44.184 ;
     RECT  37.033 45.264 38.801 49.32 ;
     RECT  35.705 72.144 38.837 72.504 ;
     RECT  38.761 6.336 38.844 19.08 ;
     RECT  38.581 29.136 38.844 35.208 ;
     RECT  38.585 39.12 38.844 42.12 ;
     RECT  38.801 45.264 38.844 48.744 ;
     RECT  38.725 51.408 38.844 61.32 ;
     RECT  38.723 64.464 38.844 67.464 ;
     RECT  38.761 77.52 38.844 89.736 ;
     RECT  38.844 6.336 38.873 6.36 ;
     RECT  38.844 32.544 38.873 32.568 ;
     RECT  38.844 41.76 38.873 41.784 ;
     RECT  38.844 48.72 38.873 48.744 ;
     RECT  38.837 72.48 38.873 72.504 ;
     RECT  38.844 78.624 38.873 78.648 ;
     RECT  38.844 81.12 38.873 81.144 ;
    LAYER M5 ;
     RECT  2.4 2.137 2.52 2.151 ;
     RECT  5.1 2.137 5.22 2.151 ;
     RECT  7.8 2.137 7.92 2.151 ;
     RECT  10.5 2.137 10.62 2.151 ;
     RECT  13.2 2.137 13.32 2.151 ;
     RECT  15.9 2.137 16.02 2.151 ;
     RECT  18.6 2.137 18.72 2.151 ;
     RECT  21.3 2.137 21.42 2.151 ;
     RECT  24 2.137 24.12 2.151 ;
     RECT  26.7 2.137 26.82 2.151 ;
     RECT  29.4 2.137 29.52 2.151 ;
     RECT  32.1 2.137 32.22 2.151 ;
     RECT  34.8 2.137 34.92 2.151 ;
     RECT  7.8 2.151 8.112 2.245 ;
     RECT  15.9 2.151 16.212 2.245 ;
     RECT  21.3 2.151 21.612 2.245 ;
     RECT  13.2 2.151 13.512 2.773 ;
     RECT  10.5 2.151 10.812 2.821 ;
     RECT  24 2.151 24.312 3.013 ;
     RECT  18.6 2.151 18.912 3.061 ;
     RECT  32.1 2.151 32.412 3.205 ;
     RECT  7.8 2.245 8.52 3.301 ;
     RECT  9.696 2.821 10.812 3.301 ;
     RECT  20.688 2.245 21.612 3.347 ;
     RECT  15.552 2.245 16.212 3.349 ;
     RECT  9.552 3.301 10.812 3.397 ;
     RECT  13.104 2.773 13.512 3.443 ;
     RECT  21.168 3.347 21.612 3.637 ;
     RECT  15.552 3.349 17.16 3.683 ;
     RECT  24 3.013 25.128 3.685 ;
     RECT  6.864 3.301 8.52 3.827 ;
     RECT  31.968 3.205 32.412 3.877 ;
     RECT  5.1 2.151 5.412 3.925 ;
     RECT  15.696 3.683 17.16 3.925 ;
     RECT  31.968 3.877 33.048 3.925 ;
     RECT  31.872 3.925 33.048 3.973 ;
     RECT  15.696 3.925 17.352 4.019 ;
     RECT  21.168 3.637 22.248 4.021 ;
     RECT  31.872 3.973 33.528 4.067 ;
     RECT  18.48 3.061 18.912 4.115 ;
     RECT  9.552 3.397 10.92 4.163 ;
     RECT  31.968 4.067 33.528 4.163 ;
     RECT  24 3.685 25.368 4.405 ;
     RECT  26.7 2.151 27.012 4.405 ;
     RECT  4.56 3.925 5.412 4.547 ;
     RECT  24 4.405 27.012 4.547 ;
     RECT  6.864 3.827 8.112 4.643 ;
     RECT  7.344 4.643 8.112 4.789 ;
     RECT  13.2 3.443 13.512 4.981 ;
     RECT  18.6 4.115 18.912 5.077 ;
     RECT  10.5 4.163 10.92 5.125 ;
     RECT  9.504 4.885 9.528 5.171 ;
     RECT  4.656 4.547 5.412 5.173 ;
     RECT  28.176 2.245 28.2 5.173 ;
     RECT  29.4 2.151 29.712 5.173 ;
     RECT  28.176 5.173 29.712 5.219 ;
     RECT  18.6 5.077 19.848 5.221 ;
     RECT  21.168 4.021 22.68 5.221 ;
     RECT  18.6 5.221 22.68 5.315 ;
     RECT  4.656 5.173 5.88 5.557 ;
     RECT  17.328 4.019 17.352 5.557 ;
     RECT  22.656 5.315 22.68 5.557 ;
     RECT  24 4.547 24.312 5.557 ;
     RECT  25.344 4.547 27.012 5.557 ;
     RECT  17.232 5.557 17.352 5.603 ;
     RECT  3.84 5.557 5.88 5.653 ;
     RECT  15.696 4.019 16.212 5.653 ;
     RECT  10.5 5.125 11.688 5.701 ;
     RECT  9.744 5.701 11.688 5.747 ;
     RECT  22.656 5.557 27.012 5.747 ;
     RECT  13.2 4.981 13.992 5.797 ;
     RECT  12.672 5.797 13.992 5.891 ;
     RECT  18.6 5.315 21.612 5.989 ;
     RECT  7.344 4.789 8.376 6.085 ;
     RECT  34.8 2.151 35.112 6.229 ;
     RECT  9.744 5.747 10.812 6.323 ;
     RECT  22.656 5.747 25.272 6.323 ;
     RECT  15.648 5.653 16.212 6.419 ;
     RECT  18.288 5.989 21.612 6.563 ;
     RECT  12.672 5.891 13.512 6.805 ;
     RECT  15.696 6.419 16.212 6.805 ;
     RECT  17.232 5.603 17.256 6.805 ;
     RECT  32.1 4.163 33.528 6.805 ;
     RECT  34.704 6.229 35.112 6.947 ;
     RECT  18.288 6.563 18.912 7.043 ;
     RECT  22.656 6.323 25.128 7.091 ;
     RECT  26.7 5.747 27.012 7.189 ;
     RECT  28.512 5.219 29.712 7.189 ;
     RECT  15.696 6.805 17.256 7.619 ;
     RECT  7.248 6.085 8.376 7.765 ;
     RECT  26.7 7.189 27.192 7.909 ;
     RECT  28.512 7.189 30.648 7.909 ;
     RECT  2.4 2.151 2.712 7.957 ;
     RECT  20.496 6.563 21.612 7.957 ;
     RECT  22.656 7.091 22.68 7.957 ;
     RECT  17.232 7.619 17.256 8.003 ;
     RECT  26.7 7.909 30.648 8.005 ;
     RECT  31.872 6.805 33.528 8.005 ;
     RECT  26.7 8.005 33.528 8.195 ;
     RECT  18.6 7.043 18.912 8.245 ;
     RECT  15.696 7.619 16.212 8.291 ;
     RECT  26.7 8.195 30.792 8.483 ;
     RECT  12.096 6.805 13.512 8.485 ;
     RECT  20.496 7.957 22.68 8.485 ;
     RECT  26.7 8.483 30.648 8.579 ;
     RECT  24 7.091 25.128 8.725 ;
     RECT  2.304 7.957 2.712 8.773 ;
     RECT  3.696 5.653 5.88 8.773 ;
     RECT  2.304 8.773 5.88 8.821 ;
     RECT  7.248 7.765 9.336 9.011 ;
     RECT  18.48 8.245 18.912 9.107 ;
     RECT  2.304 8.821 5.976 9.155 ;
     RECT  11.904 8.485 13.512 9.155 ;
     RECT  20.16 8.485 22.68 9.253 ;
     RECT  2.4 9.155 5.976 9.445 ;
     RECT  7.248 9.011 9.096 9.445 ;
     RECT  26.7 8.579 27.912 9.637 ;
     RECT  28.944 8.579 30.648 9.637 ;
     RECT  32.1 8.195 33.528 9.637 ;
     RECT  34.8 6.947 35.112 9.637 ;
     RECT  26.7 9.637 30.648 9.683 ;
     RECT  20.112 9.253 22.68 9.731 ;
     RECT  26.7 9.683 27.144 9.827 ;
     RECT  24 8.725 25.272 9.925 ;
     RECT  26.7 9.827 27.012 9.925 ;
     RECT  28.224 9.683 30.648 9.925 ;
     RECT  32.1 9.637 35.112 9.925 ;
     RECT  28.224 9.925 35.112 9.971 ;
     RECT  2.4 9.445 9.096 10.355 ;
     RECT  4.176 10.355 9.096 10.403 ;
     RECT  20.112 9.731 22.536 10.643 ;
     RECT  18.6 9.107 18.912 10.741 ;
     RECT  7.248 10.403 9.096 10.789 ;
     RECT  31.44 9.971 35.112 10.835 ;
     RECT  28.224 9.971 29.712 10.883 ;
     RECT  10.5 6.323 10.812 10.933 ;
     RECT  15.9 8.291 16.212 10.981 ;
     RECT  15.216 10.981 16.212 11.171 ;
     RECT  4.176 10.403 5.976 11.315 ;
     RECT  24 9.925 27.012 11.365 ;
     RECT  15.9 11.171 16.212 11.413 ;
     RECT  4.176 11.315 5.88 11.459 ;
     RECT  20.592 10.643 22.536 11.459 ;
     RECT  15.9 11.413 16.392 11.509 ;
     RECT  15.9 11.509 16.584 11.651 ;
     RECT  4.752 11.459 5.88 11.699 ;
     RECT  31.92 10.835 35.112 11.699 ;
     RECT  10.5 10.933 11.208 11.701 ;
     RECT  12.24 9.155 13.512 11.701 ;
     RECT  10.5 11.701 13.512 11.987 ;
     RECT  21.024 11.459 22.536 11.989 ;
     RECT  7.248 10.789 9.144 12.037 ;
     RECT  7.248 12.037 9.384 12.133 ;
     RECT  18.048 10.741 18.912 12.325 ;
     RECT  32.1 11.699 33.432 12.419 ;
     RECT  2.4 10.355 2.712 12.517 ;
     RECT  7.248 12.133 9.432 12.565 ;
     RECT  10.5 11.987 10.812 12.565 ;
     RECT  21.024 11.989 22.968 12.755 ;
     RECT  24 11.365 27.384 12.901 ;
     RECT  23.712 12.901 27.384 13.043 ;
     RECT  12.24 11.987 13.512 13.045 ;
     RECT  17.808 12.325 18.912 13.045 ;
     RECT  24 13.043 27.384 13.139 ;
     RECT  28.944 10.883 29.712 13.477 ;
     RECT  34.8 11.699 35.112 13.573 ;
     RECT  28.944 13.477 30.168 13.621 ;
     RECT  17.808 13.045 19.608 13.667 ;
     RECT  28.272 13.621 30.168 13.667 ;
     RECT  15.9 11.651 16.212 13.669 ;
     RECT  21.024 12.755 22.728 13.715 ;
     RECT  32.1 12.419 33.384 13.765 ;
     RECT  31.968 13.765 33.384 14.099 ;
     RECT  0.144 13.909 0.168 14.195 ;
     RECT  21.12 13.715 22.728 14.243 ;
     RECT  34.8 13.573 35.352 14.243 ;
     RECT  2.4 12.517 3.336 14.387 ;
     RECT  17.808 13.667 18.912 14.581 ;
     RECT  15.9 13.669 16.344 14.965 ;
     RECT  15.9 14.965 16.584 15.013 ;
     RECT  17.568 14.581 18.912 15.013 ;
     RECT  21.168 14.243 22.728 15.013 ;
     RECT  24 13.139 27.012 15.013 ;
     RECT  12.24 13.045 14.376 15.059 ;
     RECT  21.168 15.013 27.012 15.251 ;
     RECT  34.8 14.243 35.112 15.301 ;
     RECT  0.144 15.205 0.168 15.395 ;
     RECT  7.248 12.565 10.812 15.397 ;
     RECT  22.704 15.251 27.012 15.539 ;
     RECT  21.168 15.251 21.612 15.589 ;
     RECT  7.008 15.397 10.812 16.069 ;
     RECT  12.24 15.059 13.848 16.069 ;
     RECT  32.1 14.099 33.288 16.165 ;
     RECT  7.008 16.069 13.848 16.355 ;
     RECT  2.4 14.387 2.712 16.405 ;
     RECT  31.008 14.821 31.032 16.499 ;
     RECT  12.24 16.355 13.848 16.547 ;
     RECT  25.632 15.539 27.012 16.547 ;
     RECT  22.704 15.539 24.312 16.645 ;
     RECT  0.144 16.597 0.168 16.883 ;
     RECT  22.704 16.645 24.408 16.885 ;
     RECT  25.632 16.547 25.656 16.885 ;
     RECT  20.592 15.589 21.612 17.029 ;
     RECT  22.704 16.885 25.656 17.029 ;
     RECT  7.008 16.355 10.812 17.077 ;
     RECT  20.592 17.029 25.656 17.219 ;
     RECT  12.24 16.547 13.704 17.267 ;
     RECT  34.8 15.301 35.208 17.267 ;
     RECT  6.864 17.077 10.812 17.461 ;
     RECT  12.24 17.267 13.656 17.461 ;
     RECT  4.752 11.699 5.412 17.605 ;
     RECT  4.752 17.605 5.736 17.699 ;
     RECT  32.1 16.165 33.624 17.891 ;
     RECT  26.7 16.547 27.012 18.133 ;
     RECT  5.1 17.699 5.736 18.181 ;
     RECT  6.864 17.461 13.656 18.181 ;
     RECT  20.592 17.219 25.128 18.275 ;
     RECT  34.8 17.267 35.112 18.469 ;
     RECT  28.272 13.667 29.712 18.565 ;
     RECT  2.4 16.405 3.192 18.707 ;
     RECT  5.1 18.181 13.656 18.709 ;
     RECT  5.1 18.709 13.752 18.803 ;
     RECT  34.8 18.469 35.976 18.803 ;
     RECT  6.864 18.803 13.752 18.851 ;
     RECT  20.592 18.275 22.488 18.851 ;
     RECT  15.9 15.013 18.912 18.901 ;
     RECT  32.1 17.891 32.412 18.949 ;
     RECT  5.1 18.803 5.736 18.995 ;
     RECT  33.6 17.891 33.624 19.237 ;
     RECT  23.616 18.275 25.128 19.283 ;
     RECT  27.984 18.565 29.712 19.283 ;
     RECT  33.6 19.237 33.72 19.283 ;
     RECT  29.184 19.283 29.712 19.285 ;
     RECT  21.3 18.851 22.488 19.333 ;
     RECT  23.616 19.283 24.408 19.333 ;
     RECT  21.3 19.333 24.408 19.619 ;
     RECT  26.304 18.133 27.012 19.813 ;
     RECT  7.008 18.851 13.752 19.955 ;
     RECT  34.8 18.803 35.112 19.957 ;
     RECT  7.008 19.955 13.656 20.003 ;
     RECT  31.248 18.949 32.412 20.003 ;
     RECT  33.696 19.283 33.72 20.003 ;
     RECT  10.368 20.003 13.656 20.099 ;
     RECT  27.984 19.283 28.008 20.339 ;
     RECT  29.184 19.285 29.928 20.485 ;
     RECT  0.192 20.341 0.216 20.531 ;
     RECT  10.368 20.099 13.512 20.531 ;
     RECT  14.976 18.901 18.912 20.579 ;
     RECT  24 19.619 24.408 20.629 ;
     RECT  21.3 19.619 22.776 20.675 ;
     RECT  5.1 18.995 5.64 20.677 ;
     RECT  21.3 20.675 22.488 20.915 ;
     RECT  1.248 20.677 1.272 20.963 ;
     RECT  4.128 20.677 5.64 20.963 ;
     RECT  34.704 19.957 35.112 20.963 ;
     RECT  14.976 20.579 16.584 21.491 ;
     RECT  4.224 20.963 5.64 21.493 ;
     RECT  7.008 20.003 9.144 21.493 ;
     RECT  4.224 21.493 9.144 21.635 ;
     RECT  6.48 21.635 9.144 21.683 ;
     RECT  17.664 20.579 18.912 21.683 ;
     RECT  12.24 20.531 13.512 21.971 ;
     RECT  34.8 20.963 35.112 22.021 ;
     RECT  33.696 21.541 33.72 22.067 ;
     RECT  23.808 20.629 24.408 22.069 ;
     RECT  10.368 20.531 10.812 22.165 ;
     RECT  23.568 22.069 24.408 22.309 ;
     RECT  25.632 19.813 27.012 22.309 ;
     RECT  4.224 21.635 5.412 22.453 ;
     RECT  4.176 22.453 5.412 22.549 ;
     RECT  23.568 22.309 27.012 22.597 ;
     RECT  21.3 20.915 21.612 23.125 ;
     RECT  3.888 22.549 5.412 23.315 ;
     RECT  6.48 21.683 8.76 23.315 ;
     RECT  34.8 22.021 35.592 23.317 ;
     RECT  4.176 23.315 5.412 23.363 ;
     RECT  10.32 22.165 10.812 23.411 ;
     RECT  23.568 22.597 27.192 23.411 ;
     RECT  13.008 21.971 13.512 23.749 ;
     RECT  12.528 23.749 13.512 23.893 ;
     RECT  29.136 20.485 29.928 23.893 ;
     RECT  34.704 23.317 35.592 23.987 ;
     RECT  29.136 23.893 30.264 24.083 ;
     RECT  21.3 23.125 22.2 24.277 ;
     RECT  5.1 23.363 5.412 24.469 ;
     RECT  12.24 23.893 13.704 24.659 ;
     RECT  33.408 23.317 33.432 24.659 ;
     RECT  21.3 24.277 22.248 24.709 ;
     RECT  7.008 23.315 8.76 24.997 ;
     RECT  18.6 21.683 18.912 24.997 ;
     RECT  34.704 23.987 35.112 24.997 ;
     RECT  21.168 24.709 22.248 25.045 ;
     RECT  25.728 23.411 27.192 25.091 ;
     RECT  21.168 25.045 22.536 25.237 ;
     RECT  34.704 24.997 35.592 25.285 ;
     RECT  23.568 23.411 24.312 25.333 ;
     RECT  5.1 24.469 5.88 25.475 ;
     RECT  5.1 25.475 5.688 25.477 ;
     RECT  10.368 23.411 10.812 25.525 ;
     RECT  20.88 25.237 22.536 25.621 ;
     RECT  14.976 21.491 16.212 25.667 ;
     RECT  19.968 25.621 22.536 25.667 ;
     RECT  15.264 25.667 16.212 25.715 ;
     RECT  19.968 25.667 22.248 25.715 ;
     RECT  33.744 25.285 35.592 25.715 ;
     RECT  33.744 25.715 35.112 25.763 ;
     RECT  32.1 20.003 32.412 25.813 ;
     RECT  12.24 24.659 13.512 26.053 ;
     RECT  31.872 25.813 32.412 26.053 ;
     RECT  33.744 25.763 33.768 26.053 ;
     RECT  33.6 26.053 33.768 26.243 ;
     RECT  18.192 24.997 18.912 26.245 ;
     RECT  33.744 26.243 33.768 26.387 ;
     RECT  25.776 25.091 27.192 26.485 ;
     RECT  15.36 25.715 16.212 26.581 ;
     RECT  4.848 25.477 5.688 26.629 ;
     RECT  31.872 26.053 32.568 26.675 ;
     RECT  23.568 25.333 24.504 26.677 ;
     RECT  25.776 26.485 27.96 26.677 ;
     RECT  19.968 25.715 21.612 26.771 ;
     RECT  4.848 26.629 5.736 26.773 ;
     RECT  10.368 25.525 11.112 26.819 ;
     RECT  23.568 26.677 27.96 26.819 ;
     RECT  32.1 26.675 32.568 26.819 ;
     RECT  4.848 26.773 5.928 26.867 ;
     RECT  15.36 26.581 16.344 27.013 ;
     RECT  7.008 24.997 9.096 27.059 ;
     RECT  2.4 18.707 2.712 27.301 ;
     RECT  23.568 26.819 24.504 27.301 ;
     RECT  29.184 24.083 30.264 27.301 ;
     RECT  15.024 27.013 16.344 27.443 ;
     RECT  10.5 26.819 11.112 27.637 ;
     RECT  12.24 26.053 13.608 27.637 ;
     RECT  22.752 27.301 24.504 27.683 ;
     RECT  34.8 25.763 35.112 27.685 ;
     RECT  7.8 27.059 9.096 27.733 ;
     RECT  25.776 26.819 27.96 27.877 ;
     RECT  29.04 27.301 30.984 27.877 ;
     RECT  25.776 27.877 30.984 28.307 ;
     RECT  15.024 27.443 16.212 28.403 ;
     RECT  10.5 27.637 13.608 28.405 ;
     RECT  2.4 27.301 3.576 28.547 ;
     RECT  22.752 27.683 24.456 28.691 ;
     RECT  10.5 28.405 13.656 28.933 ;
     RECT  3.936 28.789 3.96 28.979 ;
     RECT  25.776 28.307 27.192 29.075 ;
     RECT  30.768 28.307 30.984 29.075 ;
     RECT  10.5 28.933 13.992 29.123 ;
     RECT  28.224 28.307 29.712 29.507 ;
     RECT  10.5 29.123 10.92 29.603 ;
     RECT  7.8 27.733 9.144 29.605 ;
     RECT  15.504 28.403 16.212 29.605 ;
     RECT  32.1 26.819 32.412 29.605 ;
     RECT  23.568 28.691 24.456 29.699 ;
     RECT  25.776 29.075 27.012 29.747 ;
     RECT  23.904 29.699 24.456 29.891 ;
     RECT  18.096 26.245 18.912 30.131 ;
     RECT  15.504 29.605 16.536 30.275 ;
     RECT  30.768 29.075 30.792 30.275 ;
     RECT  33.936 27.685 35.112 30.373 ;
     RECT  25.92 29.747 27.012 30.611 ;
     RECT  11.904 29.123 13.992 30.709 ;
     RECT  15.504 30.275 16.212 30.709 ;
     RECT  7.68 29.605 9.144 30.851 ;
     RECT  38.544 30.757 38.568 30.899 ;
     RECT  26.208 30.611 27.012 31.187 ;
     RECT  28.656 29.507 29.712 31.189 ;
     RECT  30.72 30.949 30.744 31.189 ;
     RECT  33.936 30.373 35.208 31.189 ;
     RECT  5.1 26.867 5.928 31.237 ;
     RECT  20.064 26.771 21.612 31.379 ;
     RECT  24 29.891 24.456 31.429 ;
     RECT  22.8 30.229 22.824 31.475 ;
     RECT  28.656 31.189 30.744 31.477 ;
     RECT  31.92 29.605 32.412 31.477 ;
     RECT  7.68 30.851 8.112 31.667 ;
     RECT  10.5 29.603 10.812 31.669 ;
     RECT  9.12 30.851 9.144 31.811 ;
     RECT  11.904 30.709 16.212 31.907 ;
     RECT  33.936 31.189 35.352 31.907 ;
     RECT  18.144 30.131 18.912 31.909 ;
     RECT  23.808 31.429 24.456 31.955 ;
     RECT  28.656 31.477 32.412 31.955 ;
     RECT  34.176 31.907 35.352 32.339 ;
     RECT  20.16 31.379 21.612 32.485 ;
     RECT  26.592 31.187 27.012 32.485 ;
     RECT  5.1 31.237 5.976 32.531 ;
     RECT  24 31.955 24.456 32.725 ;
     RECT  17.664 31.909 18.912 33.011 ;
     RECT  12 31.907 16.212 33.107 ;
     RECT  28.896 31.955 32.412 33.539 ;
     RECT  34.176 32.339 35.208 33.539 ;
     RECT  31.152 33.539 32.412 33.587 ;
     RECT  10.368 31.669 10.812 33.875 ;
     RECT  12 33.107 14.52 33.923 ;
     RECT  28.896 33.539 29.712 34.069 ;
     RECT  19.968 32.485 21.612 34.115 ;
     RECT  12.48 33.923 14.52 34.117 ;
     RECT  15.552 33.107 16.212 34.117 ;
     RECT  17.952 33.011 18.912 34.211 ;
     RECT  31.392 33.587 32.412 34.355 ;
     RECT  34.704 33.539 35.208 34.357 ;
     RECT  24 32.725 24.6 34.501 ;
     RECT  28.08 34.069 29.712 34.501 ;
     RECT  18.6 34.211 18.912 34.933 ;
     RECT  5.1 32.531 5.928 34.981 ;
     RECT  34.704 34.357 35.256 35.029 ;
     RECT  25.68 32.485 27.012 35.171 ;
     RECT  23.568 34.501 24.6 35.267 ;
     RECT  28.08 34.501 29.928 35.269 ;
     RECT  7.8 31.667 8.112 35.317 ;
     RECT  10.5 33.875 10.812 35.317 ;
     RECT  34.704 35.029 35.352 35.509 ;
     RECT  4.128 34.981 5.928 35.555 ;
     RECT  7.8 35.317 8.232 35.845 ;
     RECT  12.48 34.117 16.212 35.891 ;
     RECT  14.496 35.891 16.212 36.037 ;
     RECT  34.512 35.509 35.352 36.083 ;
     RECT  18.6 34.933 19.176 36.131 ;
     RECT  12.48 35.891 13.512 36.229 ;
     RECT  10.5 35.317 10.92 36.275 ;
     RECT  14.496 36.037 16.392 36.325 ;
     RECT  14.496 36.325 16.488 36.467 ;
     RECT  12.432 36.229 13.512 36.515 ;
     RECT  23.568 35.267 24.504 36.515 ;
     RECT  15.408 36.467 16.488 36.517 ;
     RECT  7.68 35.845 8.232 36.613 ;
     RECT  7.68 36.613 8.76 36.659 ;
     RECT  26.592 35.171 27.012 36.659 ;
     RECT  15.408 36.517 16.776 36.707 ;
     RECT  26.7 36.659 27.012 36.709 ;
     RECT  28.08 35.269 30.168 36.709 ;
     RECT  12.48 36.515 13.512 36.997 ;
     RECT  7.8 36.659 8.76 37.043 ;
     RECT  20.16 34.115 21.612 37.045 ;
     RECT  26.7 36.709 30.168 37.091 ;
     RECT  12.48 36.997 14.28 37.187 ;
     RECT  4.512 35.555 5.928 37.379 ;
     RECT  20.016 37.045 21.612 37.381 ;
     RECT  10.5 36.275 10.812 37.429 ;
     RECT  24 36.515 24.504 37.573 ;
     RECT  26.7 37.091 29.88 37.667 ;
     RECT  26.7 37.667 27.012 37.717 ;
     RECT  31.728 34.355 32.412 38.051 ;
     RECT  26.448 37.717 27.012 38.147 ;
     RECT  7.8 37.043 8.568 38.149 ;
     RECT  34.512 36.083 35.208 38.149 ;
     RECT  27.984 37.667 29.88 38.291 ;
     RECT  18.6 36.131 19.032 38.483 ;
     RECT  5.1 37.379 5.928 38.485 ;
     RECT  7.8 38.149 9.096 38.677 ;
     RECT  10.368 37.429 10.812 38.677 ;
     RECT  4.56 38.485 5.928 38.771 ;
     RECT  12.48 37.187 13.656 39.061 ;
     RECT  31.872 38.051 32.412 39.109 ;
     RECT  7.8 38.677 10.812 39.251 ;
     RECT  20.016 37.381 21.72 39.443 ;
     RECT  20.16 39.443 21.72 39.589 ;
     RECT  34.464 38.149 35.208 39.683 ;
     RECT  26.544 38.147 27.012 39.875 ;
     RECT  27.984 38.291 29.712 39.875 ;
     RECT  12.48 39.061 14.28 39.877 ;
     RECT  15.504 36.707 16.776 40.019 ;
     RECT  34.8 39.683 35.208 40.115 ;
     RECT  5.1 38.771 5.928 40.165 ;
     RECT  7.8 39.251 9.096 40.165 ;
     RECT  31.488 39.109 32.412 40.165 ;
     RECT  12.096 39.877 14.28 40.355 ;
     RECT  0.144 40.117 0.168 40.403 ;
     RECT  23.472 37.573 25.128 41.075 ;
     RECT  31.392 40.165 32.412 41.075 ;
     RECT  23.472 41.075 24.696 41.123 ;
     RECT  18.6 38.483 18.912 41.173 ;
     RECT  20.16 39.589 22.152 41.173 ;
     RECT  18.6 41.173 22.152 41.317 ;
     RECT  1.248 41.221 1.272 41.363 ;
     RECT  5.1 40.165 9.096 41.461 ;
     RECT  10.5 39.251 10.812 41.461 ;
     RECT  26.7 39.875 27.012 41.461 ;
     RECT  5.1 41.461 10.812 41.557 ;
     RECT  12.096 40.355 13.512 41.557 ;
     RECT  5.1 41.557 13.512 41.603 ;
     RECT  5.1 41.603 11.256 41.651 ;
     RECT  31.488 41.075 32.412 42.037 ;
     RECT  5.1 41.651 5.928 42.227 ;
     RECT  17.904 41.317 22.152 42.467 ;
     RECT  15.504 40.019 16.536 42.515 ;
     RECT  12.48 41.603 13.512 42.709 ;
     RECT  7.8 41.651 11.256 42.803 ;
     RECT  28.224 39.875 29.712 42.853 ;
     RECT  31.392 42.037 32.412 42.853 ;
     RECT  20.16 42.467 22.152 43.043 ;
     RECT  28.224 42.853 32.412 43.045 ;
     RECT  7.8 42.803 10.812 43.139 ;
     RECT  17.904 42.467 19.08 43.139 ;
     RECT  7.8 43.139 8.232 43.141 ;
     RECT  5.1 42.227 5.592 43.285 ;
     RECT  28.224 43.045 32.52 43.619 ;
     RECT  26.7 41.461 27.144 43.621 ;
     RECT  28.224 43.619 32.412 43.621 ;
     RECT  34.8 40.115 35.112 43.669 ;
     RECT  5.1 43.285 5.832 43.813 ;
     RECT  21.168 43.043 22.152 43.859 ;
     RECT  7.296 43.141 8.232 43.955 ;
     RECT  26.7 43.621 32.412 43.955 ;
     RECT  20.16 43.043 20.184 44.101 ;
     RECT  21.168 43.859 21.612 44.101 ;
     RECT  26.7 43.955 29.712 44.197 ;
     RECT  20.16 44.101 21.612 44.291 ;
     RECT  15.504 42.515 16.488 44.341 ;
     RECT  5.1 43.813 6.216 44.483 ;
     RECT  34.224 43.669 35.112 44.483 ;
     RECT  31.392 43.955 32.412 44.675 ;
     RECT  25.824 44.197 29.712 44.867 ;
     RECT  32.1 44.675 32.412 44.869 ;
     RECT  12.48 42.709 13.656 44.965 ;
     RECT  5.1 44.483 5.592 45.157 ;
     RECT  4.992 45.157 5.592 45.491 ;
     RECT  9.6 43.139 10.812 45.541 ;
     RECT  12.48 44.965 13.704 45.541 ;
     RECT  18.6 43.139 19.08 45.541 ;
     RECT  21.168 44.291 21.612 45.635 ;
     RECT  9.6 45.541 13.704 45.827 ;
     RECT  15.504 44.341 16.536 45.827 ;
     RECT  30.72 45.733 30.744 45.829 ;
     RECT  18.192 45.541 19.08 46.067 ;
     RECT  25.968 44.867 29.712 46.211 ;
     RECT  25.968 46.211 28.248 46.259 ;
     RECT  9.696 45.827 13.704 46.547 ;
     RECT  15.504 45.827 16.488 46.739 ;
     RECT  15.504 46.739 16.44 46.835 ;
     RECT  18.192 46.067 18.912 46.835 ;
     RECT  32.1 44.869 33.048 46.883 ;
     RECT  20.16 44.291 20.184 47.029 ;
     RECT  9.696 46.547 10.812 47.171 ;
     RECT  26.592 46.259 28.248 47.173 ;
     RECT  29.28 46.211 29.712 47.173 ;
     RECT  3.696 43.861 3.72 47.363 ;
     RECT  21.3 45.635 21.612 47.413 ;
     RECT  12.48 46.547 13.704 47.555 ;
     RECT  24 41.123 24.696 47.605 ;
     RECT  23.376 47.605 24.696 47.701 ;
     RECT  2.4 28.547 2.712 47.845 ;
     RECT  13.2 47.555 13.704 47.845 ;
     RECT  23.28 47.701 24.696 47.989 ;
     RECT  3.84 48.181 3.864 48.277 ;
     RECT  2.4 47.845 2.856 48.325 ;
     RECT  3.84 48.277 3.912 48.325 ;
     RECT  32.1 46.883 32.412 48.373 ;
     RECT  23.28 47.989 25.608 48.419 ;
     RECT  2.4 48.325 3.912 48.421 ;
     RECT  18.432 46.835 18.912 48.421 ;
     RECT  19.968 47.029 20.184 48.421 ;
     RECT  30.72 45.829 30.984 48.421 ;
     RECT  32.1 48.373 33.048 48.421 ;
     RECT  34.8 44.483 35.112 48.469 ;
     RECT  15.504 46.835 16.344 48.515 ;
     RECT  9.12 48.229 9.144 48.661 ;
     RECT  13.2 47.845 14.28 48.661 ;
     RECT  15.504 48.515 16.212 48.661 ;
     RECT  7.296 43.955 8.112 48.757 ;
     RECT  9.12 48.661 9.192 48.757 ;
     RECT  12.336 48.661 16.212 48.757 ;
     RECT  7.296 48.757 9.192 48.803 ;
     RECT  18.432 48.421 20.184 48.901 ;
     RECT  21.168 47.413 21.612 48.901 ;
     RECT  2.4 48.421 3.96 48.997 ;
     RECT  5.1 45.491 5.592 48.997 ;
     RECT  18.432 48.901 21.612 49.043 ;
     RECT  23.28 48.419 25.08 49.043 ;
     RECT  12.24 48.757 16.212 49.091 ;
     RECT  26.592 47.173 29.712 49.139 ;
     RECT  15.504 49.091 16.212 49.235 ;
     RECT  2.4 48.997 5.592 49.477 ;
     RECT  15.9 49.235 16.212 49.477 ;
     RECT  29.28 49.139 29.712 49.477 ;
     RECT  30.72 48.421 33.048 49.477 ;
     RECT  15.9 49.477 16.44 49.525 ;
     RECT  18.432 49.043 20.184 49.525 ;
     RECT  23.28 49.043 24.696 49.571 ;
     RECT  26.592 49.139 28.248 49.621 ;
     RECT  0.144 46.789 0.168 49.811 ;
     RECT  7.296 48.803 9.144 49.861 ;
     RECT  26.4 49.621 28.248 49.909 ;
     RECT  29.28 49.477 33.048 50.051 ;
     RECT  2.4 49.477 5.784 50.101 ;
     RECT  7.296 49.861 9.192 50.195 ;
     RECT  12.24 49.091 14.28 50.195 ;
     RECT  18.192 49.525 20.184 50.197 ;
     RECT  21.168 49.043 21.612 50.197 ;
     RECT  34.464 48.469 35.112 50.483 ;
     RECT  7.68 50.195 9.192 50.677 ;
     RECT  10.5 47.171 10.812 50.677 ;
     RECT  29.28 50.051 32.412 50.771 ;
     RECT  26.16 49.909 28.248 51.011 ;
     RECT  7.68 50.677 10.812 51.059 ;
     RECT  23.472 49.571 24.696 51.061 ;
     RECT  2.4 50.101 6.264 51.107 ;
     RECT  12.24 50.195 13.608 51.205 ;
     RECT  12.24 51.205 14.28 51.253 ;
     RECT  2.4 51.107 5.784 51.395 ;
     RECT  18.192 50.197 21.612 51.443 ;
     RECT  20.16 51.443 21.612 51.493 ;
     RECT  5.1 51.395 5.784 51.587 ;
     RECT  34.704 50.483 35.112 51.637 ;
     RECT  34.704 51.637 35.208 51.683 ;
     RECT  0.144 51.349 0.168 51.731 ;
     RECT  7.68 51.059 8.112 51.733 ;
     RECT  18.192 51.443 19.032 51.923 ;
     RECT  12 51.253 14.28 51.971 ;
     RECT  15.9 49.525 16.536 51.971 ;
     RECT  20.16 51.493 22.104 51.971 ;
     RECT  29.4 50.771 32.412 52.213 ;
     RECT  23.136 51.061 24.696 52.261 ;
     RECT  26.16 51.011 28.056 52.261 ;
     RECT  2.4 51.395 3.96 52.357 ;
     RECT  5.1 51.587 5.688 52.357 ;
     RECT  29.232 52.213 32.412 52.451 ;
     RECT  2.4 52.357 5.688 52.499 ;
     RECT  7.104 51.733 8.112 52.499 ;
     RECT  21.3 51.971 22.104 52.499 ;
     RECT  29.4 52.451 32.412 52.547 ;
     RECT  12 51.971 14.232 52.691 ;
     RECT  23.136 52.261 28.056 52.693 ;
     RECT  18.192 51.923 18.912 52.981 ;
     RECT  20.16 51.971 20.328 52.981 ;
     RECT  23.136 52.693 28.248 52.981 ;
     RECT  9.168 51.059 10.812 53.029 ;
     RECT  18.192 52.981 20.328 53.317 ;
     RECT  21.3 52.499 21.612 53.317 ;
     RECT  32.1 52.547 32.412 53.317 ;
     RECT  32.1 53.317 33.096 53.365 ;
     RECT  34.8 51.683 35.208 53.365 ;
     RECT  1.248 53.317 1.272 53.555 ;
     RECT  2.4 52.499 3.096 53.603 ;
     RECT  12 52.691 13.608 53.603 ;
     RECT  23.136 52.981 28.392 53.603 ;
     RECT  4.32 52.499 5.688 53.653 ;
     RECT  18.192 53.317 21.612 53.653 ;
     RECT  18.192 53.653 21.768 53.749 ;
     RECT  4.128 53.653 5.688 53.843 ;
     RECT  18.192 53.749 21.816 53.843 ;
     RECT  15.9 51.971 16.44 53.845 ;
     RECT  19.92 53.843 21.816 53.845 ;
     RECT  23.136 53.603 28.248 53.939 ;
     RECT  7.68 52.499 8.112 53.941 ;
     RECT  9.12 53.029 10.812 53.941 ;
     RECT  29.4 52.547 31.032 54.085 ;
     RECT  32.1 53.365 35.208 54.085 ;
     RECT  4.32 53.843 5.688 54.227 ;
     RECT  19.92 53.845 22.008 54.371 ;
     RECT  29.4 54.085 35.208 54.371 ;
     RECT  12.24 53.603 13.608 54.373 ;
     RECT  19.92 54.371 21.816 54.419 ;
     RECT  23.376 53.939 28.248 54.565 ;
     RECT  15.648 53.845 16.44 54.613 ;
     RECT  12.24 54.373 13.656 54.659 ;
     RECT  23.376 54.565 28.296 54.851 ;
     RECT  12.24 54.659 13.608 55.139 ;
     RECT  34.8 54.371 35.208 55.139 ;
     RECT  2.4 53.603 3.048 55.237 ;
     RECT  4.992 54.227 5.688 55.237 ;
     RECT  15.648 54.613 16.584 55.285 ;
     RECT  18.192 53.843 18.912 55.379 ;
     RECT  19.92 54.419 21.612 55.523 ;
     RECT  23.376 54.851 28.248 55.525 ;
     RECT  12.24 55.139 13.512 55.621 ;
     RECT  14.832 55.285 16.584 55.813 ;
     RECT  12.144 55.621 13.512 55.907 ;
     RECT  14.64 55.813 16.584 55.907 ;
     RECT  2.4 55.237 3.432 56.387 ;
     RECT  4.656 55.237 5.688 56.389 ;
     RECT  7.68 53.941 10.812 56.389 ;
     RECT  29.4 54.371 33.384 56.389 ;
     RECT  7.104 56.389 10.812 56.675 ;
     RECT  23.04 55.525 28.248 56.677 ;
     RECT  29.28 56.389 33.384 56.677 ;
     RECT  23.04 56.677 33.384 56.723 ;
     RECT  23.04 56.723 33.096 56.867 ;
     RECT  12.24 55.907 13.512 57.059 ;
     RECT  34.8 55.139 35.112 57.061 ;
     RECT  20.064 55.523 21.612 57.109 ;
     RECT  23.04 56.867 32.412 57.109 ;
     RECT  20.064 57.109 32.412 57.203 ;
     RECT  15.648 55.907 16.584 57.299 ;
     RECT  14.64 55.907 14.664 57.347 ;
     RECT  9.216 56.675 10.812 57.395 ;
     RECT  4.56 56.389 5.688 57.397 ;
     RECT  20.064 57.203 22.824 57.635 ;
     RECT  24 57.203 32.412 57.635 ;
     RECT  15.648 57.299 16.44 57.733 ;
     RECT  2.4 56.387 2.712 57.973 ;
     RECT  4.176 57.397 5.688 57.973 ;
     RECT  34.464 57.061 35.112 58.019 ;
     RECT  7.104 56.675 8.112 58.069 ;
     RECT  9.216 57.395 9.24 58.069 ;
     RECT  7.104 58.069 9.24 58.117 ;
     RECT  31.344 57.635 32.412 58.163 ;
     RECT  18.24 55.379 18.912 58.213 ;
     RECT  24 57.635 29.832 58.403 ;
     RECT  2.4 57.973 5.688 58.547 ;
     RECT  21.3 57.635 22.824 58.595 ;
     RECT  24 58.403 28.056 58.643 ;
     RECT  20.064 57.635 20.328 58.645 ;
     RECT  21.3 58.595 22.2 58.645 ;
     RECT  20.064 58.645 22.2 58.691 ;
     RECT  17.616 58.213 18.912 58.739 ;
     RECT  31.968 58.163 32.412 58.739 ;
     RECT  4.032 58.547 5.688 58.787 ;
     RECT  7.008 58.117 9.24 58.885 ;
     RECT  4.56 58.787 5.688 59.075 ;
     RECT  20.064 58.691 21.612 59.171 ;
     RECT  4.992 59.075 5.688 59.173 ;
     RECT  6.864 58.885 9.24 59.221 ;
     RECT  24 58.643 25.56 59.221 ;
     RECT  14.784 57.733 16.44 59.269 ;
     RECT  34.8 58.019 35.112 59.269 ;
     RECT  20.064 59.171 20.328 59.315 ;
     RECT  14.784 59.269 16.968 59.411 ;
     RECT  29.4 58.403 29.832 59.461 ;
     RECT  20.16 59.315 20.328 59.507 ;
     RECT  29.28 59.461 29.832 59.701 ;
     RECT  4.992 59.173 5.736 59.749 ;
     RECT  6.768 59.221 9.24 59.749 ;
     RECT  4.992 59.749 9.24 59.797 ;
     RECT  10.5 57.395 10.812 59.797 ;
     RECT  18.6 58.739 18.912 59.797 ;
     RECT  4.992 59.797 10.812 59.843 ;
     RECT  14.784 59.411 16.872 59.891 ;
     RECT  15.648 59.891 16.872 59.987 ;
     RECT  2.4 58.547 2.904 60.179 ;
     RECT  13.104 57.059 13.512 60.277 ;
     RECT  32.1 58.739 32.412 60.277 ;
     RECT  12.096 59.029 12.12 60.373 ;
     RECT  13.104 60.277 13.608 60.373 ;
     RECT  12.096 60.373 13.608 60.419 ;
     RECT  4.992 59.843 8.376 60.421 ;
     RECT  18.192 59.797 18.912 60.467 ;
     RECT  34.8 59.269 35.352 60.515 ;
     RECT  4.176 60.421 8.376 60.563 ;
     RECT  20.16 59.507 20.28 60.709 ;
     RECT  21.3 59.171 21.612 60.709 ;
     RECT  31.92 60.277 32.412 60.901 ;
     RECT  29.28 59.701 30.216 60.947 ;
     RECT  26.7 58.643 28.056 60.949 ;
     RECT  29.28 60.947 29.712 60.949 ;
     RECT  2.4 60.179 2.856 61.043 ;
     RECT  23.328 59.221 25.56 61.091 ;
     RECT  20.16 60.709 21.612 61.189 ;
     RECT  18.6 60.467 18.912 61.429 ;
     RECT  12.528 60.419 13.608 61.571 ;
     RECT  18.48 61.429 18.912 61.573 ;
     RECT  20.16 61.189 21.72 61.573 ;
     RECT  31.44 60.901 32.412 61.619 ;
     RECT  13.104 61.571 13.608 61.763 ;
     RECT  18.48 61.573 21.72 62.149 ;
     RECT  26.7 60.949 29.712 62.195 ;
     RECT  15.648 59.987 16.44 62.293 ;
     RECT  4.176 60.563 8.328 62.435 ;
     RECT  2.4 61.043 2.712 62.581 ;
     RECT  26.7 62.195 28.056 63.107 ;
     RECT  13.104 61.763 13.512 63.205 ;
     RECT  13.104 63.205 14.28 63.299 ;
     RECT  18.48 62.149 22.2 63.397 ;
     RECT  9.696 59.843 10.812 63.491 ;
     RECT  15.648 62.293 17.064 63.541 ;
     RECT  4.464 62.435 8.328 63.589 ;
     RECT  34.8 60.515 35.112 63.637 ;
     RECT  24 61.091 25.56 63.685 ;
     RECT  26.7 63.107 27.672 63.685 ;
     RECT  15.648 63.541 17.256 63.827 ;
     RECT  15.648 63.827 17.064 63.875 ;
     RECT  4.464 63.589 8.76 64.019 ;
     RECT  15.648 63.875 16.536 64.021 ;
     RECT  4.464 64.019 5.592 64.067 ;
     RECT  13.2 63.299 14.28 64.067 ;
     RECT  24 63.685 27.672 64.213 ;
     RECT  18.432 63.397 22.2 64.307 ;
     RECT  29.4 62.195 29.712 64.597 ;
     RECT  24 64.213 27.768 64.643 ;
     RECT  10.224 63.491 10.812 64.645 ;
     RECT  31.92 61.619 32.412 64.931 ;
     RECT  24 64.643 25.368 64.979 ;
     RECT  38.688 64.405 38.712 64.979 ;
     RECT  4.752 64.067 5.592 65.077 ;
     RECT  6.864 64.019 8.76 65.077 ;
     RECT  4.752 65.077 8.76 65.123 ;
     RECT  4.752 65.123 5.928 65.267 ;
     RECT  24 64.979 25.32 65.459 ;
     RECT  26.352 64.643 27.768 65.509 ;
     RECT  0.144 64.789 0.168 65.555 ;
     RECT  13.2 64.067 13.704 65.603 ;
     RECT  32.1 64.931 32.412 65.701 ;
     RECT  33.696 64.837 33.72 65.701 ;
     RECT  4.992 65.267 5.928 65.795 ;
     RECT  32.1 65.701 33.72 65.987 ;
     RECT  24 65.459 25.176 66.085 ;
     RECT  9.84 64.645 10.812 66.179 ;
     RECT  7.68 65.123 8.76 66.323 ;
     RECT  10.176 66.179 10.812 66.325 ;
     RECT  11.952 65.461 11.976 66.325 ;
     RECT  18.432 64.307 22.008 66.515 ;
     RECT  20.16 66.515 22.008 66.565 ;
     RECT  2.4 62.581 3.336 66.709 ;
     RECT  7.68 66.323 8.568 66.755 ;
     RECT  26.352 65.509 27.912 66.803 ;
     RECT  15.36 64.021 16.536 66.805 ;
     RECT  10.176 66.325 11.976 66.853 ;
     RECT  13.2 65.603 13.512 66.853 ;
     RECT  7.8 66.755 8.568 66.899 ;
     RECT  20.16 66.565 22.2 66.901 ;
     RECT  15.36 66.805 16.92 67.285 ;
     RECT  33.696 65.987 33.72 67.429 ;
     RECT  34.8 63.637 35.256 67.429 ;
     RECT  33.696 67.429 35.256 67.475 ;
     RECT  20.16 66.901 22.248 67.523 ;
     RECT  15.36 67.285 17.112 67.571 ;
     RECT  32.1 65.987 32.412 67.669 ;
     RECT  7.8 66.899 8.112 67.765 ;
     RECT  15.9 67.571 17.112 67.811 ;
     RECT  10.176 66.853 13.512 67.907 ;
     RECT  18.432 66.515 18.912 68.053 ;
     RECT  17.952 68.053 18.912 68.243 ;
     RECT  34.032 67.475 35.256 68.243 ;
     RECT  23.472 66.085 25.176 68.341 ;
     RECT  26.592 66.803 27.912 68.341 ;
     RECT  2.4 66.709 3.672 68.389 ;
     RECT  23.472 68.341 27.912 68.435 ;
     RECT  15.9 67.811 16.92 68.629 ;
     RECT  20.16 67.523 22.2 68.771 ;
     RECT  15.648 68.629 16.92 69.011 ;
     RECT  5.1 65.795 5.928 69.397 ;
     RECT  29.088 64.597 29.712 69.491 ;
     RECT  4.896 69.397 5.928 69.493 ;
     RECT  29.4 69.491 29.712 69.493 ;
     RECT  7.68 67.765 8.112 69.539 ;
     RECT  21.12 68.771 22.2 69.539 ;
     RECT  23.472 68.435 27.336 69.731 ;
     RECT  2.4 68.389 3.816 69.971 ;
     RECT  23.472 69.731 25.512 70.069 ;
     RECT  26.7 69.731 27.336 70.115 ;
     RECT  32.1 67.669 32.808 70.163 ;
     RECT  15.9 69.011 16.536 70.645 ;
     RECT  21.12 69.539 21.612 70.789 ;
     RECT  23.376 70.069 25.512 70.837 ;
     RECT  2.4 69.971 3.672 71.221 ;
     RECT  4.8 69.493 5.928 71.221 ;
     RECT  7.8 69.539 8.112 71.221 ;
     RECT  20.736 70.789 21.612 71.221 ;
     RECT  29.4 69.493 30.552 71.221 ;
     RECT  34.032 68.243 35.112 71.221 ;
     RECT  20.736 71.221 22.296 71.315 ;
     RECT  14.544 71.125 14.568 71.701 ;
     RECT  23.376 70.837 25.608 71.701 ;
     RECT  26.7 70.115 27.192 71.749 ;
     RECT  23.328 71.701 25.608 71.843 ;
     RECT  15.9 70.645 17.064 71.891 ;
     RECT  26.7 71.749 27.576 71.891 ;
     RECT  33.6 71.221 35.112 72.035 ;
     RECT  21.12 71.315 22.296 72.037 ;
     RECT  23.328 71.843 25.512 72.037 ;
     RECT  21.12 72.037 25.512 72.131 ;
     RECT  19.92 71.797 19.944 72.275 ;
     RECT  21.12 72.131 21.768 72.323 ;
     RECT  28.752 71.221 30.552 72.371 ;
     RECT  7.8 71.221 8.712 72.469 ;
     RECT  10.5 67.907 13.512 72.469 ;
     RECT  23.088 72.131 25.512 72.805 ;
     RECT  26.7 71.891 27.192 72.805 ;
     RECT  15.9 71.891 16.344 72.995 ;
     RECT  29.4 72.371 30.552 73.187 ;
     RECT  14.544 71.701 14.856 73.283 ;
     RECT  10.272 72.469 13.512 73.331 ;
     RECT  14.832 73.283 14.856 73.331 ;
     RECT  29.4 73.187 29.976 73.861 ;
     RECT  23.088 72.805 27.192 73.909 ;
     RECT  12.24 73.331 13.512 74.053 ;
     RECT  15.9 72.995 16.212 74.053 ;
     RECT  32.1 70.163 32.412 74.053 ;
     RECT  7.104 72.469 8.712 74.099 ;
     RECT  23.088 73.909 27.576 74.099 ;
     RECT  21.12 72.323 21.612 74.293 ;
     RECT  20.688 74.293 21.612 74.531 ;
     RECT  15.12 74.053 16.212 74.533 ;
     RECT  29.04 73.861 29.976 74.581 ;
     RECT  31.728 74.053 32.412 74.629 ;
     RECT  7.104 74.099 8.112 74.675 ;
     RECT  7.296 74.675 8.112 74.915 ;
     RECT  10.5 73.331 11.256 74.965 ;
     RECT  7.68 74.915 8.112 75.157 ;
     RECT  10.368 74.965 11.256 75.203 ;
     RECT  7.68 75.157 8.808 75.299 ;
     RECT  12.24 74.053 13.608 75.299 ;
     RECT  29.04 74.581 30.264 75.299 ;
     RECT  23.088 74.099 24.456 75.781 ;
     RECT  25.872 74.099 27.576 75.781 ;
     RECT  34.032 72.035 35.112 75.781 ;
     RECT  2.4 71.221 5.928 75.971 ;
     RECT  31.728 74.629 32.904 76.019 ;
     RECT  15.12 74.533 16.584 76.067 ;
     RECT  32.1 76.019 32.904 76.163 ;
     RECT  23.088 75.781 24.504 76.261 ;
     RECT  18.6 68.243 18.912 76.309 ;
     RECT  25.872 75.781 27.624 76.309 ;
     RECT  29.04 75.299 29.712 76.309 ;
     RECT  23.04 76.261 24.504 76.787 ;
     RECT  0.192 76.693 0.216 76.883 ;
     RECT  10.5 75.203 11.256 76.931 ;
     RECT  2.4 75.971 3.672 77.027 ;
     RECT  15.9 76.067 16.584 77.077 ;
     RECT  32.1 76.163 32.412 77.173 ;
     RECT  10.5 76.931 11.208 77.267 ;
     RECT  23.04 76.787 24.456 77.363 ;
     RECT  18.6 76.309 19.8 77.413 ;
     RECT  18.048 77.413 19.8 77.461 ;
     RECT  21.12 74.531 21.612 77.461 ;
     RECT  25.872 76.309 29.712 77.555 ;
     RECT  10.5 77.267 11.112 77.701 ;
     RECT  23.232 77.363 24.456 77.941 ;
     RECT  25.872 77.555 27.864 77.941 ;
     RECT  31.248 77.173 32.412 78.131 ;
     RECT  7.68 75.299 8.52 78.469 ;
     RECT  15.9 77.077 16.776 78.469 ;
     RECT  18.048 77.461 21.612 78.469 ;
     RECT  1.152 78.325 1.176 78.515 ;
     RECT  23.232 77.941 27.864 78.515 ;
     RECT  12.24 75.299 13.512 78.613 ;
     RECT  15.9 78.469 21.612 78.659 ;
     RECT  34.032 75.781 35.208 78.659 ;
     RECT  15.9 78.659 16.776 78.707 ;
     RECT  3.936 78.997 3.96 79.283 ;
     RECT  7.68 78.469 9.096 79.283 ;
     RECT  15.9 78.707 16.212 79.573 ;
     RECT  10.224 77.701 11.112 79.715 ;
     RECT  34.176 78.659 35.208 79.765 ;
     RECT  26.592 78.515 27.72 79.859 ;
     RECT  18.048 78.659 21.612 80.003 ;
     RECT  15.792 79.573 16.212 80.101 ;
     RECT  18.048 80.003 18.912 80.147 ;
     RECT  23.232 78.515 25.272 80.243 ;
     RECT  19.968 80.003 21.612 80.339 ;
     RECT  26.592 79.859 27.672 80.387 ;
     RECT  23.376 80.243 25.272 80.435 ;
     RECT  38.736 69.781 38.76 80.435 ;
     RECT  12.24 78.613 13.656 80.531 ;
     RECT  7.68 79.283 8.376 80.677 ;
     RECT  5.1 75.971 5.928 80.773 ;
     RECT  15.504 80.101 16.212 80.773 ;
     RECT  7.68 80.677 9.144 80.819 ;
     RECT  29.04 77.555 29.712 80.821 ;
     RECT  23.712 80.435 25.272 80.915 ;
     RECT  15.504 80.773 17.112 80.963 ;
     RECT  26.7 80.387 27.672 81.011 ;
     RECT  24 80.915 25.272 81.205 ;
     RECT  29.04 80.821 29.832 81.349 ;
     RECT  7.68 80.819 8.376 81.445 ;
     RECT  21.168 80.339 21.612 81.445 ;
     RECT  28.464 81.349 29.832 81.539 ;
     RECT  18.6 80.147 18.912 81.589 ;
     RECT  19.968 80.339 19.992 81.589 ;
     RECT  18.6 81.589 20.04 81.973 ;
     RECT  21.072 81.445 21.612 81.973 ;
     RECT  15.504 80.963 17.016 82.019 ;
     RECT  18.6 81.973 21.612 82.021 ;
     RECT  18.6 82.021 22.344 82.067 ;
     RECT  5.1 80.773 6.312 82.115 ;
     RECT  10.5 79.715 11.112 82.213 ;
     RECT  12.24 80.531 13.512 82.213 ;
     RECT  15.9 82.019 17.016 82.357 ;
     RECT  15.9 82.357 17.112 82.499 ;
     RECT  10.5 82.213 13.512 82.547 ;
     RECT  15.9 82.499 16.776 82.595 ;
     RECT  7.392 81.445 8.376 82.691 ;
     RECT  19.92 82.067 22.344 82.691 ;
     RECT  28.464 81.539 29.712 82.691 ;
     RECT  12.24 82.547 13.512 82.741 ;
     RECT  5.1 82.115 5.928 83.075 ;
     RECT  34.08 79.765 35.208 83.219 ;
     RECT  18.6 82.067 18.912 83.221 ;
     RECT  12.24 82.741 14.232 83.267 ;
     RECT  34.08 83.219 35.112 83.267 ;
     RECT  19.968 82.691 22.344 83.557 ;
     RECT  7.8 82.691 8.376 83.701 ;
     RECT  10.5 82.547 11.112 83.701 ;
     RECT  12.24 83.267 13.512 83.701 ;
     RECT  7.8 83.701 9.096 83.749 ;
     RECT  3.936 83.605 3.96 83.795 ;
     RECT  2.4 77.027 2.712 83.797 ;
     RECT  15.9 82.595 16.212 84.085 ;
     RECT  19.968 83.557 22.824 84.131 ;
     RECT  28.896 82.691 29.712 84.133 ;
     RECT  19.968 84.131 21.612 84.179 ;
     RECT  15.9 84.085 16.392 84.229 ;
     RECT  18.384 83.221 18.912 84.277 ;
     RECT  19.968 84.179 20.136 84.277 ;
     RECT  32.1 78.131 32.412 84.325 ;
     RECT  18.384 84.277 20.136 84.467 ;
     RECT  15.9 84.229 16.728 84.517 ;
     RECT  18.384 84.467 18.912 84.611 ;
     RECT  22.8 84.131 22.824 84.613 ;
     RECT  22.8 84.613 22.92 84.659 ;
     RECT  15.792 84.517 16.728 84.709 ;
     RECT  24 81.205 25.56 84.757 ;
     RECT  34.8 83.267 35.112 84.757 ;
     RECT  5.1 83.075 5.412 84.853 ;
     RECT  15.504 84.709 16.728 84.899 ;
     RECT  6.816 83.749 9.096 85.139 ;
     RECT  31.872 84.325 32.412 85.333 ;
     RECT  34.464 84.757 35.112 85.427 ;
     RECT  20.112 84.467 20.136 85.523 ;
     RECT  10.5 83.701 13.512 85.571 ;
     RECT  24 84.757 25.608 85.667 ;
     RECT  2.4 83.797 3.336 85.813 ;
     RECT  2.4 85.813 3.48 85.909 ;
     RECT  4.896 84.853 5.412 85.909 ;
     RECT  26.7 81.011 27.336 85.957 ;
     RECT  10.5 85.571 11.112 86.005 ;
     RECT  34.704 85.427 35.112 86.099 ;
     RECT  6.816 85.139 8.112 86.147 ;
     RECT  9.696 86.005 11.112 86.341 ;
     RECT  2.4 85.909 5.412 86.437 ;
     RECT  22.896 84.659 22.92 86.581 ;
     RECT  22.8 86.581 22.92 86.627 ;
     RECT  26.208 85.957 27.336 86.771 ;
     RECT  15.792 84.899 16.728 86.773 ;
     RECT  2.4 86.437 5.592 87.061 ;
     RECT  2.4 87.061 5.928 87.109 ;
     RECT  2.4 87.109 6.36 87.157 ;
     RECT  7.8 86.147 8.112 87.157 ;
     RECT  18.48 84.611 18.912 87.157 ;
     RECT  15.072 86.773 16.728 87.251 ;
     RECT  22.8 86.627 22.824 87.251 ;
     RECT  15.216 87.251 16.728 87.397 ;
     RECT  12.384 85.571 13.512 87.589 ;
     RECT  0.144 86.965 0.168 87.635 ;
     RECT  12.384 87.589 13.704 87.683 ;
     RECT  2.4 87.157 8.112 87.733 ;
     RECT  9.552 86.341 11.112 87.733 ;
     RECT  31.2 85.333 32.412 87.827 ;
     RECT  24 85.667 25.128 87.829 ;
     RECT  28.56 84.133 29.712 87.875 ;
     RECT  2.4 87.733 11.4 88.115 ;
     RECT  26.208 86.771 27.012 88.115 ;
     RECT  12.432 87.683 13.704 88.357 ;
     RECT  12.432 88.357 13.896 88.403 ;
     RECT  15.216 87.397 17.064 88.403 ;
     RECT  23.904 87.829 25.128 88.595 ;
     RECT  34.8 86.099 35.112 88.741 ;
     RECT  2.4 88.115 4.056 88.787 ;
     RECT  34.224 88.741 35.208 88.883 ;
     RECT  21.3 84.179 21.612 88.885 ;
     RECT  28.944 87.875 29.712 88.931 ;
     RECT  2.4 88.787 3.672 88.979 ;
     RECT  5.1 88.115 11.4 88.979 ;
     RECT  12.576 88.403 13.896 89.027 ;
     RECT  13.2 89.027 13.896 89.125 ;
     RECT  15.216 88.403 16.212 89.125 ;
     RECT  23.904 88.595 24.744 89.219 ;
     RECT  32.1 87.827 32.412 89.269 ;
     RECT  7.68 88.979 11.4 89.411 ;
     RECT  13.2 89.125 16.212 89.413 ;
     RECT  7.68 89.411 11.256 89.507 ;
     RECT  34.224 88.883 35.112 89.555 ;
     RECT  22.608 87.733 22.632 89.699 ;
     RECT  9.696 89.507 11.256 89.747 ;
     RECT  20.496 88.885 21.612 89.843 ;
     RECT  5.1 88.979 6.36 90.037 ;
     RECT  26.4 88.115 27.012 90.037 ;
     RECT  29.04 88.931 29.712 90.083 ;
     RECT  21.3 89.843 21.612 90.229 ;
     RECT  13.2 89.413 16.536 90.515 ;
     RECT  5.1 90.037 6.792 90.659 ;
     RECT  26.208 90.037 27.012 90.803 ;
     RECT  7.8 89.507 8.328 90.901 ;
     RECT  9.696 89.747 11.112 90.901 ;
     RECT  7.8 90.901 11.112 90.949 ;
     RECT  13.2 90.515 14.808 91.091 ;
     RECT  15.9 90.515 16.536 91.091 ;
     RECT  2.4 88.979 2.712 91.141 ;
     RECT  13.2 91.091 13.608 91.189 ;
     RECT  18.48 87.157 19.464 91.235 ;
     RECT  14.736 91.091 14.808 91.283 ;
     RECT  24 89.219 24.744 91.331 ;
     RECT  13.056 91.189 13.608 91.475 ;
     RECT  7.8 90.949 11.4 91.477 ;
     RECT  5.1 90.659 6.36 91.571 ;
     RECT  14.736 91.283 14.76 91.667 ;
     RECT  2.4 91.141 3.528 91.717 ;
     RECT  18.48 91.235 18.912 91.763 ;
     RECT  31.824 89.269 32.412 91.763 ;
     RECT  5.1 91.571 5.688 91.811 ;
     RECT  2.4 91.717 3.96 91.907 ;
     RECT  13.056 91.475 13.512 91.907 ;
     RECT  21.3 90.229 22.248 92.147 ;
     RECT  13.104 91.907 13.512 92.387 ;
     RECT  3.936 91.907 3.96 92.435 ;
     RECT  7.8 91.477 11.784 92.435 ;
     RECT  10.5 92.435 11.784 92.819 ;
     RECT  2.4 91.907 2.712 92.889 ;
     RECT  5.1 91.811 5.412 92.889 ;
     RECT  7.8 92.435 8.112 92.889 ;
     RECT  13.2 92.387 13.512 92.889 ;
     RECT  15.9 91.091 16.212 92.889 ;
     RECT  18.6 91.763 18.912 92.889 ;
     RECT  21.3 92.147 21.612 92.889 ;
     RECT  24 91.331 24.312 92.889 ;
     RECT  26.7 90.803 27.012 92.889 ;
     RECT  29.4 90.083 29.712 92.889 ;
     RECT  32.1 91.763 32.412 92.889 ;
     RECT  34.8 89.555 35.112 92.889 ;
     RECT  2.4 92.889 2.52 92.903 ;
     RECT  5.1 92.889 5.22 92.903 ;
     RECT  7.8 92.889 7.92 92.903 ;
     RECT  10.5 92.819 11.112 92.903 ;
     RECT  13.2 92.889 13.32 92.903 ;
     RECT  15.9 92.889 16.02 92.903 ;
     RECT  18.6 92.889 18.72 92.903 ;
     RECT  21.3 92.889 21.42 92.903 ;
     RECT  24 92.889 24.12 92.903 ;
     RECT  26.7 92.889 26.82 92.903 ;
     RECT  29.4 92.889 29.52 92.903 ;
     RECT  32.1 92.889 32.22 92.903 ;
     RECT  34.8 92.889 34.92 92.903 ;
     RECT  10.896 92.903 11.112 94.693 ;
     RECT  10.896 94.693 11.208 94.885 ;
     RECT  10.896 94.885 11.304 94.992 ;
     RECT  11.28 94.992 11.304 95.027 ;
  END
END dsfd_dvland_512
END LIBRARY
